VERSION 5.8 ;
BUSBITCHARS "[]" ;
DIVIDERCHAR "/" ;
UNITS
    DATABASE MICRONS 1000 ;
END UNITS

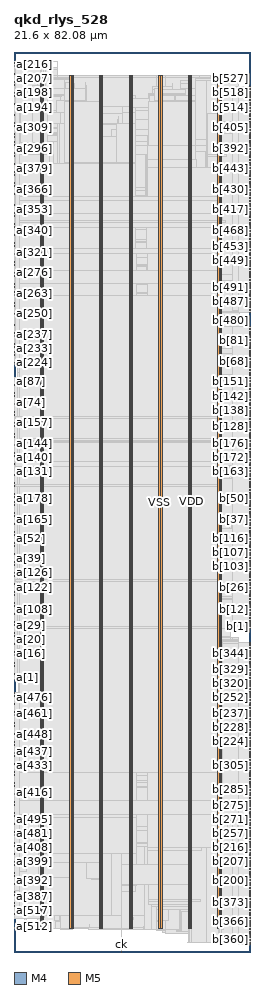
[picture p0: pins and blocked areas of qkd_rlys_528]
MACRO qkd_rlys_528
  FOREIGN qkd_rlys_528 0 0 ;
  CLASS BLOCK ;
  SIZE 21.6 BY 82.08 ;
  PIN a[0]
    DIRECTION INPUT ;
    USE SIGNAL ;
    PORT
      LAYER M4 ;
        RECT  0 24.912 0.084 24.936 ;
    END
  END a[0]
  PIN a[100]
    DIRECTION INPUT ;
    USE SIGNAL ;
    PORT
      LAYER M4 ;
        RECT  0 30.096 0.084 30.12 ;
    END
  END a[100]
  PIN a[101]
    DIRECTION INPUT ;
    USE SIGNAL ;
    PORT
      LAYER M4 ;
        RECT  0 30.24 0.084 30.264 ;
    END
  END a[101]
  PIN a[102]
    DIRECTION INPUT ;
    USE SIGNAL ;
    PORT
      LAYER M4 ;
        RECT  0 30.384 0.084 30.408 ;
    END
  END a[102]
  PIN a[103]
    DIRECTION INPUT ;
    USE SIGNAL ;
    PORT
      LAYER M4 ;
        RECT  0 30.528 0.084 30.552 ;
    END
  END a[103]
  PIN a[104]
    DIRECTION INPUT ;
    USE SIGNAL ;
    PORT
      LAYER M4 ;
        RECT  0 30.672 0.084 30.696 ;
    END
  END a[104]
  PIN a[105]
    DIRECTION INPUT ;
    USE SIGNAL ;
    PORT
      LAYER M4 ;
        RECT  0 30.816 0.084 30.84 ;
    END
  END a[105]
  PIN a[106]
    DIRECTION INPUT ;
    USE SIGNAL ;
    PORT
      LAYER M4 ;
        RECT  0 30.96 0.084 30.984 ;
    END
  END a[106]
  PIN a[107]
    DIRECTION INPUT ;
    USE SIGNAL ;
    PORT
      LAYER M4 ;
        RECT  0 31.104 0.084 31.128 ;
    END
  END a[107]
  PIN a[108]
    DIRECTION INPUT ;
    USE SIGNAL ;
    PORT
      LAYER M4 ;
        RECT  0 31.248 0.084 31.272 ;
    END
  END a[108]
  PIN a[109]
    DIRECTION INPUT ;
    USE SIGNAL ;
    PORT
      LAYER M4 ;
        RECT  0 31.392 0.084 31.416 ;
    END
  END a[109]
  PIN a[10]
    DIRECTION INPUT ;
    USE SIGNAL ;
    PORT
      LAYER M4 ;
        RECT  0 26.352 0.084 26.376 ;
    END
  END a[10]
  PIN a[110]
    DIRECTION INPUT ;
    USE SIGNAL ;
    PORT
      LAYER M4 ;
        RECT  0 31.536 0.084 31.56 ;
    END
  END a[110]
  PIN a[111]
    DIRECTION INPUT ;
    USE SIGNAL ;
    PORT
      LAYER M4 ;
        RECT  0 31.68 0.084 31.704 ;
    END
  END a[111]
  PIN a[112]
    DIRECTION INPUT ;
    USE SIGNAL ;
    PORT
      LAYER M4 ;
        RECT  0 31.824 0.084 31.848 ;
    END
  END a[112]
  PIN a[113]
    DIRECTION INPUT ;
    USE SIGNAL ;
    PORT
      LAYER M4 ;
        RECT  0 31.968 0.084 31.992 ;
    END
  END a[113]
  PIN a[114]
    DIRECTION INPUT ;
    USE SIGNAL ;
    PORT
      LAYER M4 ;
        RECT  0 32.112 0.084 32.136 ;
    END
  END a[114]
  PIN a[115]
    DIRECTION INPUT ;
    USE SIGNAL ;
    PORT
      LAYER M4 ;
        RECT  0 32.256 0.084 32.28 ;
    END
  END a[115]
  PIN a[116]
    DIRECTION INPUT ;
    USE SIGNAL ;
    PORT
      LAYER M4 ;
        RECT  0 32.4 0.084 32.424 ;
    END
  END a[116]
  PIN a[117]
    DIRECTION INPUT ;
    USE SIGNAL ;
    PORT
      LAYER M4 ;
        RECT  0 32.544 0.084 32.568 ;
    END
  END a[117]
  PIN a[118]
    DIRECTION INPUT ;
    USE SIGNAL ;
    PORT
      LAYER M4 ;
        RECT  0 32.688 0.084 32.712 ;
    END
  END a[118]
  PIN a[119]
    DIRECTION INPUT ;
    USE SIGNAL ;
    PORT
      LAYER M4 ;
        RECT  0 32.832 0.084 32.856 ;
    END
  END a[119]
  PIN a[11]
    DIRECTION INPUT ;
    USE SIGNAL ;
    PORT
      LAYER M4 ;
        RECT  0 26.496 0.084 26.52 ;
    END
  END a[11]
  PIN a[120]
    DIRECTION INPUT ;
    USE SIGNAL ;
    PORT
      LAYER M4 ;
        RECT  0 32.976 0.084 33 ;
    END
  END a[120]
  PIN a[121]
    DIRECTION INPUT ;
    USE SIGNAL ;
    PORT
      LAYER M4 ;
        RECT  0 33.12 0.084 33.144 ;
    END
  END a[121]
  PIN a[122]
    DIRECTION INPUT ;
    USE SIGNAL ;
    PORT
      LAYER M4 ;
        RECT  0 33.264 0.084 33.288 ;
    END
  END a[122]
  PIN a[123]
    DIRECTION INPUT ;
    USE SIGNAL ;
    PORT
      LAYER M4 ;
        RECT  0 33.408 0.084 33.432 ;
    END
  END a[123]
  PIN a[124]
    DIRECTION INPUT ;
    USE SIGNAL ;
    PORT
      LAYER M4 ;
        RECT  0 33.552 0.084 33.576 ;
    END
  END a[124]
  PIN a[125]
    DIRECTION INPUT ;
    USE SIGNAL ;
    PORT
      LAYER M4 ;
        RECT  0 33.696 0.084 33.72 ;
    END
  END a[125]
  PIN a[126]
    DIRECTION INPUT ;
    USE SIGNAL ;
    PORT
      LAYER M4 ;
        RECT  0 33.84 0.084 33.864 ;
    END
  END a[126]
  PIN a[127]
    DIRECTION INPUT ;
    USE SIGNAL ;
    PORT
      LAYER M4 ;
        RECT  0 33.984 0.084 34.008 ;
    END
  END a[127]
  PIN a[128]
    DIRECTION INPUT ;
    USE SIGNAL ;
    PORT
      LAYER M4 ;
        RECT  0 43.344 0.084 43.368 ;
    END
  END a[128]
  PIN a[129]
    DIRECTION INPUT ;
    USE SIGNAL ;
    PORT
      LAYER M4 ;
        RECT  0 43.488 0.084 43.512 ;
    END
  END a[129]
  PIN a[12]
    DIRECTION INPUT ;
    USE SIGNAL ;
    PORT
      LAYER M4 ;
        RECT  0 26.64 0.084 26.664 ;
    END
  END a[12]
  PIN a[130]
    DIRECTION INPUT ;
    USE SIGNAL ;
    PORT
      LAYER M4 ;
        RECT  0 43.632 0.084 43.656 ;
    END
  END a[130]
  PIN a[131]
    DIRECTION INPUT ;
    USE SIGNAL ;
    PORT
      LAYER M4 ;
        RECT  0 43.776 0.084 43.8 ;
    END
  END a[131]
  PIN a[132]
    DIRECTION INPUT ;
    USE SIGNAL ;
    PORT
      LAYER M4 ;
        RECT  0 43.92 0.084 43.944 ;
    END
  END a[132]
  PIN a[133]
    DIRECTION INPUT ;
    USE SIGNAL ;
    PORT
      LAYER M4 ;
        RECT  0 44.064 0.084 44.088 ;
    END
  END a[133]
  PIN a[134]
    DIRECTION INPUT ;
    USE SIGNAL ;
    PORT
      LAYER M4 ;
        RECT  0 44.208 0.084 44.232 ;
    END
  END a[134]
  PIN a[135]
    DIRECTION INPUT ;
    USE SIGNAL ;
    PORT
      LAYER M4 ;
        RECT  0 44.352 0.084 44.376 ;
    END
  END a[135]
  PIN a[136]
    DIRECTION INPUT ;
    USE SIGNAL ;
    PORT
      LAYER M4 ;
        RECT  0 44.496 0.084 44.52 ;
    END
  END a[136]
  PIN a[137]
    DIRECTION INPUT ;
    USE SIGNAL ;
    PORT
      LAYER M4 ;
        RECT  0 44.64 0.084 44.664 ;
    END
  END a[137]
  PIN a[138]
    DIRECTION INPUT ;
    USE SIGNAL ;
    PORT
      LAYER M4 ;
        RECT  0 44.784 0.084 44.808 ;
    END
  END a[138]
  PIN a[139]
    DIRECTION INPUT ;
    USE SIGNAL ;
    PORT
      LAYER M4 ;
        RECT  0 44.928 0.084 44.952 ;
    END
  END a[139]
  PIN a[13]
    DIRECTION INPUT ;
    USE SIGNAL ;
    PORT
      LAYER M4 ;
        RECT  0 26.784 0.084 26.808 ;
    END
  END a[13]
  PIN a[140]
    DIRECTION INPUT ;
    USE SIGNAL ;
    PORT
      LAYER M4 ;
        RECT  0 45.072 0.084 45.096 ;
    END
  END a[140]
  PIN a[141]
    DIRECTION INPUT ;
    USE SIGNAL ;
    PORT
      LAYER M4 ;
        RECT  0 45.216 0.084 45.24 ;
    END
  END a[141]
  PIN a[142]
    DIRECTION INPUT ;
    USE SIGNAL ;
    PORT
      LAYER M4 ;
        RECT  0 45.36 0.084 45.384 ;
    END
  END a[142]
  PIN a[143]
    DIRECTION INPUT ;
    USE SIGNAL ;
    PORT
      LAYER M4 ;
        RECT  0 45.504 0.084 45.528 ;
    END
  END a[143]
  PIN a[144]
    DIRECTION INPUT ;
    USE SIGNAL ;
    PORT
      LAYER M4 ;
        RECT  0 45.648 0.084 45.672 ;
    END
  END a[144]
  PIN a[145]
    DIRECTION INPUT ;
    USE SIGNAL ;
    PORT
      LAYER M4 ;
        RECT  0 45.792 0.084 45.816 ;
    END
  END a[145]
  PIN a[146]
    DIRECTION INPUT ;
    USE SIGNAL ;
    PORT
      LAYER M4 ;
        RECT  0 45.936 0.084 45.96 ;
    END
  END a[146]
  PIN a[147]
    DIRECTION INPUT ;
    USE SIGNAL ;
    PORT
      LAYER M4 ;
        RECT  0 46.08 0.084 46.104 ;
    END
  END a[147]
  PIN a[148]
    DIRECTION INPUT ;
    USE SIGNAL ;
    PORT
      LAYER M4 ;
        RECT  0 46.224 0.084 46.248 ;
    END
  END a[148]
  PIN a[149]
    DIRECTION INPUT ;
    USE SIGNAL ;
    PORT
      LAYER M4 ;
        RECT  0 46.368 0.084 46.392 ;
    END
  END a[149]
  PIN a[14]
    DIRECTION INPUT ;
    USE SIGNAL ;
    PORT
      LAYER M4 ;
        RECT  0 26.928 0.084 26.952 ;
    END
  END a[14]
  PIN a[150]
    DIRECTION INPUT ;
    USE SIGNAL ;
    PORT
      LAYER M4 ;
        RECT  0 46.512 0.084 46.536 ;
    END
  END a[150]
  PIN a[151]
    DIRECTION INPUT ;
    USE SIGNAL ;
    PORT
      LAYER M4 ;
        RECT  0 46.656 0.084 46.68 ;
    END
  END a[151]
  PIN a[152]
    DIRECTION INPUT ;
    USE SIGNAL ;
    PORT
      LAYER M4 ;
        RECT  0 46.8 0.084 46.824 ;
    END
  END a[152]
  PIN a[153]
    DIRECTION INPUT ;
    USE SIGNAL ;
    PORT
      LAYER M4 ;
        RECT  0 46.944 0.084 46.968 ;
    END
  END a[153]
  PIN a[154]
    DIRECTION INPUT ;
    USE SIGNAL ;
    PORT
      LAYER M4 ;
        RECT  0 47.088 0.084 47.112 ;
    END
  END a[154]
  PIN a[155]
    DIRECTION INPUT ;
    USE SIGNAL ;
    PORT
      LAYER M4 ;
        RECT  0 47.232 0.084 47.256 ;
    END
  END a[155]
  PIN a[156]
    DIRECTION INPUT ;
    USE SIGNAL ;
    PORT
      LAYER M4 ;
        RECT  0 47.376 0.084 47.4 ;
    END
  END a[156]
  PIN a[157]
    DIRECTION INPUT ;
    USE SIGNAL ;
    PORT
      LAYER M4 ;
        RECT  0 47.52 0.084 47.544 ;
    END
  END a[157]
  PIN a[158]
    DIRECTION INPUT ;
    USE SIGNAL ;
    PORT
      LAYER M4 ;
        RECT  0 47.664 0.084 47.688 ;
    END
  END a[158]
  PIN a[159]
    DIRECTION INPUT ;
    USE SIGNAL ;
    PORT
      LAYER M4 ;
        RECT  0 47.808 0.084 47.832 ;
    END
  END a[159]
  PIN a[15]
    DIRECTION INPUT ;
    USE SIGNAL ;
    PORT
      LAYER M4 ;
        RECT  0 27.072 0.084 27.096 ;
    END
  END a[15]
  PIN a[160]
    DIRECTION INPUT ;
    USE SIGNAL ;
    PORT
      LAYER M4 ;
        RECT  0 38.736 0.084 38.76 ;
    END
  END a[160]
  PIN a[161]
    DIRECTION INPUT ;
    USE SIGNAL ;
    PORT
      LAYER M4 ;
        RECT  0 38.88 0.084 38.904 ;
    END
  END a[161]
  PIN a[162]
    DIRECTION INPUT ;
    USE SIGNAL ;
    PORT
      LAYER M4 ;
        RECT  0 39.024 0.084 39.048 ;
    END
  END a[162]
  PIN a[163]
    DIRECTION INPUT ;
    USE SIGNAL ;
    PORT
      LAYER M4 ;
        RECT  0 39.168 0.084 39.192 ;
    END
  END a[163]
  PIN a[164]
    DIRECTION INPUT ;
    USE SIGNAL ;
    PORT
      LAYER M4 ;
        RECT  0 39.312 0.084 39.336 ;
    END
  END a[164]
  PIN a[165]
    DIRECTION INPUT ;
    USE SIGNAL ;
    PORT
      LAYER M4 ;
        RECT  0 39.456 0.084 39.48 ;
    END
  END a[165]
  PIN a[166]
    DIRECTION INPUT ;
    USE SIGNAL ;
    PORT
      LAYER M4 ;
        RECT  0 39.6 0.084 39.624 ;
    END
  END a[166]
  PIN a[167]
    DIRECTION INPUT ;
    USE SIGNAL ;
    PORT
      LAYER M4 ;
        RECT  0 39.744 0.084 39.768 ;
    END
  END a[167]
  PIN a[168]
    DIRECTION INPUT ;
    USE SIGNAL ;
    PORT
      LAYER M4 ;
        RECT  0 39.888 0.084 39.912 ;
    END
  END a[168]
  PIN a[169]
    DIRECTION INPUT ;
    USE SIGNAL ;
    PORT
      LAYER M4 ;
        RECT  0 40.032 0.084 40.056 ;
    END
  END a[169]
  PIN a[16]
    DIRECTION INPUT ;
    USE SIGNAL ;
    PORT
      LAYER M4 ;
        RECT  0 27.216 0.084 27.24 ;
    END
  END a[16]
  PIN a[170]
    DIRECTION INPUT ;
    USE SIGNAL ;
    PORT
      LAYER M4 ;
        RECT  0 40.176 0.084 40.2 ;
    END
  END a[170]
  PIN a[171]
    DIRECTION INPUT ;
    USE SIGNAL ;
    PORT
      LAYER M4 ;
        RECT  0 40.32 0.084 40.344 ;
    END
  END a[171]
  PIN a[172]
    DIRECTION INPUT ;
    USE SIGNAL ;
    PORT
      LAYER M4 ;
        RECT  0 40.464 0.084 40.488 ;
    END
  END a[172]
  PIN a[173]
    DIRECTION INPUT ;
    USE SIGNAL ;
    PORT
      LAYER M4 ;
        RECT  0 40.608 0.084 40.632 ;
    END
  END a[173]
  PIN a[174]
    DIRECTION INPUT ;
    USE SIGNAL ;
    PORT
      LAYER M4 ;
        RECT  0 40.752 0.084 40.776 ;
    END
  END a[174]
  PIN a[175]
    DIRECTION INPUT ;
    USE SIGNAL ;
    PORT
      LAYER M4 ;
        RECT  0 40.896 0.084 40.92 ;
    END
  END a[175]
  PIN a[176]
    DIRECTION INPUT ;
    USE SIGNAL ;
    PORT
      LAYER M4 ;
        RECT  0 41.04 0.084 41.064 ;
    END
  END a[176]
  PIN a[177]
    DIRECTION INPUT ;
    USE SIGNAL ;
    PORT
      LAYER M4 ;
        RECT  0 41.184 0.084 41.208 ;
    END
  END a[177]
  PIN a[178]
    DIRECTION INPUT ;
    USE SIGNAL ;
    PORT
      LAYER M4 ;
        RECT  0 41.328 0.084 41.352 ;
    END
  END a[178]
  PIN a[179]
    DIRECTION INPUT ;
    USE SIGNAL ;
    PORT
      LAYER M4 ;
        RECT  0 41.472 0.084 41.496 ;
    END
  END a[179]
  PIN a[17]
    DIRECTION INPUT ;
    USE SIGNAL ;
    PORT
      LAYER M4 ;
        RECT  0 27.36 0.084 27.384 ;
    END
  END a[17]
  PIN a[180]
    DIRECTION INPUT ;
    USE SIGNAL ;
    PORT
      LAYER M4 ;
        RECT  0 41.616 0.084 41.64 ;
    END
  END a[180]
  PIN a[181]
    DIRECTION INPUT ;
    USE SIGNAL ;
    PORT
      LAYER M4 ;
        RECT  0 41.76 0.084 41.784 ;
    END
  END a[181]
  PIN a[182]
    DIRECTION INPUT ;
    USE SIGNAL ;
    PORT
      LAYER M4 ;
        RECT  0 41.904 0.084 41.928 ;
    END
  END a[182]
  PIN a[183]
    DIRECTION INPUT ;
    USE SIGNAL ;
    PORT
      LAYER M4 ;
        RECT  0 42.048 0.084 42.072 ;
    END
  END a[183]
  PIN a[184]
    DIRECTION INPUT ;
    USE SIGNAL ;
    PORT
      LAYER M4 ;
        RECT  0 42.192 0.084 42.216 ;
    END
  END a[184]
  PIN a[185]
    DIRECTION INPUT ;
    USE SIGNAL ;
    PORT
      LAYER M4 ;
        RECT  0 42.336 0.084 42.36 ;
    END
  END a[185]
  PIN a[186]
    DIRECTION INPUT ;
    USE SIGNAL ;
    PORT
      LAYER M4 ;
        RECT  0 42.48 0.084 42.504 ;
    END
  END a[186]
  PIN a[187]
    DIRECTION INPUT ;
    USE SIGNAL ;
    PORT
      LAYER M4 ;
        RECT  0 42.624 0.084 42.648 ;
    END
  END a[187]
  PIN a[188]
    DIRECTION INPUT ;
    USE SIGNAL ;
    PORT
      LAYER M4 ;
        RECT  0 42.768 0.084 42.792 ;
    END
  END a[188]
  PIN a[189]
    DIRECTION INPUT ;
    USE SIGNAL ;
    PORT
      LAYER M4 ;
        RECT  0 42.912 0.084 42.936 ;
    END
  END a[189]
  PIN a[18]
    DIRECTION INPUT ;
    USE SIGNAL ;
    PORT
      LAYER M4 ;
        RECT  0 27.504 0.084 27.528 ;
    END
  END a[18]
  PIN a[190]
    DIRECTION INPUT ;
    USE SIGNAL ;
    PORT
      LAYER M4 ;
        RECT  0 43.056 0.084 43.08 ;
    END
  END a[190]
  PIN a[191]
    DIRECTION INPUT ;
    USE SIGNAL ;
    PORT
      LAYER M4 ;
        RECT  0 43.2 0.084 43.224 ;
    END
  END a[191]
  PIN a[192]
    DIRECTION INPUT ;
    USE SIGNAL ;
    PORT
      LAYER M4 ;
        RECT  0 76.752 0.084 76.776 ;
    END
  END a[192]
  PIN a[193]
    DIRECTION INPUT ;
    USE SIGNAL ;
    PORT
      LAYER M4 ;
        RECT  0 76.896 0.084 76.92 ;
    END
  END a[193]
  PIN a[194]
    DIRECTION INPUT ;
    USE SIGNAL ;
    PORT
      LAYER M4 ;
        RECT  0 77.04 0.084 77.064 ;
    END
  END a[194]
  PIN a[195]
    DIRECTION INPUT ;
    USE SIGNAL ;
    PORT
      LAYER M4 ;
        RECT  0 77.184 0.084 77.208 ;
    END
  END a[195]
  PIN a[196]
    DIRECTION INPUT ;
    USE SIGNAL ;
    PORT
      LAYER M4 ;
        RECT  0 77.328 0.084 77.352 ;
    END
  END a[196]
  PIN a[197]
    DIRECTION INPUT ;
    USE SIGNAL ;
    PORT
      LAYER M4 ;
        RECT  0 77.472 0.084 77.496 ;
    END
  END a[197]
  PIN a[198]
    DIRECTION INPUT ;
    USE SIGNAL ;
    PORT
      LAYER M4 ;
        RECT  0 77.616 0.084 77.64 ;
    END
  END a[198]
  PIN a[199]
    DIRECTION INPUT ;
    USE SIGNAL ;
    PORT
      LAYER M4 ;
        RECT  0 77.76 0.084 77.784 ;
    END
  END a[199]
  PIN a[19]
    DIRECTION INPUT ;
    USE SIGNAL ;
    PORT
      LAYER M4 ;
        RECT  0 27.648 0.084 27.672 ;
    END
  END a[19]
  PIN a[1]
    DIRECTION INPUT ;
    USE SIGNAL ;
    PORT
      LAYER M4 ;
        RECT  0 25.056 0.084 25.08 ;
    END
  END a[1]
  PIN a[200]
    DIRECTION INPUT ;
    USE SIGNAL ;
    PORT
      LAYER M4 ;
        RECT  0 77.904 0.084 77.928 ;
    END
  END a[200]
  PIN a[201]
    DIRECTION INPUT ;
    USE SIGNAL ;
    PORT
      LAYER M4 ;
        RECT  0 78.048 0.084 78.072 ;
    END
  END a[201]
  PIN a[202]
    DIRECTION INPUT ;
    USE SIGNAL ;
    PORT
      LAYER M4 ;
        RECT  0 78.192 0.084 78.216 ;
    END
  END a[202]
  PIN a[203]
    DIRECTION INPUT ;
    USE SIGNAL ;
    PORT
      LAYER M4 ;
        RECT  0 78.336 0.084 78.36 ;
    END
  END a[203]
  PIN a[204]
    DIRECTION INPUT ;
    USE SIGNAL ;
    PORT
      LAYER M4 ;
        RECT  0 78.48 0.084 78.504 ;
    END
  END a[204]
  PIN a[205]
    DIRECTION INPUT ;
    USE SIGNAL ;
    PORT
      LAYER M4 ;
        RECT  0 78.624 0.084 78.648 ;
    END
  END a[205]
  PIN a[206]
    DIRECTION INPUT ;
    USE SIGNAL ;
    PORT
      LAYER M4 ;
        RECT  0 78.768 0.084 78.792 ;
    END
  END a[206]
  PIN a[207]
    DIRECTION INPUT ;
    USE SIGNAL ;
    PORT
      LAYER M4 ;
        RECT  0 78.912 0.084 78.936 ;
    END
  END a[207]
  PIN a[208]
    DIRECTION INPUT ;
    USE SIGNAL ;
    PORT
      LAYER M4 ;
        RECT  0 79.056 0.084 79.08 ;
    END
  END a[208]
  PIN a[209]
    DIRECTION INPUT ;
    USE SIGNAL ;
    PORT
      LAYER M4 ;
        RECT  0 79.2 0.084 79.224 ;
    END
  END a[209]
  PIN a[20]
    DIRECTION INPUT ;
    USE SIGNAL ;
    PORT
      LAYER M4 ;
        RECT  0 27.792 0.084 27.816 ;
    END
  END a[20]
  PIN a[210]
    DIRECTION INPUT ;
    USE SIGNAL ;
    PORT
      LAYER M4 ;
        RECT  0 79.344 0.084 79.368 ;
    END
  END a[210]
  PIN a[211]
    DIRECTION INPUT ;
    USE SIGNAL ;
    PORT
      LAYER M4 ;
        RECT  0 79.488 0.084 79.512 ;
    END
  END a[211]
  PIN a[212]
    DIRECTION INPUT ;
    USE SIGNAL ;
    PORT
      LAYER M4 ;
        RECT  0 79.632 0.084 79.656 ;
    END
  END a[212]
  PIN a[213]
    DIRECTION INPUT ;
    USE SIGNAL ;
    PORT
      LAYER M4 ;
        RECT  0 79.776 0.084 79.8 ;
    END
  END a[213]
  PIN a[214]
    DIRECTION INPUT ;
    USE SIGNAL ;
    PORT
      LAYER M4 ;
        RECT  0 79.92 0.084 79.944 ;
    END
  END a[214]
  PIN a[215]
    DIRECTION INPUT ;
    USE SIGNAL ;
    PORT
      LAYER M4 ;
        RECT  0 80.064 0.084 80.088 ;
    END
  END a[215]
  PIN a[216]
    DIRECTION INPUT ;
    USE SIGNAL ;
    PORT
      LAYER M4 ;
        RECT  0 80.208 0.084 80.232 ;
    END
  END a[216]
  PIN a[217]
    DIRECTION INPUT ;
    USE SIGNAL ;
    PORT
      LAYER M4 ;
        RECT  0 80.352 0.084 80.376 ;
    END
  END a[217]
  PIN a[218]
    DIRECTION INPUT ;
    USE SIGNAL ;
    PORT
      LAYER M4 ;
        RECT  0 80.496 0.084 80.52 ;
    END
  END a[218]
  PIN a[219]
    DIRECTION INPUT ;
    USE SIGNAL ;
    PORT
      LAYER M4 ;
        RECT  0 80.64 0.084 80.664 ;
    END
  END a[219]
  PIN a[21]
    DIRECTION INPUT ;
    USE SIGNAL ;
    PORT
      LAYER M4 ;
        RECT  0 27.936 0.084 27.96 ;
    END
  END a[21]
  PIN a[220]
    DIRECTION INPUT ;
    USE SIGNAL ;
    PORT
      LAYER M4 ;
        RECT  0 80.784 0.084 80.808 ;
    END
  END a[220]
  PIN a[221]
    DIRECTION INPUT ;
    USE SIGNAL ;
    PORT
      LAYER M4 ;
        RECT  0 80.928 0.084 80.952 ;
    END
  END a[221]
  PIN a[222]
    DIRECTION INPUT ;
    USE SIGNAL ;
    PORT
      LAYER M4 ;
        RECT  0 81.072 0.084 81.096 ;
    END
  END a[222]
  PIN a[223]
    DIRECTION INPUT ;
    USE SIGNAL ;
    PORT
      LAYER M4 ;
        RECT  0 81.216 0.084 81.24 ;
    END
  END a[223]
  PIN a[224]
    DIRECTION INPUT ;
    USE SIGNAL ;
    PORT
      LAYER M4 ;
        RECT  0 53.712 0.084 53.736 ;
    END
  END a[224]
  PIN a[225]
    DIRECTION INPUT ;
    USE SIGNAL ;
    PORT
      LAYER M4 ;
        RECT  0 53.856 0.084 53.88 ;
    END
  END a[225]
  PIN a[226]
    DIRECTION INPUT ;
    USE SIGNAL ;
    PORT
      LAYER M4 ;
        RECT  0 54 0.084 54.024 ;
    END
  END a[226]
  PIN a[227]
    DIRECTION INPUT ;
    USE SIGNAL ;
    PORT
      LAYER M4 ;
        RECT  0 54.144 0.084 54.168 ;
    END
  END a[227]
  PIN a[228]
    DIRECTION INPUT ;
    USE SIGNAL ;
    PORT
      LAYER M4 ;
        RECT  0 54.288 0.084 54.312 ;
    END
  END a[228]
  PIN a[229]
    DIRECTION INPUT ;
    USE SIGNAL ;
    PORT
      LAYER M4 ;
        RECT  0 54.432 0.084 54.456 ;
    END
  END a[229]
  PIN a[22]
    DIRECTION INPUT ;
    USE SIGNAL ;
    PORT
      LAYER M4 ;
        RECT  0 28.08 0.084 28.104 ;
    END
  END a[22]
  PIN a[230]
    DIRECTION INPUT ;
    USE SIGNAL ;
    PORT
      LAYER M4 ;
        RECT  0 54.576 0.084 54.6 ;
    END
  END a[230]
  PIN a[231]
    DIRECTION INPUT ;
    USE SIGNAL ;
    PORT
      LAYER M4 ;
        RECT  0 54.72 0.084 54.744 ;
    END
  END a[231]
  PIN a[232]
    DIRECTION INPUT ;
    USE SIGNAL ;
    PORT
      LAYER M4 ;
        RECT  0 54.864 0.084 54.888 ;
    END
  END a[232]
  PIN a[233]
    DIRECTION INPUT ;
    USE SIGNAL ;
    PORT
      LAYER M4 ;
        RECT  0 55.008 0.084 55.032 ;
    END
  END a[233]
  PIN a[234]
    DIRECTION INPUT ;
    USE SIGNAL ;
    PORT
      LAYER M4 ;
        RECT  0 55.152 0.084 55.176 ;
    END
  END a[234]
  PIN a[235]
    DIRECTION INPUT ;
    USE SIGNAL ;
    PORT
      LAYER M4 ;
        RECT  0 55.296 0.084 55.32 ;
    END
  END a[235]
  PIN a[236]
    DIRECTION INPUT ;
    USE SIGNAL ;
    PORT
      LAYER M4 ;
        RECT  0 55.44 0.084 55.464 ;
    END
  END a[236]
  PIN a[237]
    DIRECTION INPUT ;
    USE SIGNAL ;
    PORT
      LAYER M4 ;
        RECT  0 55.584 0.084 55.608 ;
    END
  END a[237]
  PIN a[238]
    DIRECTION INPUT ;
    USE SIGNAL ;
    PORT
      LAYER M4 ;
        RECT  0 55.728 0.084 55.752 ;
    END
  END a[238]
  PIN a[239]
    DIRECTION INPUT ;
    USE SIGNAL ;
    PORT
      LAYER M4 ;
        RECT  0 55.872 0.084 55.896 ;
    END
  END a[239]
  PIN a[23]
    DIRECTION INPUT ;
    USE SIGNAL ;
    PORT
      LAYER M4 ;
        RECT  0 28.224 0.084 28.248 ;
    END
  END a[23]
  PIN a[240]
    DIRECTION INPUT ;
    USE SIGNAL ;
    PORT
      LAYER M4 ;
        RECT  0 56.016 0.084 56.04 ;
    END
  END a[240]
  PIN a[241]
    DIRECTION INPUT ;
    USE SIGNAL ;
    PORT
      LAYER M4 ;
        RECT  0 56.16 0.084 56.184 ;
    END
  END a[241]
  PIN a[242]
    DIRECTION INPUT ;
    USE SIGNAL ;
    PORT
      LAYER M4 ;
        RECT  0 56.304 0.084 56.328 ;
    END
  END a[242]
  PIN a[243]
    DIRECTION INPUT ;
    USE SIGNAL ;
    PORT
      LAYER M4 ;
        RECT  0 56.448 0.084 56.472 ;
    END
  END a[243]
  PIN a[244]
    DIRECTION INPUT ;
    USE SIGNAL ;
    PORT
      LAYER M4 ;
        RECT  0 56.592 0.084 56.616 ;
    END
  END a[244]
  PIN a[245]
    DIRECTION INPUT ;
    USE SIGNAL ;
    PORT
      LAYER M4 ;
        RECT  0 56.736 0.084 56.76 ;
    END
  END a[245]
  PIN a[246]
    DIRECTION INPUT ;
    USE SIGNAL ;
    PORT
      LAYER M4 ;
        RECT  0 56.88 0.084 56.904 ;
    END
  END a[246]
  PIN a[247]
    DIRECTION INPUT ;
    USE SIGNAL ;
    PORT
      LAYER M4 ;
        RECT  0 57.024 0.084 57.048 ;
    END
  END a[247]
  PIN a[248]
    DIRECTION INPUT ;
    USE SIGNAL ;
    PORT
      LAYER M4 ;
        RECT  0 57.168 0.084 57.192 ;
    END
  END a[248]
  PIN a[249]
    DIRECTION INPUT ;
    USE SIGNAL ;
    PORT
      LAYER M4 ;
        RECT  0 57.312 0.084 57.336 ;
    END
  END a[249]
  PIN a[24]
    DIRECTION INPUT ;
    USE SIGNAL ;
    PORT
      LAYER M4 ;
        RECT  0 28.368 0.084 28.392 ;
    END
  END a[24]
  PIN a[250]
    DIRECTION INPUT ;
    USE SIGNAL ;
    PORT
      LAYER M4 ;
        RECT  0 57.456 0.084 57.48 ;
    END
  END a[250]
  PIN a[251]
    DIRECTION INPUT ;
    USE SIGNAL ;
    PORT
      LAYER M4 ;
        RECT  0 57.6 0.084 57.624 ;
    END
  END a[251]
  PIN a[252]
    DIRECTION INPUT ;
    USE SIGNAL ;
    PORT
      LAYER M4 ;
        RECT  0 57.744 0.084 57.768 ;
    END
  END a[252]
  PIN a[253]
    DIRECTION INPUT ;
    USE SIGNAL ;
    PORT
      LAYER M4 ;
        RECT  0 57.888 0.084 57.912 ;
    END
  END a[253]
  PIN a[254]
    DIRECTION INPUT ;
    USE SIGNAL ;
    PORT
      LAYER M4 ;
        RECT  0 58.032 0.084 58.056 ;
    END
  END a[254]
  PIN a[255]
    DIRECTION INPUT ;
    USE SIGNAL ;
    PORT
      LAYER M4 ;
        RECT  0 58.176 0.084 58.2 ;
    END
  END a[255]
  PIN a[256]
    DIRECTION INPUT ;
    USE SIGNAL ;
    PORT
      LAYER M4 ;
        RECT  0 58.32 0.084 58.344 ;
    END
  END a[256]
  PIN a[257]
    DIRECTION INPUT ;
    USE SIGNAL ;
    PORT
      LAYER M4 ;
        RECT  0 58.464 0.084 58.488 ;
    END
  END a[257]
  PIN a[258]
    DIRECTION INPUT ;
    USE SIGNAL ;
    PORT
      LAYER M4 ;
        RECT  0 58.608 0.084 58.632 ;
    END
  END a[258]
  PIN a[259]
    DIRECTION INPUT ;
    USE SIGNAL ;
    PORT
      LAYER M4 ;
        RECT  0 58.752 0.084 58.776 ;
    END
  END a[259]
  PIN a[25]
    DIRECTION INPUT ;
    USE SIGNAL ;
    PORT
      LAYER M4 ;
        RECT  0 28.512 0.084 28.536 ;
    END
  END a[25]
  PIN a[260]
    DIRECTION INPUT ;
    USE SIGNAL ;
    PORT
      LAYER M4 ;
        RECT  0 58.896 0.084 58.92 ;
    END
  END a[260]
  PIN a[261]
    DIRECTION INPUT ;
    USE SIGNAL ;
    PORT
      LAYER M4 ;
        RECT  0 59.04 0.084 59.064 ;
    END
  END a[261]
  PIN a[262]
    DIRECTION INPUT ;
    USE SIGNAL ;
    PORT
      LAYER M4 ;
        RECT  0 59.184 0.084 59.208 ;
    END
  END a[262]
  PIN a[263]
    DIRECTION INPUT ;
    USE SIGNAL ;
    PORT
      LAYER M4 ;
        RECT  0 59.328 0.084 59.352 ;
    END
  END a[263]
  PIN a[264]
    DIRECTION INPUT ;
    USE SIGNAL ;
    PORT
      LAYER M4 ;
        RECT  0 59.472 0.084 59.496 ;
    END
  END a[264]
  PIN a[265]
    DIRECTION INPUT ;
    USE SIGNAL ;
    PORT
      LAYER M4 ;
        RECT  0 59.616 0.084 59.64 ;
    END
  END a[265]
  PIN a[266]
    DIRECTION INPUT ;
    USE SIGNAL ;
    PORT
      LAYER M4 ;
        RECT  0 59.76 0.084 59.784 ;
    END
  END a[266]
  PIN a[267]
    DIRECTION INPUT ;
    USE SIGNAL ;
    PORT
      LAYER M4 ;
        RECT  0 59.904 0.084 59.928 ;
    END
  END a[267]
  PIN a[268]
    DIRECTION INPUT ;
    USE SIGNAL ;
    PORT
      LAYER M4 ;
        RECT  0 60.048 0.084 60.072 ;
    END
  END a[268]
  PIN a[269]
    DIRECTION INPUT ;
    USE SIGNAL ;
    PORT
      LAYER M4 ;
        RECT  0 60.192 0.084 60.216 ;
    END
  END a[269]
  PIN a[26]
    DIRECTION INPUT ;
    USE SIGNAL ;
    PORT
      LAYER M4 ;
        RECT  0 28.656 0.084 28.68 ;
    END
  END a[26]
  PIN a[270]
    DIRECTION INPUT ;
    USE SIGNAL ;
    PORT
      LAYER M4 ;
        RECT  0 60.336 0.084 60.36 ;
    END
  END a[270]
  PIN a[271]
    DIRECTION INPUT ;
    USE SIGNAL ;
    PORT
      LAYER M4 ;
        RECT  0 60.48 0.084 60.504 ;
    END
  END a[271]
  PIN a[272]
    DIRECTION INPUT ;
    USE SIGNAL ;
    PORT
      LAYER M4 ;
        RECT  0 60.624 0.084 60.648 ;
    END
  END a[272]
  PIN a[273]
    DIRECTION INPUT ;
    USE SIGNAL ;
    PORT
      LAYER M4 ;
        RECT  0 60.768 0.084 60.792 ;
    END
  END a[273]
  PIN a[274]
    DIRECTION INPUT ;
    USE SIGNAL ;
    PORT
      LAYER M4 ;
        RECT  0 60.912 0.084 60.936 ;
    END
  END a[274]
  PIN a[275]
    DIRECTION INPUT ;
    USE SIGNAL ;
    PORT
      LAYER M4 ;
        RECT  0 61.056 0.084 61.08 ;
    END
  END a[275]
  PIN a[276]
    DIRECTION INPUT ;
    USE SIGNAL ;
    PORT
      LAYER M4 ;
        RECT  0 61.2 0.084 61.224 ;
    END
  END a[276]
  PIN a[277]
    DIRECTION INPUT ;
    USE SIGNAL ;
    PORT
      LAYER M4 ;
        RECT  0 61.344 0.084 61.368 ;
    END
  END a[277]
  PIN a[278]
    DIRECTION INPUT ;
    USE SIGNAL ;
    PORT
      LAYER M4 ;
        RECT  0 61.488 0.084 61.512 ;
    END
  END a[278]
  PIN a[279]
    DIRECTION INPUT ;
    USE SIGNAL ;
    PORT
      LAYER M4 ;
        RECT  0 61.632 0.084 61.656 ;
    END
  END a[279]
  PIN a[27]
    DIRECTION INPUT ;
    USE SIGNAL ;
    PORT
      LAYER M4 ;
        RECT  0 28.8 0.084 28.824 ;
    END
  END a[27]
  PIN a[280]
    DIRECTION INPUT ;
    USE SIGNAL ;
    PORT
      LAYER M4 ;
        RECT  0 61.776 0.084 61.8 ;
    END
  END a[280]
  PIN a[281]
    DIRECTION INPUT ;
    USE SIGNAL ;
    PORT
      LAYER M4 ;
        RECT  0 61.92 0.084 61.944 ;
    END
  END a[281]
  PIN a[282]
    DIRECTION INPUT ;
    USE SIGNAL ;
    PORT
      LAYER M4 ;
        RECT  0 62.064 0.084 62.088 ;
    END
  END a[282]
  PIN a[283]
    DIRECTION INPUT ;
    USE SIGNAL ;
    PORT
      LAYER M4 ;
        RECT  0 62.208 0.084 62.232 ;
    END
  END a[283]
  PIN a[284]
    DIRECTION INPUT ;
    USE SIGNAL ;
    PORT
      LAYER M4 ;
        RECT  0 62.352 0.084 62.376 ;
    END
  END a[284]
  PIN a[285]
    DIRECTION INPUT ;
    USE SIGNAL ;
    PORT
      LAYER M4 ;
        RECT  0 62.496 0.084 62.52 ;
    END
  END a[285]
  PIN a[286]
    DIRECTION INPUT ;
    USE SIGNAL ;
    PORT
      LAYER M4 ;
        RECT  0 62.64 0.084 62.664 ;
    END
  END a[286]
  PIN a[287]
    DIRECTION INPUT ;
    USE SIGNAL ;
    PORT
      LAYER M4 ;
        RECT  0 62.784 0.084 62.808 ;
    END
  END a[287]
  PIN a[288]
    DIRECTION INPUT ;
    USE SIGNAL ;
    PORT
      LAYER M4 ;
        RECT  0 72.144 0.084 72.168 ;
    END
  END a[288]
  PIN a[289]
    DIRECTION INPUT ;
    USE SIGNAL ;
    PORT
      LAYER M4 ;
        RECT  0 72.288 0.084 72.312 ;
    END
  END a[289]
  PIN a[28]
    DIRECTION INPUT ;
    USE SIGNAL ;
    PORT
      LAYER M4 ;
        RECT  0 28.944 0.084 28.968 ;
    END
  END a[28]
  PIN a[290]
    DIRECTION INPUT ;
    USE SIGNAL ;
    PORT
      LAYER M4 ;
        RECT  0 72.432 0.084 72.456 ;
    END
  END a[290]
  PIN a[291]
    DIRECTION INPUT ;
    USE SIGNAL ;
    PORT
      LAYER M4 ;
        RECT  0 72.576 0.084 72.6 ;
    END
  END a[291]
  PIN a[292]
    DIRECTION INPUT ;
    USE SIGNAL ;
    PORT
      LAYER M4 ;
        RECT  0 72.72 0.084 72.744 ;
    END
  END a[292]
  PIN a[293]
    DIRECTION INPUT ;
    USE SIGNAL ;
    PORT
      LAYER M4 ;
        RECT  0 72.864 0.084 72.888 ;
    END
  END a[293]
  PIN a[294]
    DIRECTION INPUT ;
    USE SIGNAL ;
    PORT
      LAYER M4 ;
        RECT  0 73.008 0.084 73.032 ;
    END
  END a[294]
  PIN a[295]
    DIRECTION INPUT ;
    USE SIGNAL ;
    PORT
      LAYER M4 ;
        RECT  0 73.152 0.084 73.176 ;
    END
  END a[295]
  PIN a[296]
    DIRECTION INPUT ;
    USE SIGNAL ;
    PORT
      LAYER M4 ;
        RECT  0 73.296 0.084 73.32 ;
    END
  END a[296]
  PIN a[297]
    DIRECTION INPUT ;
    USE SIGNAL ;
    PORT
      LAYER M4 ;
        RECT  0 73.44 0.084 73.464 ;
    END
  END a[297]
  PIN a[298]
    DIRECTION INPUT ;
    USE SIGNAL ;
    PORT
      LAYER M4 ;
        RECT  0 73.584 0.084 73.608 ;
    END
  END a[298]
  PIN a[299]
    DIRECTION INPUT ;
    USE SIGNAL ;
    PORT
      LAYER M4 ;
        RECT  0 73.728 0.084 73.752 ;
    END
  END a[299]
  PIN a[29]
    DIRECTION INPUT ;
    USE SIGNAL ;
    PORT
      LAYER M4 ;
        RECT  0 29.088 0.084 29.112 ;
    END
  END a[29]
  PIN a[2]
    DIRECTION INPUT ;
    USE SIGNAL ;
    PORT
      LAYER M4 ;
        RECT  0 25.2 0.084 25.224 ;
    END
  END a[2]
  PIN a[300]
    DIRECTION INPUT ;
    USE SIGNAL ;
    PORT
      LAYER M4 ;
        RECT  0 73.872 0.084 73.896 ;
    END
  END a[300]
  PIN a[301]
    DIRECTION INPUT ;
    USE SIGNAL ;
    PORT
      LAYER M4 ;
        RECT  0 74.016 0.084 74.04 ;
    END
  END a[301]
  PIN a[302]
    DIRECTION INPUT ;
    USE SIGNAL ;
    PORT
      LAYER M4 ;
        RECT  0 74.16 0.084 74.184 ;
    END
  END a[302]
  PIN a[303]
    DIRECTION INPUT ;
    USE SIGNAL ;
    PORT
      LAYER M4 ;
        RECT  0 74.304 0.084 74.328 ;
    END
  END a[303]
  PIN a[304]
    DIRECTION INPUT ;
    USE SIGNAL ;
    PORT
      LAYER M4 ;
        RECT  0 74.448 0.084 74.472 ;
    END
  END a[304]
  PIN a[305]
    DIRECTION INPUT ;
    USE SIGNAL ;
    PORT
      LAYER M4 ;
        RECT  0 74.592 0.084 74.616 ;
    END
  END a[305]
  PIN a[306]
    DIRECTION INPUT ;
    USE SIGNAL ;
    PORT
      LAYER M4 ;
        RECT  0 74.736 0.084 74.76 ;
    END
  END a[306]
  PIN a[307]
    DIRECTION INPUT ;
    USE SIGNAL ;
    PORT
      LAYER M4 ;
        RECT  0 74.88 0.084 74.904 ;
    END
  END a[307]
  PIN a[308]
    DIRECTION INPUT ;
    USE SIGNAL ;
    PORT
      LAYER M4 ;
        RECT  0 75.024 0.084 75.048 ;
    END
  END a[308]
  PIN a[309]
    DIRECTION INPUT ;
    USE SIGNAL ;
    PORT
      LAYER M4 ;
        RECT  0 75.168 0.084 75.192 ;
    END
  END a[309]
  PIN a[30]
    DIRECTION INPUT ;
    USE SIGNAL ;
    PORT
      LAYER M4 ;
        RECT  0 29.232 0.084 29.256 ;
    END
  END a[30]
  PIN a[310]
    DIRECTION INPUT ;
    USE SIGNAL ;
    PORT
      LAYER M4 ;
        RECT  0 75.312 0.084 75.336 ;
    END
  END a[310]
  PIN a[311]
    DIRECTION INPUT ;
    USE SIGNAL ;
    PORT
      LAYER M4 ;
        RECT  0 75.456 0.084 75.48 ;
    END
  END a[311]
  PIN a[312]
    DIRECTION INPUT ;
    USE SIGNAL ;
    PORT
      LAYER M4 ;
        RECT  0 75.6 0.084 75.624 ;
    END
  END a[312]
  PIN a[313]
    DIRECTION INPUT ;
    USE SIGNAL ;
    PORT
      LAYER M4 ;
        RECT  0 75.744 0.084 75.768 ;
    END
  END a[313]
  PIN a[314]
    DIRECTION INPUT ;
    USE SIGNAL ;
    PORT
      LAYER M4 ;
        RECT  0 75.888 0.084 75.912 ;
    END
  END a[314]
  PIN a[315]
    DIRECTION INPUT ;
    USE SIGNAL ;
    PORT
      LAYER M4 ;
        RECT  0 76.032 0.084 76.056 ;
    END
  END a[315]
  PIN a[316]
    DIRECTION INPUT ;
    USE SIGNAL ;
    PORT
      LAYER M4 ;
        RECT  0 76.176 0.084 76.2 ;
    END
  END a[316]
  PIN a[317]
    DIRECTION INPUT ;
    USE SIGNAL ;
    PORT
      LAYER M4 ;
        RECT  0 76.32 0.084 76.344 ;
    END
  END a[317]
  PIN a[318]
    DIRECTION INPUT ;
    USE SIGNAL ;
    PORT
      LAYER M4 ;
        RECT  0 76.464 0.084 76.488 ;
    END
  END a[318]
  PIN a[319]
    DIRECTION INPUT ;
    USE SIGNAL ;
    PORT
      LAYER M4 ;
        RECT  0 76.608 0.084 76.632 ;
    END
  END a[319]
  PIN a[31]
    DIRECTION INPUT ;
    USE SIGNAL ;
    PORT
      LAYER M4 ;
        RECT  0 29.376 0.084 29.4 ;
    END
  END a[31]
  PIN a[320]
    DIRECTION INPUT ;
    USE SIGNAL ;
    PORT
      LAYER M4 ;
        RECT  0 62.928 0.084 62.952 ;
    END
  END a[320]
  PIN a[321]
    DIRECTION INPUT ;
    USE SIGNAL ;
    PORT
      LAYER M4 ;
        RECT  0 63.072 0.084 63.096 ;
    END
  END a[321]
  PIN a[322]
    DIRECTION INPUT ;
    USE SIGNAL ;
    PORT
      LAYER M4 ;
        RECT  0 63.216 0.084 63.24 ;
    END
  END a[322]
  PIN a[323]
    DIRECTION INPUT ;
    USE SIGNAL ;
    PORT
      LAYER M4 ;
        RECT  0 63.36 0.084 63.384 ;
    END
  END a[323]
  PIN a[324]
    DIRECTION INPUT ;
    USE SIGNAL ;
    PORT
      LAYER M4 ;
        RECT  0 63.504 0.084 63.528 ;
    END
  END a[324]
  PIN a[325]
    DIRECTION INPUT ;
    USE SIGNAL ;
    PORT
      LAYER M4 ;
        RECT  0 63.648 0.084 63.672 ;
    END
  END a[325]
  PIN a[326]
    DIRECTION INPUT ;
    USE SIGNAL ;
    PORT
      LAYER M4 ;
        RECT  0 63.792 0.084 63.816 ;
    END
  END a[326]
  PIN a[327]
    DIRECTION INPUT ;
    USE SIGNAL ;
    PORT
      LAYER M4 ;
        RECT  0 63.936 0.084 63.96 ;
    END
  END a[327]
  PIN a[328]
    DIRECTION INPUT ;
    USE SIGNAL ;
    PORT
      LAYER M4 ;
        RECT  0 64.08 0.084 64.104 ;
    END
  END a[328]
  PIN a[329]
    DIRECTION INPUT ;
    USE SIGNAL ;
    PORT
      LAYER M4 ;
        RECT  0 64.224 0.084 64.248 ;
    END
  END a[329]
  PIN a[32]
    DIRECTION INPUT ;
    USE SIGNAL ;
    PORT
      LAYER M4 ;
        RECT  0 34.128 0.084 34.152 ;
    END
  END a[32]
  PIN a[330]
    DIRECTION INPUT ;
    USE SIGNAL ;
    PORT
      LAYER M4 ;
        RECT  0 64.368 0.084 64.392 ;
    END
  END a[330]
  PIN a[331]
    DIRECTION INPUT ;
    USE SIGNAL ;
    PORT
      LAYER M4 ;
        RECT  0 64.512 0.084 64.536 ;
    END
  END a[331]
  PIN a[332]
    DIRECTION INPUT ;
    USE SIGNAL ;
    PORT
      LAYER M4 ;
        RECT  0 64.656 0.084 64.68 ;
    END
  END a[332]
  PIN a[333]
    DIRECTION INPUT ;
    USE SIGNAL ;
    PORT
      LAYER M4 ;
        RECT  0 64.8 0.084 64.824 ;
    END
  END a[333]
  PIN a[334]
    DIRECTION INPUT ;
    USE SIGNAL ;
    PORT
      LAYER M4 ;
        RECT  0 64.944 0.084 64.968 ;
    END
  END a[334]
  PIN a[335]
    DIRECTION INPUT ;
    USE SIGNAL ;
    PORT
      LAYER M4 ;
        RECT  0 65.088 0.084 65.112 ;
    END
  END a[335]
  PIN a[336]
    DIRECTION INPUT ;
    USE SIGNAL ;
    PORT
      LAYER M4 ;
        RECT  0 65.232 0.084 65.256 ;
    END
  END a[336]
  PIN a[337]
    DIRECTION INPUT ;
    USE SIGNAL ;
    PORT
      LAYER M4 ;
        RECT  0 65.376 0.084 65.4 ;
    END
  END a[337]
  PIN a[338]
    DIRECTION INPUT ;
    USE SIGNAL ;
    PORT
      LAYER M4 ;
        RECT  0 65.52 0.084 65.544 ;
    END
  END a[338]
  PIN a[339]
    DIRECTION INPUT ;
    USE SIGNAL ;
    PORT
      LAYER M4 ;
        RECT  0 65.664 0.084 65.688 ;
    END
  END a[339]
  PIN a[33]
    DIRECTION INPUT ;
    USE SIGNAL ;
    PORT
      LAYER M4 ;
        RECT  0 34.272 0.084 34.296 ;
    END
  END a[33]
  PIN a[340]
    DIRECTION INPUT ;
    USE SIGNAL ;
    PORT
      LAYER M4 ;
        RECT  0 65.808 0.084 65.832 ;
    END
  END a[340]
  PIN a[341]
    DIRECTION INPUT ;
    USE SIGNAL ;
    PORT
      LAYER M4 ;
        RECT  0 65.952 0.084 65.976 ;
    END
  END a[341]
  PIN a[342]
    DIRECTION INPUT ;
    USE SIGNAL ;
    PORT
      LAYER M4 ;
        RECT  0 66.096 0.084 66.12 ;
    END
  END a[342]
  PIN a[343]
    DIRECTION INPUT ;
    USE SIGNAL ;
    PORT
      LAYER M4 ;
        RECT  0 66.24 0.084 66.264 ;
    END
  END a[343]
  PIN a[344]
    DIRECTION INPUT ;
    USE SIGNAL ;
    PORT
      LAYER M4 ;
        RECT  0 66.384 0.084 66.408 ;
    END
  END a[344]
  PIN a[345]
    DIRECTION INPUT ;
    USE SIGNAL ;
    PORT
      LAYER M4 ;
        RECT  0 66.528 0.084 66.552 ;
    END
  END a[345]
  PIN a[346]
    DIRECTION INPUT ;
    USE SIGNAL ;
    PORT
      LAYER M4 ;
        RECT  0 66.672 0.084 66.696 ;
    END
  END a[346]
  PIN a[347]
    DIRECTION INPUT ;
    USE SIGNAL ;
    PORT
      LAYER M4 ;
        RECT  0 66.816 0.084 66.84 ;
    END
  END a[347]
  PIN a[348]
    DIRECTION INPUT ;
    USE SIGNAL ;
    PORT
      LAYER M4 ;
        RECT  0 66.96 0.084 66.984 ;
    END
  END a[348]
  PIN a[349]
    DIRECTION INPUT ;
    USE SIGNAL ;
    PORT
      LAYER M4 ;
        RECT  0 67.104 0.084 67.128 ;
    END
  END a[349]
  PIN a[34]
    DIRECTION INPUT ;
    USE SIGNAL ;
    PORT
      LAYER M4 ;
        RECT  0 34.416 0.084 34.44 ;
    END
  END a[34]
  PIN a[350]
    DIRECTION INPUT ;
    USE SIGNAL ;
    PORT
      LAYER M4 ;
        RECT  0 67.248 0.084 67.272 ;
    END
  END a[350]
  PIN a[351]
    DIRECTION INPUT ;
    USE SIGNAL ;
    PORT
      LAYER M4 ;
        RECT  0 67.392 0.084 67.416 ;
    END
  END a[351]
  PIN a[352]
    DIRECTION INPUT ;
    USE SIGNAL ;
    PORT
      LAYER M4 ;
        RECT  0 67.536 0.084 67.56 ;
    END
  END a[352]
  PIN a[353]
    DIRECTION INPUT ;
    USE SIGNAL ;
    PORT
      LAYER M4 ;
        RECT  0 67.68 0.084 67.704 ;
    END
  END a[353]
  PIN a[354]
    DIRECTION INPUT ;
    USE SIGNAL ;
    PORT
      LAYER M4 ;
        RECT  0 67.824 0.084 67.848 ;
    END
  END a[354]
  PIN a[355]
    DIRECTION INPUT ;
    USE SIGNAL ;
    PORT
      LAYER M4 ;
        RECT  0 67.968 0.084 67.992 ;
    END
  END a[355]
  PIN a[356]
    DIRECTION INPUT ;
    USE SIGNAL ;
    PORT
      LAYER M4 ;
        RECT  0 68.112 0.084 68.136 ;
    END
  END a[356]
  PIN a[357]
    DIRECTION INPUT ;
    USE SIGNAL ;
    PORT
      LAYER M4 ;
        RECT  0 68.256 0.084 68.28 ;
    END
  END a[357]
  PIN a[358]
    DIRECTION INPUT ;
    USE SIGNAL ;
    PORT
      LAYER M4 ;
        RECT  0 68.4 0.084 68.424 ;
    END
  END a[358]
  PIN a[359]
    DIRECTION INPUT ;
    USE SIGNAL ;
    PORT
      LAYER M4 ;
        RECT  0 68.544 0.084 68.568 ;
    END
  END a[359]
  PIN a[35]
    DIRECTION INPUT ;
    USE SIGNAL ;
    PORT
      LAYER M4 ;
        RECT  0 34.56 0.084 34.584 ;
    END
  END a[35]
  PIN a[360]
    DIRECTION INPUT ;
    USE SIGNAL ;
    PORT
      LAYER M4 ;
        RECT  0 68.688 0.084 68.712 ;
    END
  END a[360]
  PIN a[361]
    DIRECTION INPUT ;
    USE SIGNAL ;
    PORT
      LAYER M4 ;
        RECT  0 68.832 0.084 68.856 ;
    END
  END a[361]
  PIN a[362]
    DIRECTION INPUT ;
    USE SIGNAL ;
    PORT
      LAYER M4 ;
        RECT  0 68.976 0.084 69 ;
    END
  END a[362]
  PIN a[363]
    DIRECTION INPUT ;
    USE SIGNAL ;
    PORT
      LAYER M4 ;
        RECT  0 69.12 0.084 69.144 ;
    END
  END a[363]
  PIN a[364]
    DIRECTION INPUT ;
    USE SIGNAL ;
    PORT
      LAYER M4 ;
        RECT  0 69.264 0.084 69.288 ;
    END
  END a[364]
  PIN a[365]
    DIRECTION INPUT ;
    USE SIGNAL ;
    PORT
      LAYER M4 ;
        RECT  0 69.408 0.084 69.432 ;
    END
  END a[365]
  PIN a[366]
    DIRECTION INPUT ;
    USE SIGNAL ;
    PORT
      LAYER M4 ;
        RECT  0 69.552 0.084 69.576 ;
    END
  END a[366]
  PIN a[367]
    DIRECTION INPUT ;
    USE SIGNAL ;
    PORT
      LAYER M4 ;
        RECT  0 69.696 0.084 69.72 ;
    END
  END a[367]
  PIN a[368]
    DIRECTION INPUT ;
    USE SIGNAL ;
    PORT
      LAYER M4 ;
        RECT  0 69.84 0.084 69.864 ;
    END
  END a[368]
  PIN a[369]
    DIRECTION INPUT ;
    USE SIGNAL ;
    PORT
      LAYER M4 ;
        RECT  0 69.984 0.084 70.008 ;
    END
  END a[369]
  PIN a[36]
    DIRECTION INPUT ;
    USE SIGNAL ;
    PORT
      LAYER M4 ;
        RECT  0 34.704 0.084 34.728 ;
    END
  END a[36]
  PIN a[370]
    DIRECTION INPUT ;
    USE SIGNAL ;
    PORT
      LAYER M4 ;
        RECT  0 70.128 0.084 70.152 ;
    END
  END a[370]
  PIN a[371]
    DIRECTION INPUT ;
    USE SIGNAL ;
    PORT
      LAYER M4 ;
        RECT  0 70.272 0.084 70.296 ;
    END
  END a[371]
  PIN a[372]
    DIRECTION INPUT ;
    USE SIGNAL ;
    PORT
      LAYER M4 ;
        RECT  0 70.416 0.084 70.44 ;
    END
  END a[372]
  PIN a[373]
    DIRECTION INPUT ;
    USE SIGNAL ;
    PORT
      LAYER M4 ;
        RECT  0 70.56 0.084 70.584 ;
    END
  END a[373]
  PIN a[374]
    DIRECTION INPUT ;
    USE SIGNAL ;
    PORT
      LAYER M4 ;
        RECT  0 70.704 0.084 70.728 ;
    END
  END a[374]
  PIN a[375]
    DIRECTION INPUT ;
    USE SIGNAL ;
    PORT
      LAYER M4 ;
        RECT  0 70.848 0.084 70.872 ;
    END
  END a[375]
  PIN a[376]
    DIRECTION INPUT ;
    USE SIGNAL ;
    PORT
      LAYER M4 ;
        RECT  0 70.992 0.084 71.016 ;
    END
  END a[376]
  PIN a[377]
    DIRECTION INPUT ;
    USE SIGNAL ;
    PORT
      LAYER M4 ;
        RECT  0 71.136 0.084 71.16 ;
    END
  END a[377]
  PIN a[378]
    DIRECTION INPUT ;
    USE SIGNAL ;
    PORT
      LAYER M4 ;
        RECT  0 71.28 0.084 71.304 ;
    END
  END a[378]
  PIN a[379]
    DIRECTION INPUT ;
    USE SIGNAL ;
    PORT
      LAYER M4 ;
        RECT  0 71.424 0.084 71.448 ;
    END
  END a[379]
  PIN a[37]
    DIRECTION INPUT ;
    USE SIGNAL ;
    PORT
      LAYER M4 ;
        RECT  0 34.848 0.084 34.872 ;
    END
  END a[37]
  PIN a[380]
    DIRECTION INPUT ;
    USE SIGNAL ;
    PORT
      LAYER M4 ;
        RECT  0 71.568 0.084 71.592 ;
    END
  END a[380]
  PIN a[381]
    DIRECTION INPUT ;
    USE SIGNAL ;
    PORT
      LAYER M4 ;
        RECT  0 71.712 0.084 71.736 ;
    END
  END a[381]
  PIN a[382]
    DIRECTION INPUT ;
    USE SIGNAL ;
    PORT
      LAYER M4 ;
        RECT  0 71.856 0.084 71.88 ;
    END
  END a[382]
  PIN a[383]
    DIRECTION INPUT ;
    USE SIGNAL ;
    PORT
      LAYER M4 ;
        RECT  0 72 0.084 72.024 ;
    END
  END a[383]
  PIN a[384]
    DIRECTION INPUT ;
    USE SIGNAL ;
    PORT
      LAYER M4 ;
        RECT  0 5.328 0.084 5.352 ;
    END
  END a[384]
  PIN a[385]
    DIRECTION INPUT ;
    USE SIGNAL ;
    PORT
      LAYER M4 ;
        RECT  0 5.472 0.084 5.496 ;
    END
  END a[385]
  PIN a[386]
    DIRECTION INPUT ;
    USE SIGNAL ;
    PORT
      LAYER M4 ;
        RECT  0 5.616 0.084 5.64 ;
    END
  END a[386]
  PIN a[387]
    DIRECTION INPUT ;
    USE SIGNAL ;
    PORT
      LAYER M4 ;
        RECT  0 5.76 0.084 5.784 ;
    END
  END a[387]
  PIN a[388]
    DIRECTION INPUT ;
    USE SIGNAL ;
    PORT
      LAYER M4 ;
        RECT  0 5.904 0.084 5.928 ;
    END
  END a[388]
  PIN a[389]
    DIRECTION INPUT ;
    USE SIGNAL ;
    PORT
      LAYER M4 ;
        RECT  0 6.048 0.084 6.072 ;
    END
  END a[389]
  PIN a[38]
    DIRECTION INPUT ;
    USE SIGNAL ;
    PORT
      LAYER M4 ;
        RECT  0 34.992 0.084 35.016 ;
    END
  END a[38]
  PIN a[390]
    DIRECTION INPUT ;
    USE SIGNAL ;
    PORT
      LAYER M4 ;
        RECT  0 6.192 0.084 6.216 ;
    END
  END a[390]
  PIN a[391]
    DIRECTION INPUT ;
    USE SIGNAL ;
    PORT
      LAYER M4 ;
        RECT  0 6.336 0.084 6.36 ;
    END
  END a[391]
  PIN a[392]
    DIRECTION INPUT ;
    USE SIGNAL ;
    PORT
      LAYER M4 ;
        RECT  0 6.48 0.084 6.504 ;
    END
  END a[392]
  PIN a[393]
    DIRECTION INPUT ;
    USE SIGNAL ;
    PORT
      LAYER M4 ;
        RECT  0 6.624 0.084 6.648 ;
    END
  END a[393]
  PIN a[394]
    DIRECTION INPUT ;
    USE SIGNAL ;
    PORT
      LAYER M4 ;
        RECT  0 6.768 0.084 6.792 ;
    END
  END a[394]
  PIN a[395]
    DIRECTION INPUT ;
    USE SIGNAL ;
    PORT
      LAYER M4 ;
        RECT  0 6.912 0.084 6.936 ;
    END
  END a[395]
  PIN a[396]
    DIRECTION INPUT ;
    USE SIGNAL ;
    PORT
      LAYER M4 ;
        RECT  0 7.056 0.084 7.08 ;
    END
  END a[396]
  PIN a[397]
    DIRECTION INPUT ;
    USE SIGNAL ;
    PORT
      LAYER M4 ;
        RECT  0 7.2 0.084 7.224 ;
    END
  END a[397]
  PIN a[398]
    DIRECTION INPUT ;
    USE SIGNAL ;
    PORT
      LAYER M4 ;
        RECT  0 7.344 0.084 7.368 ;
    END
  END a[398]
  PIN a[399]
    DIRECTION INPUT ;
    USE SIGNAL ;
    PORT
      LAYER M4 ;
        RECT  0 7.488 0.084 7.512 ;
    END
  END a[399]
  PIN a[39]
    DIRECTION INPUT ;
    USE SIGNAL ;
    PORT
      LAYER M4 ;
        RECT  0 35.136 0.084 35.16 ;
    END
  END a[39]
  PIN a[3]
    DIRECTION INPUT ;
    USE SIGNAL ;
    PORT
      LAYER M4 ;
        RECT  0 25.344 0.084 25.368 ;
    END
  END a[3]
  PIN a[400]
    DIRECTION INPUT ;
    USE SIGNAL ;
    PORT
      LAYER M4 ;
        RECT  0 7.632 0.084 7.656 ;
    END
  END a[400]
  PIN a[401]
    DIRECTION INPUT ;
    USE SIGNAL ;
    PORT
      LAYER M4 ;
        RECT  0 7.776 0.084 7.8 ;
    END
  END a[401]
  PIN a[402]
    DIRECTION INPUT ;
    USE SIGNAL ;
    PORT
      LAYER M4 ;
        RECT  0 7.92 0.084 7.944 ;
    END
  END a[402]
  PIN a[403]
    DIRECTION INPUT ;
    USE SIGNAL ;
    PORT
      LAYER M4 ;
        RECT  0 8.064 0.084 8.088 ;
    END
  END a[403]
  PIN a[404]
    DIRECTION INPUT ;
    USE SIGNAL ;
    PORT
      LAYER M4 ;
        RECT  0 8.208 0.084 8.232 ;
    END
  END a[404]
  PIN a[405]
    DIRECTION INPUT ;
    USE SIGNAL ;
    PORT
      LAYER M4 ;
        RECT  0 8.352 0.084 8.376 ;
    END
  END a[405]
  PIN a[406]
    DIRECTION INPUT ;
    USE SIGNAL ;
    PORT
      LAYER M4 ;
        RECT  0 8.496 0.084 8.52 ;
    END
  END a[406]
  PIN a[407]
    DIRECTION INPUT ;
    USE SIGNAL ;
    PORT
      LAYER M4 ;
        RECT  0 8.64 0.084 8.664 ;
    END
  END a[407]
  PIN a[408]
    DIRECTION INPUT ;
    USE SIGNAL ;
    PORT
      LAYER M4 ;
        RECT  0 8.784 0.084 8.808 ;
    END
  END a[408]
  PIN a[409]
    DIRECTION INPUT ;
    USE SIGNAL ;
    PORT
      LAYER M4 ;
        RECT  0 8.928 0.084 8.952 ;
    END
  END a[409]
  PIN a[40]
    DIRECTION INPUT ;
    USE SIGNAL ;
    PORT
      LAYER M4 ;
        RECT  0 35.28 0.084 35.304 ;
    END
  END a[40]
  PIN a[410]
    DIRECTION INPUT ;
    USE SIGNAL ;
    PORT
      LAYER M4 ;
        RECT  0 9.072 0.084 9.096 ;
    END
  END a[410]
  PIN a[411]
    DIRECTION INPUT ;
    USE SIGNAL ;
    PORT
      LAYER M4 ;
        RECT  0 9.216 0.084 9.24 ;
    END
  END a[411]
  PIN a[412]
    DIRECTION INPUT ;
    USE SIGNAL ;
    PORT
      LAYER M4 ;
        RECT  0 9.36 0.084 9.384 ;
    END
  END a[412]
  PIN a[413]
    DIRECTION INPUT ;
    USE SIGNAL ;
    PORT
      LAYER M4 ;
        RECT  0 9.504 0.084 9.528 ;
    END
  END a[413]
  PIN a[414]
    DIRECTION INPUT ;
    USE SIGNAL ;
    PORT
      LAYER M4 ;
        RECT  0 9.648 0.084 9.672 ;
    END
  END a[414]
  PIN a[415]
    DIRECTION INPUT ;
    USE SIGNAL ;
    PORT
      LAYER M4 ;
        RECT  0 9.792 0.084 9.816 ;
    END
  END a[415]
  PIN a[416]
    DIRECTION INPUT ;
    USE SIGNAL ;
    PORT
      LAYER M4 ;
        RECT  0 14.544 0.084 14.568 ;
    END
  END a[416]
  PIN a[417]
    DIRECTION INPUT ;
    USE SIGNAL ;
    PORT
      LAYER M4 ;
        RECT  0 14.688 0.084 14.712 ;
    END
  END a[417]
  PIN a[418]
    DIRECTION INPUT ;
    USE SIGNAL ;
    PORT
      LAYER M4 ;
        RECT  0 14.832 0.084 14.856 ;
    END
  END a[418]
  PIN a[419]
    DIRECTION INPUT ;
    USE SIGNAL ;
    PORT
      LAYER M4 ;
        RECT  0 14.976 0.084 15 ;
    END
  END a[419]
  PIN a[41]
    DIRECTION INPUT ;
    USE SIGNAL ;
    PORT
      LAYER M4 ;
        RECT  0 35.424 0.084 35.448 ;
    END
  END a[41]
  PIN a[420]
    DIRECTION INPUT ;
    USE SIGNAL ;
    PORT
      LAYER M4 ;
        RECT  0 15.12 0.084 15.144 ;
    END
  END a[420]
  PIN a[421]
    DIRECTION INPUT ;
    USE SIGNAL ;
    PORT
      LAYER M4 ;
        RECT  0 15.264 0.084 15.288 ;
    END
  END a[421]
  PIN a[422]
    DIRECTION INPUT ;
    USE SIGNAL ;
    PORT
      LAYER M4 ;
        RECT  0 15.408 0.084 15.432 ;
    END
  END a[422]
  PIN a[423]
    DIRECTION INPUT ;
    USE SIGNAL ;
    PORT
      LAYER M4 ;
        RECT  0 15.552 0.084 15.576 ;
    END
  END a[423]
  PIN a[424]
    DIRECTION INPUT ;
    USE SIGNAL ;
    PORT
      LAYER M4 ;
        RECT  0 15.696 0.084 15.72 ;
    END
  END a[424]
  PIN a[425]
    DIRECTION INPUT ;
    USE SIGNAL ;
    PORT
      LAYER M4 ;
        RECT  0 15.84 0.084 15.864 ;
    END
  END a[425]
  PIN a[426]
    DIRECTION INPUT ;
    USE SIGNAL ;
    PORT
      LAYER M4 ;
        RECT  0 15.984 0.084 16.008 ;
    END
  END a[426]
  PIN a[427]
    DIRECTION INPUT ;
    USE SIGNAL ;
    PORT
      LAYER M4 ;
        RECT  0 16.128 0.084 16.152 ;
    END
  END a[427]
  PIN a[428]
    DIRECTION INPUT ;
    USE SIGNAL ;
    PORT
      LAYER M4 ;
        RECT  0 16.272 0.084 16.296 ;
    END
  END a[428]
  PIN a[429]
    DIRECTION INPUT ;
    USE SIGNAL ;
    PORT
      LAYER M4 ;
        RECT  0 16.416 0.084 16.44 ;
    END
  END a[429]
  PIN a[42]
    DIRECTION INPUT ;
    USE SIGNAL ;
    PORT
      LAYER M4 ;
        RECT  0 35.568 0.084 35.592 ;
    END
  END a[42]
  PIN a[430]
    DIRECTION INPUT ;
    USE SIGNAL ;
    PORT
      LAYER M4 ;
        RECT  0 16.56 0.084 16.584 ;
    END
  END a[430]
  PIN a[431]
    DIRECTION INPUT ;
    USE SIGNAL ;
    PORT
      LAYER M4 ;
        RECT  0 16.704 0.084 16.728 ;
    END
  END a[431]
  PIN a[432]
    DIRECTION INPUT ;
    USE SIGNAL ;
    PORT
      LAYER M4 ;
        RECT  0 16.848 0.084 16.872 ;
    END
  END a[432]
  PIN a[433]
    DIRECTION INPUT ;
    USE SIGNAL ;
    PORT
      LAYER M4 ;
        RECT  0 16.992 0.084 17.016 ;
    END
  END a[433]
  PIN a[434]
    DIRECTION INPUT ;
    USE SIGNAL ;
    PORT
      LAYER M4 ;
        RECT  0 17.136 0.084 17.16 ;
    END
  END a[434]
  PIN a[435]
    DIRECTION INPUT ;
    USE SIGNAL ;
    PORT
      LAYER M4 ;
        RECT  0 17.28 0.084 17.304 ;
    END
  END a[435]
  PIN a[436]
    DIRECTION INPUT ;
    USE SIGNAL ;
    PORT
      LAYER M4 ;
        RECT  0 17.424 0.084 17.448 ;
    END
  END a[436]
  PIN a[437]
    DIRECTION INPUT ;
    USE SIGNAL ;
    PORT
      LAYER M4 ;
        RECT  0 17.568 0.084 17.592 ;
    END
  END a[437]
  PIN a[438]
    DIRECTION INPUT ;
    USE SIGNAL ;
    PORT
      LAYER M4 ;
        RECT  0 17.712 0.084 17.736 ;
    END
  END a[438]
  PIN a[439]
    DIRECTION INPUT ;
    USE SIGNAL ;
    PORT
      LAYER M4 ;
        RECT  0 17.856 0.084 17.88 ;
    END
  END a[439]
  PIN a[43]
    DIRECTION INPUT ;
    USE SIGNAL ;
    PORT
      LAYER M4 ;
        RECT  0 35.712 0.084 35.736 ;
    END
  END a[43]
  PIN a[440]
    DIRECTION INPUT ;
    USE SIGNAL ;
    PORT
      LAYER M4 ;
        RECT  0 18 0.084 18.024 ;
    END
  END a[440]
  PIN a[441]
    DIRECTION INPUT ;
    USE SIGNAL ;
    PORT
      LAYER M4 ;
        RECT  0 18.144 0.084 18.168 ;
    END
  END a[441]
  PIN a[442]
    DIRECTION INPUT ;
    USE SIGNAL ;
    PORT
      LAYER M4 ;
        RECT  0 18.288 0.084 18.312 ;
    END
  END a[442]
  PIN a[443]
    DIRECTION INPUT ;
    USE SIGNAL ;
    PORT
      LAYER M4 ;
        RECT  0 18.432 0.084 18.456 ;
    END
  END a[443]
  PIN a[444]
    DIRECTION INPUT ;
    USE SIGNAL ;
    PORT
      LAYER M4 ;
        RECT  0 18.576 0.084 18.6 ;
    END
  END a[444]
  PIN a[445]
    DIRECTION INPUT ;
    USE SIGNAL ;
    PORT
      LAYER M4 ;
        RECT  0 18.72 0.084 18.744 ;
    END
  END a[445]
  PIN a[446]
    DIRECTION INPUT ;
    USE SIGNAL ;
    PORT
      LAYER M4 ;
        RECT  0 18.864 0.084 18.888 ;
    END
  END a[446]
  PIN a[447]
    DIRECTION INPUT ;
    USE SIGNAL ;
    PORT
      LAYER M4 ;
        RECT  0 19.008 0.084 19.032 ;
    END
  END a[447]
  PIN a[448]
    DIRECTION INPUT ;
    USE SIGNAL ;
    PORT
      LAYER M4 ;
        RECT  0 19.152 0.084 19.176 ;
    END
  END a[448]
  PIN a[449]
    DIRECTION INPUT ;
    USE SIGNAL ;
    PORT
      LAYER M4 ;
        RECT  0 19.296 0.084 19.32 ;
    END
  END a[449]
  PIN a[44]
    DIRECTION INPUT ;
    USE SIGNAL ;
    PORT
      LAYER M4 ;
        RECT  0 35.856 0.084 35.88 ;
    END
  END a[44]
  PIN a[450]
    DIRECTION INPUT ;
    USE SIGNAL ;
    PORT
      LAYER M4 ;
        RECT  0 19.44 0.084 19.464 ;
    END
  END a[450]
  PIN a[451]
    DIRECTION INPUT ;
    USE SIGNAL ;
    PORT
      LAYER M4 ;
        RECT  0 19.584 0.084 19.608 ;
    END
  END a[451]
  PIN a[452]
    DIRECTION INPUT ;
    USE SIGNAL ;
    PORT
      LAYER M4 ;
        RECT  0 19.728 0.084 19.752 ;
    END
  END a[452]
  PIN a[453]
    DIRECTION INPUT ;
    USE SIGNAL ;
    PORT
      LAYER M4 ;
        RECT  0 19.872 0.084 19.896 ;
    END
  END a[453]
  PIN a[454]
    DIRECTION INPUT ;
    USE SIGNAL ;
    PORT
      LAYER M4 ;
        RECT  0 20.016 0.084 20.04 ;
    END
  END a[454]
  PIN a[455]
    DIRECTION INPUT ;
    USE SIGNAL ;
    PORT
      LAYER M4 ;
        RECT  0 20.16 0.084 20.184 ;
    END
  END a[455]
  PIN a[456]
    DIRECTION INPUT ;
    USE SIGNAL ;
    PORT
      LAYER M4 ;
        RECT  0 20.304 0.084 20.328 ;
    END
  END a[456]
  PIN a[457]
    DIRECTION INPUT ;
    USE SIGNAL ;
    PORT
      LAYER M4 ;
        RECT  0 20.448 0.084 20.472 ;
    END
  END a[457]
  PIN a[458]
    DIRECTION INPUT ;
    USE SIGNAL ;
    PORT
      LAYER M4 ;
        RECT  0 20.592 0.084 20.616 ;
    END
  END a[458]
  PIN a[459]
    DIRECTION INPUT ;
    USE SIGNAL ;
    PORT
      LAYER M4 ;
        RECT  0 20.736 0.084 20.76 ;
    END
  END a[459]
  PIN a[45]
    DIRECTION INPUT ;
    USE SIGNAL ;
    PORT
      LAYER M4 ;
        RECT  0 36 0.084 36.024 ;
    END
  END a[45]
  PIN a[460]
    DIRECTION INPUT ;
    USE SIGNAL ;
    PORT
      LAYER M4 ;
        RECT  0 20.88 0.084 20.904 ;
    END
  END a[460]
  PIN a[461]
    DIRECTION INPUT ;
    USE SIGNAL ;
    PORT
      LAYER M4 ;
        RECT  0 21.024 0.084 21.048 ;
    END
  END a[461]
  PIN a[462]
    DIRECTION INPUT ;
    USE SIGNAL ;
    PORT
      LAYER M4 ;
        RECT  0 21.168 0.084 21.192 ;
    END
  END a[462]
  PIN a[463]
    DIRECTION INPUT ;
    USE SIGNAL ;
    PORT
      LAYER M4 ;
        RECT  0 21.312 0.084 21.336 ;
    END
  END a[463]
  PIN a[464]
    DIRECTION INPUT ;
    USE SIGNAL ;
    PORT
      LAYER M4 ;
        RECT  0 21.456 0.084 21.48 ;
    END
  END a[464]
  PIN a[465]
    DIRECTION INPUT ;
    USE SIGNAL ;
    PORT
      LAYER M4 ;
        RECT  0 21.6 0.084 21.624 ;
    END
  END a[465]
  PIN a[466]
    DIRECTION INPUT ;
    USE SIGNAL ;
    PORT
      LAYER M4 ;
        RECT  0 21.744 0.084 21.768 ;
    END
  END a[466]
  PIN a[467]
    DIRECTION INPUT ;
    USE SIGNAL ;
    PORT
      LAYER M4 ;
        RECT  0 21.888 0.084 21.912 ;
    END
  END a[467]
  PIN a[468]
    DIRECTION INPUT ;
    USE SIGNAL ;
    PORT
      LAYER M4 ;
        RECT  0 22.032 0.084 22.056 ;
    END
  END a[468]
  PIN a[469]
    DIRECTION INPUT ;
    USE SIGNAL ;
    PORT
      LAYER M4 ;
        RECT  0 22.176 0.084 22.2 ;
    END
  END a[469]
  PIN a[46]
    DIRECTION INPUT ;
    USE SIGNAL ;
    PORT
      LAYER M4 ;
        RECT  0 36.144 0.084 36.168 ;
    END
  END a[46]
  PIN a[470]
    DIRECTION INPUT ;
    USE SIGNAL ;
    PORT
      LAYER M4 ;
        RECT  0 22.32 0.084 22.344 ;
    END
  END a[470]
  PIN a[471]
    DIRECTION INPUT ;
    USE SIGNAL ;
    PORT
      LAYER M4 ;
        RECT  0 22.464 0.084 22.488 ;
    END
  END a[471]
  PIN a[472]
    DIRECTION INPUT ;
    USE SIGNAL ;
    PORT
      LAYER M4 ;
        RECT  0 22.608 0.084 22.632 ;
    END
  END a[472]
  PIN a[473]
    DIRECTION INPUT ;
    USE SIGNAL ;
    PORT
      LAYER M4 ;
        RECT  0 22.752 0.084 22.776 ;
    END
  END a[473]
  PIN a[474]
    DIRECTION INPUT ;
    USE SIGNAL ;
    PORT
      LAYER M4 ;
        RECT  0 22.896 0.084 22.92 ;
    END
  END a[474]
  PIN a[475]
    DIRECTION INPUT ;
    USE SIGNAL ;
    PORT
      LAYER M4 ;
        RECT  0 23.04 0.084 23.064 ;
    END
  END a[475]
  PIN a[476]
    DIRECTION INPUT ;
    USE SIGNAL ;
    PORT
      LAYER M4 ;
        RECT  0 23.184 0.084 23.208 ;
    END
  END a[476]
  PIN a[477]
    DIRECTION INPUT ;
    USE SIGNAL ;
    PORT
      LAYER M4 ;
        RECT  0 23.328 0.084 23.352 ;
    END
  END a[477]
  PIN a[478]
    DIRECTION INPUT ;
    USE SIGNAL ;
    PORT
      LAYER M4 ;
        RECT  0 23.472 0.084 23.496 ;
    END
  END a[478]
  PIN a[479]
    DIRECTION INPUT ;
    USE SIGNAL ;
    PORT
      LAYER M4 ;
        RECT  0 23.616 0.084 23.64 ;
    END
  END a[479]
  PIN a[47]
    DIRECTION INPUT ;
    USE SIGNAL ;
    PORT
      LAYER M4 ;
        RECT  0 36.288 0.084 36.312 ;
    END
  END a[47]
  PIN a[480]
    DIRECTION INPUT ;
    USE SIGNAL ;
    PORT
      LAYER M4 ;
        RECT  0 9.936 0.084 9.96 ;
    END
  END a[480]
  PIN a[481]
    DIRECTION INPUT ;
    USE SIGNAL ;
    PORT
      LAYER M4 ;
        RECT  0 10.08 0.084 10.104 ;
    END
  END a[481]
  PIN a[482]
    DIRECTION INPUT ;
    USE SIGNAL ;
    PORT
      LAYER M4 ;
        RECT  0 10.224 0.084 10.248 ;
    END
  END a[482]
  PIN a[483]
    DIRECTION INPUT ;
    USE SIGNAL ;
    PORT
      LAYER M4 ;
        RECT  0 10.368 0.084 10.392 ;
    END
  END a[483]
  PIN a[484]
    DIRECTION INPUT ;
    USE SIGNAL ;
    PORT
      LAYER M4 ;
        RECT  0 10.512 0.084 10.536 ;
    END
  END a[484]
  PIN a[485]
    DIRECTION INPUT ;
    USE SIGNAL ;
    PORT
      LAYER M4 ;
        RECT  0 10.656 0.084 10.68 ;
    END
  END a[485]
  PIN a[486]
    DIRECTION INPUT ;
    USE SIGNAL ;
    PORT
      LAYER M4 ;
        RECT  0 10.8 0.084 10.824 ;
    END
  END a[486]
  PIN a[487]
    DIRECTION INPUT ;
    USE SIGNAL ;
    PORT
      LAYER M4 ;
        RECT  0 10.944 0.084 10.968 ;
    END
  END a[487]
  PIN a[488]
    DIRECTION INPUT ;
    USE SIGNAL ;
    PORT
      LAYER M4 ;
        RECT  0 11.088 0.084 11.112 ;
    END
  END a[488]
  PIN a[489]
    DIRECTION INPUT ;
    USE SIGNAL ;
    PORT
      LAYER M4 ;
        RECT  0 11.232 0.084 11.256 ;
    END
  END a[489]
  PIN a[48]
    DIRECTION INPUT ;
    USE SIGNAL ;
    PORT
      LAYER M4 ;
        RECT  0 36.432 0.084 36.456 ;
    END
  END a[48]
  PIN a[490]
    DIRECTION INPUT ;
    USE SIGNAL ;
    PORT
      LAYER M4 ;
        RECT  0 11.376 0.084 11.4 ;
    END
  END a[490]
  PIN a[491]
    DIRECTION INPUT ;
    USE SIGNAL ;
    PORT
      LAYER M4 ;
        RECT  0 11.52 0.084 11.544 ;
    END
  END a[491]
  PIN a[492]
    DIRECTION INPUT ;
    USE SIGNAL ;
    PORT
      LAYER M4 ;
        RECT  0 11.664 0.084 11.688 ;
    END
  END a[492]
  PIN a[493]
    DIRECTION INPUT ;
    USE SIGNAL ;
    PORT
      LAYER M4 ;
        RECT  0 11.808 0.084 11.832 ;
    END
  END a[493]
  PIN a[494]
    DIRECTION INPUT ;
    USE SIGNAL ;
    PORT
      LAYER M4 ;
        RECT  0 11.952 0.084 11.976 ;
    END
  END a[494]
  PIN a[495]
    DIRECTION INPUT ;
    USE SIGNAL ;
    PORT
      LAYER M4 ;
        RECT  0 12.096 0.084 12.12 ;
    END
  END a[495]
  PIN a[496]
    DIRECTION INPUT ;
    USE SIGNAL ;
    PORT
      LAYER M4 ;
        RECT  0 12.24 0.084 12.264 ;
    END
  END a[496]
  PIN a[497]
    DIRECTION INPUT ;
    USE SIGNAL ;
    PORT
      LAYER M4 ;
        RECT  0 12.384 0.084 12.408 ;
    END
  END a[497]
  PIN a[498]
    DIRECTION INPUT ;
    USE SIGNAL ;
    PORT
      LAYER M4 ;
        RECT  0 12.528 0.084 12.552 ;
    END
  END a[498]
  PIN a[499]
    DIRECTION INPUT ;
    USE SIGNAL ;
    PORT
      LAYER M4 ;
        RECT  0 12.672 0.084 12.696 ;
    END
  END a[499]
  PIN a[49]
    DIRECTION INPUT ;
    USE SIGNAL ;
    PORT
      LAYER M4 ;
        RECT  0 36.576 0.084 36.6 ;
    END
  END a[49]
  PIN a[4]
    DIRECTION INPUT ;
    USE SIGNAL ;
    PORT
      LAYER M4 ;
        RECT  0 25.488 0.084 25.512 ;
    END
  END a[4]
  PIN a[500]
    DIRECTION INPUT ;
    USE SIGNAL ;
    PORT
      LAYER M4 ;
        RECT  0 12.816 0.084 12.84 ;
    END
  END a[500]
  PIN a[501]
    DIRECTION INPUT ;
    USE SIGNAL ;
    PORT
      LAYER M4 ;
        RECT  0 12.96 0.084 12.984 ;
    END
  END a[501]
  PIN a[502]
    DIRECTION INPUT ;
    USE SIGNAL ;
    PORT
      LAYER M4 ;
        RECT  0 13.104 0.084 13.128 ;
    END
  END a[502]
  PIN a[503]
    DIRECTION INPUT ;
    USE SIGNAL ;
    PORT
      LAYER M4 ;
        RECT  0 13.248 0.084 13.272 ;
    END
  END a[503]
  PIN a[504]
    DIRECTION INPUT ;
    USE SIGNAL ;
    PORT
      LAYER M4 ;
        RECT  0 13.392 0.084 13.416 ;
    END
  END a[504]
  PIN a[505]
    DIRECTION INPUT ;
    USE SIGNAL ;
    PORT
      LAYER M4 ;
        RECT  0 13.536 0.084 13.56 ;
    END
  END a[505]
  PIN a[506]
    DIRECTION INPUT ;
    USE SIGNAL ;
    PORT
      LAYER M4 ;
        RECT  0 13.68 0.084 13.704 ;
    END
  END a[506]
  PIN a[507]
    DIRECTION INPUT ;
    USE SIGNAL ;
    PORT
      LAYER M4 ;
        RECT  0 13.824 0.084 13.848 ;
    END
  END a[507]
  PIN a[508]
    DIRECTION INPUT ;
    USE SIGNAL ;
    PORT
      LAYER M4 ;
        RECT  0 13.968 0.084 13.992 ;
    END
  END a[508]
  PIN a[509]
    DIRECTION INPUT ;
    USE SIGNAL ;
    PORT
      LAYER M4 ;
        RECT  0 14.112 0.084 14.136 ;
    END
  END a[509]
  PIN a[50]
    DIRECTION INPUT ;
    USE SIGNAL ;
    PORT
      LAYER M4 ;
        RECT  0 36.72 0.084 36.744 ;
    END
  END a[50]
  PIN a[510]
    DIRECTION INPUT ;
    USE SIGNAL ;
    PORT
      LAYER M4 ;
        RECT  0 14.256 0.084 14.28 ;
    END
  END a[510]
  PIN a[511]
    DIRECTION INPUT ;
    USE SIGNAL ;
    PORT
      LAYER M4 ;
        RECT  0 14.4 0.084 14.424 ;
    END
  END a[511]
  PIN a[512]
    DIRECTION INPUT ;
    USE SIGNAL ;
    PORT
      LAYER M4 ;
        RECT  0 3.024 0.084 3.048 ;
    END
  END a[512]
  PIN a[513]
    DIRECTION INPUT ;
    USE SIGNAL ;
    PORT
      LAYER M4 ;
        RECT  0 3.168 0.084 3.192 ;
    END
  END a[513]
  PIN a[514]
    DIRECTION INPUT ;
    USE SIGNAL ;
    PORT
      LAYER M4 ;
        RECT  0 3.312 0.084 3.336 ;
    END
  END a[514]
  PIN a[515]
    DIRECTION INPUT ;
    USE SIGNAL ;
    PORT
      LAYER M4 ;
        RECT  0 3.456 0.084 3.48 ;
    END
  END a[515]
  PIN a[516]
    DIRECTION INPUT ;
    USE SIGNAL ;
    PORT
      LAYER M4 ;
        RECT  0 3.6 0.084 3.624 ;
    END
  END a[516]
  PIN a[517]
    DIRECTION INPUT ;
    USE SIGNAL ;
    PORT
      LAYER M4 ;
        RECT  0 3.744 0.084 3.768 ;
    END
  END a[517]
  PIN a[518]
    DIRECTION INPUT ;
    USE SIGNAL ;
    PORT
      LAYER M4 ;
        RECT  0 3.888 0.084 3.912 ;
    END
  END a[518]
  PIN a[519]
    DIRECTION INPUT ;
    USE SIGNAL ;
    PORT
      LAYER M4 ;
        RECT  0 4.032 0.084 4.056 ;
    END
  END a[519]
  PIN a[51]
    DIRECTION INPUT ;
    USE SIGNAL ;
    PORT
      LAYER M4 ;
        RECT  0 36.864 0.084 36.888 ;
    END
  END a[51]
  PIN a[520]
    DIRECTION INPUT ;
    USE SIGNAL ;
    PORT
      LAYER M4 ;
        RECT  0 4.176 0.084 4.2 ;
    END
  END a[520]
  PIN a[521]
    DIRECTION INPUT ;
    USE SIGNAL ;
    PORT
      LAYER M4 ;
        RECT  0 4.32 0.084 4.344 ;
    END
  END a[521]
  PIN a[522]
    DIRECTION INPUT ;
    USE SIGNAL ;
    PORT
      LAYER M4 ;
        RECT  0 4.464 0.084 4.488 ;
    END
  END a[522]
  PIN a[523]
    DIRECTION INPUT ;
    USE SIGNAL ;
    PORT
      LAYER M4 ;
        RECT  0 4.608 0.084 4.632 ;
    END
  END a[523]
  PIN a[524]
    DIRECTION INPUT ;
    USE SIGNAL ;
    PORT
      LAYER M4 ;
        RECT  0 4.752 0.084 4.776 ;
    END
  END a[524]
  PIN a[525]
    DIRECTION INPUT ;
    USE SIGNAL ;
    PORT
      LAYER M4 ;
        RECT  0 4.896 0.084 4.92 ;
    END
  END a[525]
  PIN a[526]
    DIRECTION INPUT ;
    USE SIGNAL ;
    PORT
      LAYER M4 ;
        RECT  0 5.04 0.084 5.064 ;
    END
  END a[526]
  PIN a[527]
    DIRECTION INPUT ;
    USE SIGNAL ;
    PORT
      LAYER M4 ;
        RECT  0 5.184 0.084 5.208 ;
    END
  END a[527]
  PIN a[52]
    DIRECTION INPUT ;
    USE SIGNAL ;
    PORT
      LAYER M4 ;
        RECT  0 37.008 0.084 37.032 ;
    END
  END a[52]
  PIN a[53]
    DIRECTION INPUT ;
    USE SIGNAL ;
    PORT
      LAYER M4 ;
        RECT  0 37.152 0.084 37.176 ;
    END
  END a[53]
  PIN a[54]
    DIRECTION INPUT ;
    USE SIGNAL ;
    PORT
      LAYER M4 ;
        RECT  0 37.296 0.084 37.32 ;
    END
  END a[54]
  PIN a[55]
    DIRECTION INPUT ;
    USE SIGNAL ;
    PORT
      LAYER M4 ;
        RECT  0 37.44 0.084 37.464 ;
    END
  END a[55]
  PIN a[56]
    DIRECTION INPUT ;
    USE SIGNAL ;
    PORT
      LAYER M4 ;
        RECT  0 37.584 0.084 37.608 ;
    END
  END a[56]
  PIN a[57]
    DIRECTION INPUT ;
    USE SIGNAL ;
    PORT
      LAYER M4 ;
        RECT  0 37.728 0.084 37.752 ;
    END
  END a[57]
  PIN a[58]
    DIRECTION INPUT ;
    USE SIGNAL ;
    PORT
      LAYER M4 ;
        RECT  0 37.872 0.084 37.896 ;
    END
  END a[58]
  PIN a[59]
    DIRECTION INPUT ;
    USE SIGNAL ;
    PORT
      LAYER M4 ;
        RECT  0 38.016 0.084 38.04 ;
    END
  END a[59]
  PIN a[5]
    DIRECTION INPUT ;
    USE SIGNAL ;
    PORT
      LAYER M4 ;
        RECT  0 25.632 0.084 25.656 ;
    END
  END a[5]
  PIN a[60]
    DIRECTION INPUT ;
    USE SIGNAL ;
    PORT
      LAYER M4 ;
        RECT  0 38.16 0.084 38.184 ;
    END
  END a[60]
  PIN a[61]
    DIRECTION INPUT ;
    USE SIGNAL ;
    PORT
      LAYER M4 ;
        RECT  0 38.304 0.084 38.328 ;
    END
  END a[61]
  PIN a[62]
    DIRECTION INPUT ;
    USE SIGNAL ;
    PORT
      LAYER M4 ;
        RECT  0 38.448 0.084 38.472 ;
    END
  END a[62]
  PIN a[63]
    DIRECTION INPUT ;
    USE SIGNAL ;
    PORT
      LAYER M4 ;
        RECT  0 38.592 0.084 38.616 ;
    END
  END a[63]
  PIN a[64]
    DIRECTION INPUT ;
    USE SIGNAL ;
    PORT
      LAYER M4 ;
        RECT  0 47.952 0.084 47.976 ;
    END
  END a[64]
  PIN a[65]
    DIRECTION INPUT ;
    USE SIGNAL ;
    PORT
      LAYER M4 ;
        RECT  0 48.096 0.084 48.12 ;
    END
  END a[65]
  PIN a[66]
    DIRECTION INPUT ;
    USE SIGNAL ;
    PORT
      LAYER M4 ;
        RECT  0 48.24 0.084 48.264 ;
    END
  END a[66]
  PIN a[67]
    DIRECTION INPUT ;
    USE SIGNAL ;
    PORT
      LAYER M4 ;
        RECT  0 48.384 0.084 48.408 ;
    END
  END a[67]
  PIN a[68]
    DIRECTION INPUT ;
    USE SIGNAL ;
    PORT
      LAYER M4 ;
        RECT  0 48.528 0.084 48.552 ;
    END
  END a[68]
  PIN a[69]
    DIRECTION INPUT ;
    USE SIGNAL ;
    PORT
      LAYER M4 ;
        RECT  0 48.672 0.084 48.696 ;
    END
  END a[69]
  PIN a[6]
    DIRECTION INPUT ;
    USE SIGNAL ;
    PORT
      LAYER M4 ;
        RECT  0 25.776 0.084 25.8 ;
    END
  END a[6]
  PIN a[70]
    DIRECTION INPUT ;
    USE SIGNAL ;
    PORT
      LAYER M4 ;
        RECT  0 48.816 0.084 48.84 ;
    END
  END a[70]
  PIN a[71]
    DIRECTION INPUT ;
    USE SIGNAL ;
    PORT
      LAYER M4 ;
        RECT  0 48.96 0.084 48.984 ;
    END
  END a[71]
  PIN a[72]
    DIRECTION INPUT ;
    USE SIGNAL ;
    PORT
      LAYER M4 ;
        RECT  0 49.104 0.084 49.128 ;
    END
  END a[72]
  PIN a[73]
    DIRECTION INPUT ;
    USE SIGNAL ;
    PORT
      LAYER M4 ;
        RECT  0 49.248 0.084 49.272 ;
    END
  END a[73]
  PIN a[74]
    DIRECTION INPUT ;
    USE SIGNAL ;
    PORT
      LAYER M4 ;
        RECT  0 49.392 0.084 49.416 ;
    END
  END a[74]
  PIN a[75]
    DIRECTION INPUT ;
    USE SIGNAL ;
    PORT
      LAYER M4 ;
        RECT  0 49.536 0.084 49.56 ;
    END
  END a[75]
  PIN a[76]
    DIRECTION INPUT ;
    USE SIGNAL ;
    PORT
      LAYER M4 ;
        RECT  0 49.68 0.084 49.704 ;
    END
  END a[76]
  PIN a[77]
    DIRECTION INPUT ;
    USE SIGNAL ;
    PORT
      LAYER M4 ;
        RECT  0 49.824 0.084 49.848 ;
    END
  END a[77]
  PIN a[78]
    DIRECTION INPUT ;
    USE SIGNAL ;
    PORT
      LAYER M4 ;
        RECT  0 49.968 0.084 49.992 ;
    END
  END a[78]
  PIN a[79]
    DIRECTION INPUT ;
    USE SIGNAL ;
    PORT
      LAYER M4 ;
        RECT  0 50.112 0.084 50.136 ;
    END
  END a[79]
  PIN a[7]
    DIRECTION INPUT ;
    USE SIGNAL ;
    PORT
      LAYER M4 ;
        RECT  0 25.92 0.084 25.944 ;
    END
  END a[7]
  PIN a[80]
    DIRECTION INPUT ;
    USE SIGNAL ;
    PORT
      LAYER M4 ;
        RECT  0 50.256 0.084 50.28 ;
    END
  END a[80]
  PIN a[81]
    DIRECTION INPUT ;
    USE SIGNAL ;
    PORT
      LAYER M4 ;
        RECT  0 50.4 0.084 50.424 ;
    END
  END a[81]
  PIN a[82]
    DIRECTION INPUT ;
    USE SIGNAL ;
    PORT
      LAYER M4 ;
        RECT  0 50.544 0.084 50.568 ;
    END
  END a[82]
  PIN a[83]
    DIRECTION INPUT ;
    USE SIGNAL ;
    PORT
      LAYER M4 ;
        RECT  0 50.688 0.084 50.712 ;
    END
  END a[83]
  PIN a[84]
    DIRECTION INPUT ;
    USE SIGNAL ;
    PORT
      LAYER M4 ;
        RECT  0 50.832 0.084 50.856 ;
    END
  END a[84]
  PIN a[85]
    DIRECTION INPUT ;
    USE SIGNAL ;
    PORT
      LAYER M4 ;
        RECT  0 50.976 0.084 51 ;
    END
  END a[85]
  PIN a[86]
    DIRECTION INPUT ;
    USE SIGNAL ;
    PORT
      LAYER M4 ;
        RECT  0 51.12 0.084 51.144 ;
    END
  END a[86]
  PIN a[87]
    DIRECTION INPUT ;
    USE SIGNAL ;
    PORT
      LAYER M4 ;
        RECT  0 51.264 0.084 51.288 ;
    END
  END a[87]
  PIN a[88]
    DIRECTION INPUT ;
    USE SIGNAL ;
    PORT
      LAYER M4 ;
        RECT  0 51.408 0.084 51.432 ;
    END
  END a[88]
  PIN a[89]
    DIRECTION INPUT ;
    USE SIGNAL ;
    PORT
      LAYER M4 ;
        RECT  0 51.552 0.084 51.576 ;
    END
  END a[89]
  PIN a[8]
    DIRECTION INPUT ;
    USE SIGNAL ;
    PORT
      LAYER M4 ;
        RECT  0 26.064 0.084 26.088 ;
    END
  END a[8]
  PIN a[90]
    DIRECTION INPUT ;
    USE SIGNAL ;
    PORT
      LAYER M4 ;
        RECT  0 51.696 0.084 51.72 ;
    END
  END a[90]
  PIN a[91]
    DIRECTION INPUT ;
    USE SIGNAL ;
    PORT
      LAYER M4 ;
        RECT  0 51.84 0.084 51.864 ;
    END
  END a[91]
  PIN a[92]
    DIRECTION INPUT ;
    USE SIGNAL ;
    PORT
      LAYER M4 ;
        RECT  0 51.984 0.084 52.008 ;
    END
  END a[92]
  PIN a[93]
    DIRECTION INPUT ;
    USE SIGNAL ;
    PORT
      LAYER M4 ;
        RECT  0 52.128 0.084 52.152 ;
    END
  END a[93]
  PIN a[94]
    DIRECTION INPUT ;
    USE SIGNAL ;
    PORT
      LAYER M4 ;
        RECT  0 52.272 0.084 52.296 ;
    END
  END a[94]
  PIN a[95]
    DIRECTION INPUT ;
    USE SIGNAL ;
    PORT
      LAYER M4 ;
        RECT  0 52.416 0.084 52.44 ;
    END
  END a[95]
  PIN a[96]
    DIRECTION INPUT ;
    USE SIGNAL ;
    PORT
      LAYER M4 ;
        RECT  0 29.52 0.084 29.544 ;
    END
  END a[96]
  PIN a[97]
    DIRECTION INPUT ;
    USE SIGNAL ;
    PORT
      LAYER M4 ;
        RECT  0 29.664 0.084 29.688 ;
    END
  END a[97]
  PIN a[98]
    DIRECTION INPUT ;
    USE SIGNAL ;
    PORT
      LAYER M4 ;
        RECT  0 29.808 0.084 29.832 ;
    END
  END a[98]
  PIN a[99]
    DIRECTION INPUT ;
    USE SIGNAL ;
    PORT
      LAYER M4 ;
        RECT  0 29.952 0.084 29.976 ;
    END
  END a[99]
  PIN a[9]
    DIRECTION INPUT ;
    USE SIGNAL ;
    PORT
      LAYER M4 ;
        RECT  0 26.208 0.084 26.232 ;
    END
  END a[9]
  PIN b[0]
    DIRECTION OUTPUT ;
    USE SIGNAL ;
    PORT
      LAYER M4 ;
        RECT  21.516 29.52 21.6 29.544 ;
    END
  END b[0]
  PIN b[100]
    DIRECTION OUTPUT ;
    USE SIGNAL ;
    PORT
      LAYER M4 ;
        RECT  21.516 34.704 21.6 34.728 ;
    END
  END b[100]
  PIN b[101]
    DIRECTION OUTPUT ;
    USE SIGNAL ;
    PORT
      LAYER M4 ;
        RECT  21.516 34.848 21.6 34.872 ;
    END
  END b[101]
  PIN b[102]
    DIRECTION OUTPUT ;
    USE SIGNAL ;
    PORT
      LAYER M4 ;
        RECT  21.516 34.992 21.6 35.016 ;
    END
  END b[102]
  PIN b[103]
    DIRECTION OUTPUT ;
    USE SIGNAL ;
    PORT
      LAYER M4 ;
        RECT  21.516 35.136 21.6 35.16 ;
    END
  END b[103]
  PIN b[104]
    DIRECTION OUTPUT ;
    USE SIGNAL ;
    PORT
      LAYER M4 ;
        RECT  21.516 35.28 21.6 35.304 ;
    END
  END b[104]
  PIN b[105]
    DIRECTION OUTPUT ;
    USE SIGNAL ;
    PORT
      LAYER M4 ;
        RECT  21.516 35.424 21.6 35.448 ;
    END
  END b[105]
  PIN b[106]
    DIRECTION OUTPUT ;
    USE SIGNAL ;
    PORT
      LAYER M4 ;
        RECT  21.516 35.568 21.6 35.592 ;
    END
  END b[106]
  PIN b[107]
    DIRECTION OUTPUT ;
    USE SIGNAL ;
    PORT
      LAYER M4 ;
        RECT  21.516 35.712 21.6 35.736 ;
    END
  END b[107]
  PIN b[108]
    DIRECTION OUTPUT ;
    USE SIGNAL ;
    PORT
      LAYER M4 ;
        RECT  21.516 35.856 21.6 35.88 ;
    END
  END b[108]
  PIN b[109]
    DIRECTION OUTPUT ;
    USE SIGNAL ;
    PORT
      LAYER M4 ;
        RECT  21.516 36 21.6 36.024 ;
    END
  END b[109]
  PIN b[10]
    DIRECTION OUTPUT ;
    USE SIGNAL ;
    PORT
      LAYER M4 ;
        RECT  21.516 30.96 21.6 30.984 ;
    END
  END b[10]
  PIN b[110]
    DIRECTION OUTPUT ;
    USE SIGNAL ;
    PORT
      LAYER M4 ;
        RECT  21.516 36.144 21.6 36.168 ;
    END
  END b[110]
  PIN b[111]
    DIRECTION OUTPUT ;
    USE SIGNAL ;
    PORT
      LAYER M4 ;
        RECT  21.516 36.288 21.6 36.312 ;
    END
  END b[111]
  PIN b[112]
    DIRECTION OUTPUT ;
    USE SIGNAL ;
    PORT
      LAYER M4 ;
        RECT  21.516 36.432 21.6 36.456 ;
    END
  END b[112]
  PIN b[113]
    DIRECTION OUTPUT ;
    USE SIGNAL ;
    PORT
      LAYER M4 ;
        RECT  21.516 36.576 21.6 36.6 ;
    END
  END b[113]
  PIN b[114]
    DIRECTION OUTPUT ;
    USE SIGNAL ;
    PORT
      LAYER M4 ;
        RECT  21.516 36.72 21.6 36.744 ;
    END
  END b[114]
  PIN b[115]
    DIRECTION OUTPUT ;
    USE SIGNAL ;
    PORT
      LAYER M4 ;
        RECT  21.516 36.864 21.6 36.888 ;
    END
  END b[115]
  PIN b[116]
    DIRECTION OUTPUT ;
    USE SIGNAL ;
    PORT
      LAYER M4 ;
        RECT  21.516 37.008 21.6 37.032 ;
    END
  END b[116]
  PIN b[117]
    DIRECTION OUTPUT ;
    USE SIGNAL ;
    PORT
      LAYER M4 ;
        RECT  21.516 37.152 21.6 37.176 ;
    END
  END b[117]
  PIN b[118]
    DIRECTION OUTPUT ;
    USE SIGNAL ;
    PORT
      LAYER M4 ;
        RECT  21.516 37.296 21.6 37.32 ;
    END
  END b[118]
  PIN b[119]
    DIRECTION OUTPUT ;
    USE SIGNAL ;
    PORT
      LAYER M4 ;
        RECT  21.516 37.44 21.6 37.464 ;
    END
  END b[119]
  PIN b[11]
    DIRECTION OUTPUT ;
    USE SIGNAL ;
    PORT
      LAYER M4 ;
        RECT  21.516 31.104 21.6 31.128 ;
    END
  END b[11]
  PIN b[120]
    DIRECTION OUTPUT ;
    USE SIGNAL ;
    PORT
      LAYER M4 ;
        RECT  21.516 37.584 21.6 37.608 ;
    END
  END b[120]
  PIN b[121]
    DIRECTION OUTPUT ;
    USE SIGNAL ;
    PORT
      LAYER M4 ;
        RECT  21.516 37.728 21.6 37.752 ;
    END
  END b[121]
  PIN b[122]
    DIRECTION OUTPUT ;
    USE SIGNAL ;
    PORT
      LAYER M4 ;
        RECT  21.516 37.872 21.6 37.896 ;
    END
  END b[122]
  PIN b[123]
    DIRECTION OUTPUT ;
    USE SIGNAL ;
    PORT
      LAYER M4 ;
        RECT  21.516 38.016 21.6 38.04 ;
    END
  END b[123]
  PIN b[124]
    DIRECTION OUTPUT ;
    USE SIGNAL ;
    PORT
      LAYER M4 ;
        RECT  21.516 38.16 21.6 38.184 ;
    END
  END b[124]
  PIN b[125]
    DIRECTION OUTPUT ;
    USE SIGNAL ;
    PORT
      LAYER M4 ;
        RECT  21.516 38.304 21.6 38.328 ;
    END
  END b[125]
  PIN b[126]
    DIRECTION OUTPUT ;
    USE SIGNAL ;
    PORT
      LAYER M4 ;
        RECT  21.516 38.448 21.6 38.472 ;
    END
  END b[126]
  PIN b[127]
    DIRECTION OUTPUT ;
    USE SIGNAL ;
    PORT
      LAYER M4 ;
        RECT  21.516 38.592 21.6 38.616 ;
    END
  END b[127]
  PIN b[128]
    DIRECTION OUTPUT ;
    USE SIGNAL ;
    PORT
      LAYER M4 ;
        RECT  21.516 47.952 21.6 47.976 ;
    END
  END b[128]
  PIN b[129]
    DIRECTION OUTPUT ;
    USE SIGNAL ;
    PORT
      LAYER M4 ;
        RECT  21.516 48.096 21.6 48.12 ;
    END
  END b[129]
  PIN b[12]
    DIRECTION OUTPUT ;
    USE SIGNAL ;
    PORT
      LAYER M4 ;
        RECT  21.516 31.248 21.6 31.272 ;
    END
  END b[12]
  PIN b[130]
    DIRECTION OUTPUT ;
    USE SIGNAL ;
    PORT
      LAYER M4 ;
        RECT  21.516 48.24 21.6 48.264 ;
    END
  END b[130]
  PIN b[131]
    DIRECTION OUTPUT ;
    USE SIGNAL ;
    PORT
      LAYER M4 ;
        RECT  21.516 48.384 21.6 48.408 ;
    END
  END b[131]
  PIN b[132]
    DIRECTION OUTPUT ;
    USE SIGNAL ;
    PORT
      LAYER M4 ;
        RECT  21.516 48.528 21.6 48.552 ;
    END
  END b[132]
  PIN b[133]
    DIRECTION OUTPUT ;
    USE SIGNAL ;
    PORT
      LAYER M4 ;
        RECT  21.516 48.672 21.6 48.696 ;
    END
  END b[133]
  PIN b[134]
    DIRECTION OUTPUT ;
    USE SIGNAL ;
    PORT
      LAYER M4 ;
        RECT  21.516 48.816 21.6 48.84 ;
    END
  END b[134]
  PIN b[135]
    DIRECTION OUTPUT ;
    USE SIGNAL ;
    PORT
      LAYER M4 ;
        RECT  21.516 48.96 21.6 48.984 ;
    END
  END b[135]
  PIN b[136]
    DIRECTION OUTPUT ;
    USE SIGNAL ;
    PORT
      LAYER M4 ;
        RECT  21.516 49.104 21.6 49.128 ;
    END
  END b[136]
  PIN b[137]
    DIRECTION OUTPUT ;
    USE SIGNAL ;
    PORT
      LAYER M4 ;
        RECT  21.516 49.248 21.6 49.272 ;
    END
  END b[137]
  PIN b[138]
    DIRECTION OUTPUT ;
    USE SIGNAL ;
    PORT
      LAYER M4 ;
        RECT  21.516 49.392 21.6 49.416 ;
    END
  END b[138]
  PIN b[139]
    DIRECTION OUTPUT ;
    USE SIGNAL ;
    PORT
      LAYER M4 ;
        RECT  21.516 49.536 21.6 49.56 ;
    END
  END b[139]
  PIN b[13]
    DIRECTION OUTPUT ;
    USE SIGNAL ;
    PORT
      LAYER M4 ;
        RECT  21.516 31.392 21.6 31.416 ;
    END
  END b[13]
  PIN b[140]
    DIRECTION OUTPUT ;
    USE SIGNAL ;
    PORT
      LAYER M4 ;
        RECT  21.516 49.68 21.6 49.704 ;
    END
  END b[140]
  PIN b[141]
    DIRECTION OUTPUT ;
    USE SIGNAL ;
    PORT
      LAYER M4 ;
        RECT  21.516 49.824 21.6 49.848 ;
    END
  END b[141]
  PIN b[142]
    DIRECTION OUTPUT ;
    USE SIGNAL ;
    PORT
      LAYER M4 ;
        RECT  21.516 49.968 21.6 49.992 ;
    END
  END b[142]
  PIN b[143]
    DIRECTION OUTPUT ;
    USE SIGNAL ;
    PORT
      LAYER M4 ;
        RECT  21.516 50.112 21.6 50.136 ;
    END
  END b[143]
  PIN b[144]
    DIRECTION OUTPUT ;
    USE SIGNAL ;
    PORT
      LAYER M4 ;
        RECT  21.516 50.256 21.6 50.28 ;
    END
  END b[144]
  PIN b[145]
    DIRECTION OUTPUT ;
    USE SIGNAL ;
    PORT
      LAYER M4 ;
        RECT  21.516 50.4 21.6 50.424 ;
    END
  END b[145]
  PIN b[146]
    DIRECTION OUTPUT ;
    USE SIGNAL ;
    PORT
      LAYER M4 ;
        RECT  21.516 50.544 21.6 50.568 ;
    END
  END b[146]
  PIN b[147]
    DIRECTION OUTPUT ;
    USE SIGNAL ;
    PORT
      LAYER M4 ;
        RECT  21.516 50.688 21.6 50.712 ;
    END
  END b[147]
  PIN b[148]
    DIRECTION OUTPUT ;
    USE SIGNAL ;
    PORT
      LAYER M4 ;
        RECT  21.516 50.832 21.6 50.856 ;
    END
  END b[148]
  PIN b[149]
    DIRECTION OUTPUT ;
    USE SIGNAL ;
    PORT
      LAYER M4 ;
        RECT  21.516 50.976 21.6 51 ;
    END
  END b[149]
  PIN b[14]
    DIRECTION OUTPUT ;
    USE SIGNAL ;
    PORT
      LAYER M4 ;
        RECT  21.516 31.536 21.6 31.56 ;
    END
  END b[14]
  PIN b[150]
    DIRECTION OUTPUT ;
    USE SIGNAL ;
    PORT
      LAYER M4 ;
        RECT  21.516 51.12 21.6 51.144 ;
    END
  END b[150]
  PIN b[151]
    DIRECTION OUTPUT ;
    USE SIGNAL ;
    PORT
      LAYER M4 ;
        RECT  21.516 51.264 21.6 51.288 ;
    END
  END b[151]
  PIN b[152]
    DIRECTION OUTPUT ;
    USE SIGNAL ;
    PORT
      LAYER M4 ;
        RECT  21.516 51.408 21.6 51.432 ;
    END
  END b[152]
  PIN b[153]
    DIRECTION OUTPUT ;
    USE SIGNAL ;
    PORT
      LAYER M4 ;
        RECT  21.516 51.552 21.6 51.576 ;
    END
  END b[153]
  PIN b[154]
    DIRECTION OUTPUT ;
    USE SIGNAL ;
    PORT
      LAYER M4 ;
        RECT  21.516 51.696 21.6 51.72 ;
    END
  END b[154]
  PIN b[155]
    DIRECTION OUTPUT ;
    USE SIGNAL ;
    PORT
      LAYER M4 ;
        RECT  21.516 51.84 21.6 51.864 ;
    END
  END b[155]
  PIN b[156]
    DIRECTION OUTPUT ;
    USE SIGNAL ;
    PORT
      LAYER M4 ;
        RECT  21.516 51.984 21.6 52.008 ;
    END
  END b[156]
  PIN b[157]
    DIRECTION OUTPUT ;
    USE SIGNAL ;
    PORT
      LAYER M4 ;
        RECT  21.516 52.128 21.6 52.152 ;
    END
  END b[157]
  PIN b[158]
    DIRECTION OUTPUT ;
    USE SIGNAL ;
    PORT
      LAYER M4 ;
        RECT  21.516 52.272 21.6 52.296 ;
    END
  END b[158]
  PIN b[159]
    DIRECTION OUTPUT ;
    USE SIGNAL ;
    PORT
      LAYER M4 ;
        RECT  21.516 52.416 21.6 52.44 ;
    END
  END b[159]
  PIN b[15]
    DIRECTION OUTPUT ;
    USE SIGNAL ;
    PORT
      LAYER M4 ;
        RECT  21.516 31.68 21.6 31.704 ;
    END
  END b[15]
  PIN b[160]
    DIRECTION OUTPUT ;
    USE SIGNAL ;
    PORT
      LAYER M4 ;
        RECT  21.516 43.344 21.6 43.368 ;
    END
  END b[160]
  PIN b[161]
    DIRECTION OUTPUT ;
    USE SIGNAL ;
    PORT
      LAYER M4 ;
        RECT  21.516 43.488 21.6 43.512 ;
    END
  END b[161]
  PIN b[162]
    DIRECTION OUTPUT ;
    USE SIGNAL ;
    PORT
      LAYER M4 ;
        RECT  21.516 43.632 21.6 43.656 ;
    END
  END b[162]
  PIN b[163]
    DIRECTION OUTPUT ;
    USE SIGNAL ;
    PORT
      LAYER M4 ;
        RECT  21.516 43.776 21.6 43.8 ;
    END
  END b[163]
  PIN b[164]
    DIRECTION OUTPUT ;
    USE SIGNAL ;
    PORT
      LAYER M4 ;
        RECT  21.516 43.92 21.6 43.944 ;
    END
  END b[164]
  PIN b[165]
    DIRECTION OUTPUT ;
    USE SIGNAL ;
    PORT
      LAYER M4 ;
        RECT  21.516 44.064 21.6 44.088 ;
    END
  END b[165]
  PIN b[166]
    DIRECTION OUTPUT ;
    USE SIGNAL ;
    PORT
      LAYER M4 ;
        RECT  21.516 44.208 21.6 44.232 ;
    END
  END b[166]
  PIN b[167]
    DIRECTION OUTPUT ;
    USE SIGNAL ;
    PORT
      LAYER M4 ;
        RECT  21.516 44.352 21.6 44.376 ;
    END
  END b[167]
  PIN b[168]
    DIRECTION OUTPUT ;
    USE SIGNAL ;
    PORT
      LAYER M4 ;
        RECT  21.516 44.496 21.6 44.52 ;
    END
  END b[168]
  PIN b[169]
    DIRECTION OUTPUT ;
    USE SIGNAL ;
    PORT
      LAYER M4 ;
        RECT  21.516 44.64 21.6 44.664 ;
    END
  END b[169]
  PIN b[16]
    DIRECTION OUTPUT ;
    USE SIGNAL ;
    PORT
      LAYER M4 ;
        RECT  21.516 31.824 21.6 31.848 ;
    END
  END b[16]
  PIN b[170]
    DIRECTION OUTPUT ;
    USE SIGNAL ;
    PORT
      LAYER M4 ;
        RECT  21.516 44.784 21.6 44.808 ;
    END
  END b[170]
  PIN b[171]
    DIRECTION OUTPUT ;
    USE SIGNAL ;
    PORT
      LAYER M4 ;
        RECT  21.516 44.928 21.6 44.952 ;
    END
  END b[171]
  PIN b[172]
    DIRECTION OUTPUT ;
    USE SIGNAL ;
    PORT
      LAYER M4 ;
        RECT  21.516 45.072 21.6 45.096 ;
    END
  END b[172]
  PIN b[173]
    DIRECTION OUTPUT ;
    USE SIGNAL ;
    PORT
      LAYER M4 ;
        RECT  21.516 45.216 21.6 45.24 ;
    END
  END b[173]
  PIN b[174]
    DIRECTION OUTPUT ;
    USE SIGNAL ;
    PORT
      LAYER M4 ;
        RECT  21.516 45.36 21.6 45.384 ;
    END
  END b[174]
  PIN b[175]
    DIRECTION OUTPUT ;
    USE SIGNAL ;
    PORT
      LAYER M4 ;
        RECT  21.516 45.504 21.6 45.528 ;
    END
  END b[175]
  PIN b[176]
    DIRECTION OUTPUT ;
    USE SIGNAL ;
    PORT
      LAYER M4 ;
        RECT  21.516 45.648 21.6 45.672 ;
    END
  END b[176]
  PIN b[177]
    DIRECTION OUTPUT ;
    USE SIGNAL ;
    PORT
      LAYER M4 ;
        RECT  21.516 45.792 21.6 45.816 ;
    END
  END b[177]
  PIN b[178]
    DIRECTION OUTPUT ;
    USE SIGNAL ;
    PORT
      LAYER M4 ;
        RECT  21.516 45.936 21.6 45.96 ;
    END
  END b[178]
  PIN b[179]
    DIRECTION OUTPUT ;
    USE SIGNAL ;
    PORT
      LAYER M4 ;
        RECT  21.516 46.08 21.6 46.104 ;
    END
  END b[179]
  PIN b[17]
    DIRECTION OUTPUT ;
    USE SIGNAL ;
    PORT
      LAYER M4 ;
        RECT  21.516 31.968 21.6 31.992 ;
    END
  END b[17]
  PIN b[180]
    DIRECTION OUTPUT ;
    USE SIGNAL ;
    PORT
      LAYER M4 ;
        RECT  21.516 46.224 21.6 46.248 ;
    END
  END b[180]
  PIN b[181]
    DIRECTION OUTPUT ;
    USE SIGNAL ;
    PORT
      LAYER M4 ;
        RECT  21.516 46.368 21.6 46.392 ;
    END
  END b[181]
  PIN b[182]
    DIRECTION OUTPUT ;
    USE SIGNAL ;
    PORT
      LAYER M4 ;
        RECT  21.516 46.512 21.6 46.536 ;
    END
  END b[182]
  PIN b[183]
    DIRECTION OUTPUT ;
    USE SIGNAL ;
    PORT
      LAYER M4 ;
        RECT  21.516 46.656 21.6 46.68 ;
    END
  END b[183]
  PIN b[184]
    DIRECTION OUTPUT ;
    USE SIGNAL ;
    PORT
      LAYER M4 ;
        RECT  21.516 46.8 21.6 46.824 ;
    END
  END b[184]
  PIN b[185]
    DIRECTION OUTPUT ;
    USE SIGNAL ;
    PORT
      LAYER M4 ;
        RECT  21.516 46.944 21.6 46.968 ;
    END
  END b[185]
  PIN b[186]
    DIRECTION OUTPUT ;
    USE SIGNAL ;
    PORT
      LAYER M4 ;
        RECT  21.516 47.088 21.6 47.112 ;
    END
  END b[186]
  PIN b[187]
    DIRECTION OUTPUT ;
    USE SIGNAL ;
    PORT
      LAYER M4 ;
        RECT  21.516 47.232 21.6 47.256 ;
    END
  END b[187]
  PIN b[188]
    DIRECTION OUTPUT ;
    USE SIGNAL ;
    PORT
      LAYER M4 ;
        RECT  21.516 47.376 21.6 47.4 ;
    END
  END b[188]
  PIN b[189]
    DIRECTION OUTPUT ;
    USE SIGNAL ;
    PORT
      LAYER M4 ;
        RECT  21.516 47.52 21.6 47.544 ;
    END
  END b[189]
  PIN b[18]
    DIRECTION OUTPUT ;
    USE SIGNAL ;
    PORT
      LAYER M4 ;
        RECT  21.516 32.112 21.6 32.136 ;
    END
  END b[18]
  PIN b[190]
    DIRECTION OUTPUT ;
    USE SIGNAL ;
    PORT
      LAYER M4 ;
        RECT  21.516 47.664 21.6 47.688 ;
    END
  END b[190]
  PIN b[191]
    DIRECTION OUTPUT ;
    USE SIGNAL ;
    PORT
      LAYER M4 ;
        RECT  21.516 47.808 21.6 47.832 ;
    END
  END b[191]
  PIN b[192]
    DIRECTION OUTPUT ;
    USE SIGNAL ;
    PORT
      LAYER M4 ;
        RECT  21.516 5.328 21.6 5.352 ;
    END
  END b[192]
  PIN b[193]
    DIRECTION OUTPUT ;
    USE SIGNAL ;
    PORT
      LAYER M4 ;
        RECT  21.516 5.472 21.6 5.496 ;
    END
  END b[193]
  PIN b[194]
    DIRECTION OUTPUT ;
    USE SIGNAL ;
    PORT
      LAYER M4 ;
        RECT  21.516 5.616 21.6 5.64 ;
    END
  END b[194]
  PIN b[195]
    DIRECTION OUTPUT ;
    USE SIGNAL ;
    PORT
      LAYER M4 ;
        RECT  21.516 5.76 21.6 5.784 ;
    END
  END b[195]
  PIN b[196]
    DIRECTION OUTPUT ;
    USE SIGNAL ;
    PORT
      LAYER M4 ;
        RECT  21.516 5.904 21.6 5.928 ;
    END
  END b[196]
  PIN b[197]
    DIRECTION OUTPUT ;
    USE SIGNAL ;
    PORT
      LAYER M4 ;
        RECT  21.516 6.048 21.6 6.072 ;
    END
  END b[197]
  PIN b[198]
    DIRECTION OUTPUT ;
    USE SIGNAL ;
    PORT
      LAYER M4 ;
        RECT  21.516 6.192 21.6 6.216 ;
    END
  END b[198]
  PIN b[199]
    DIRECTION OUTPUT ;
    USE SIGNAL ;
    PORT
      LAYER M4 ;
        RECT  21.516 6.336 21.6 6.36 ;
    END
  END b[199]
  PIN b[19]
    DIRECTION OUTPUT ;
    USE SIGNAL ;
    PORT
      LAYER M4 ;
        RECT  21.516 32.256 21.6 32.28 ;
    END
  END b[19]
  PIN b[1]
    DIRECTION OUTPUT ;
    USE SIGNAL ;
    PORT
      LAYER M4 ;
        RECT  21.516 29.664 21.6 29.688 ;
    END
  END b[1]
  PIN b[200]
    DIRECTION OUTPUT ;
    USE SIGNAL ;
    PORT
      LAYER M4 ;
        RECT  21.516 6.48 21.6 6.504 ;
    END
  END b[200]
  PIN b[201]
    DIRECTION OUTPUT ;
    USE SIGNAL ;
    PORT
      LAYER M4 ;
        RECT  21.516 6.624 21.6 6.648 ;
    END
  END b[201]
  PIN b[202]
    DIRECTION OUTPUT ;
    USE SIGNAL ;
    PORT
      LAYER M4 ;
        RECT  21.516 6.768 21.6 6.792 ;
    END
  END b[202]
  PIN b[203]
    DIRECTION OUTPUT ;
    USE SIGNAL ;
    PORT
      LAYER M4 ;
        RECT  21.516 6.912 21.6 6.936 ;
    END
  END b[203]
  PIN b[204]
    DIRECTION OUTPUT ;
    USE SIGNAL ;
    PORT
      LAYER M4 ;
        RECT  21.516 7.056 21.6 7.08 ;
    END
  END b[204]
  PIN b[205]
    DIRECTION OUTPUT ;
    USE SIGNAL ;
    PORT
      LAYER M4 ;
        RECT  21.516 7.2 21.6 7.224 ;
    END
  END b[205]
  PIN b[206]
    DIRECTION OUTPUT ;
    USE SIGNAL ;
    PORT
      LAYER M4 ;
        RECT  21.516 7.344 21.6 7.368 ;
    END
  END b[206]
  PIN b[207]
    DIRECTION OUTPUT ;
    USE SIGNAL ;
    PORT
      LAYER M4 ;
        RECT  21.516 7.488 21.6 7.512 ;
    END
  END b[207]
  PIN b[208]
    DIRECTION OUTPUT ;
    USE SIGNAL ;
    PORT
      LAYER M4 ;
        RECT  21.516 7.632 21.6 7.656 ;
    END
  END b[208]
  PIN b[209]
    DIRECTION OUTPUT ;
    USE SIGNAL ;
    PORT
      LAYER M4 ;
        RECT  21.516 7.776 21.6 7.8 ;
    END
  END b[209]
  PIN b[20]
    DIRECTION OUTPUT ;
    USE SIGNAL ;
    PORT
      LAYER M4 ;
        RECT  21.516 32.4 21.6 32.424 ;
    END
  END b[20]
  PIN b[210]
    DIRECTION OUTPUT ;
    USE SIGNAL ;
    PORT
      LAYER M4 ;
        RECT  21.516 7.92 21.6 7.944 ;
    END
  END b[210]
  PIN b[211]
    DIRECTION OUTPUT ;
    USE SIGNAL ;
    PORT
      LAYER M4 ;
        RECT  21.516 8.064 21.6 8.088 ;
    END
  END b[211]
  PIN b[212]
    DIRECTION OUTPUT ;
    USE SIGNAL ;
    PORT
      LAYER M4 ;
        RECT  21.516 8.208 21.6 8.232 ;
    END
  END b[212]
  PIN b[213]
    DIRECTION OUTPUT ;
    USE SIGNAL ;
    PORT
      LAYER M4 ;
        RECT  21.516 8.352 21.6 8.376 ;
    END
  END b[213]
  PIN b[214]
    DIRECTION OUTPUT ;
    USE SIGNAL ;
    PORT
      LAYER M4 ;
        RECT  21.516 8.496 21.6 8.52 ;
    END
  END b[214]
  PIN b[215]
    DIRECTION OUTPUT ;
    USE SIGNAL ;
    PORT
      LAYER M4 ;
        RECT  21.516 8.64 21.6 8.664 ;
    END
  END b[215]
  PIN b[216]
    DIRECTION OUTPUT ;
    USE SIGNAL ;
    PORT
      LAYER M4 ;
        RECT  21.516 8.784 21.6 8.808 ;
    END
  END b[216]
  PIN b[217]
    DIRECTION OUTPUT ;
    USE SIGNAL ;
    PORT
      LAYER M4 ;
        RECT  21.516 8.928 21.6 8.952 ;
    END
  END b[217]
  PIN b[218]
    DIRECTION OUTPUT ;
    USE SIGNAL ;
    PORT
      LAYER M4 ;
        RECT  21.516 9.072 21.6 9.096 ;
    END
  END b[218]
  PIN b[219]
    DIRECTION OUTPUT ;
    USE SIGNAL ;
    PORT
      LAYER M4 ;
        RECT  21.516 9.216 21.6 9.24 ;
    END
  END b[219]
  PIN b[21]
    DIRECTION OUTPUT ;
    USE SIGNAL ;
    PORT
      LAYER M4 ;
        RECT  21.516 32.544 21.6 32.568 ;
    END
  END b[21]
  PIN b[220]
    DIRECTION OUTPUT ;
    USE SIGNAL ;
    PORT
      LAYER M4 ;
        RECT  21.516 9.36 21.6 9.384 ;
    END
  END b[220]
  PIN b[221]
    DIRECTION OUTPUT ;
    USE SIGNAL ;
    PORT
      LAYER M4 ;
        RECT  21.516 9.504 21.6 9.528 ;
    END
  END b[221]
  PIN b[222]
    DIRECTION OUTPUT ;
    USE SIGNAL ;
    PORT
      LAYER M4 ;
        RECT  21.516 9.648 21.6 9.672 ;
    END
  END b[222]
  PIN b[223]
    DIRECTION OUTPUT ;
    USE SIGNAL ;
    PORT
      LAYER M4 ;
        RECT  21.516 9.792 21.6 9.816 ;
    END
  END b[223]
  PIN b[224]
    DIRECTION OUTPUT ;
    USE SIGNAL ;
    PORT
      LAYER M4 ;
        RECT  21.516 19.152 21.6 19.176 ;
    END
  END b[224]
  PIN b[225]
    DIRECTION OUTPUT ;
    USE SIGNAL ;
    PORT
      LAYER M4 ;
        RECT  21.516 19.296 21.6 19.32 ;
    END
  END b[225]
  PIN b[226]
    DIRECTION OUTPUT ;
    USE SIGNAL ;
    PORT
      LAYER M4 ;
        RECT  21.516 19.44 21.6 19.464 ;
    END
  END b[226]
  PIN b[227]
    DIRECTION OUTPUT ;
    USE SIGNAL ;
    PORT
      LAYER M4 ;
        RECT  21.516 19.584 21.6 19.608 ;
    END
  END b[227]
  PIN b[228]
    DIRECTION OUTPUT ;
    USE SIGNAL ;
    PORT
      LAYER M4 ;
        RECT  21.516 19.728 21.6 19.752 ;
    END
  END b[228]
  PIN b[229]
    DIRECTION OUTPUT ;
    USE SIGNAL ;
    PORT
      LAYER M4 ;
        RECT  21.516 19.872 21.6 19.896 ;
    END
  END b[229]
  PIN b[22]
    DIRECTION OUTPUT ;
    USE SIGNAL ;
    PORT
      LAYER M4 ;
        RECT  21.516 32.688 21.6 32.712 ;
    END
  END b[22]
  PIN b[230]
    DIRECTION OUTPUT ;
    USE SIGNAL ;
    PORT
      LAYER M4 ;
        RECT  21.516 20.016 21.6 20.04 ;
    END
  END b[230]
  PIN b[231]
    DIRECTION OUTPUT ;
    USE SIGNAL ;
    PORT
      LAYER M4 ;
        RECT  21.516 20.16 21.6 20.184 ;
    END
  END b[231]
  PIN b[232]
    DIRECTION OUTPUT ;
    USE SIGNAL ;
    PORT
      LAYER M4 ;
        RECT  21.516 20.304 21.6 20.328 ;
    END
  END b[232]
  PIN b[233]
    DIRECTION OUTPUT ;
    USE SIGNAL ;
    PORT
      LAYER M4 ;
        RECT  21.516 20.448 21.6 20.472 ;
    END
  END b[233]
  PIN b[234]
    DIRECTION OUTPUT ;
    USE SIGNAL ;
    PORT
      LAYER M4 ;
        RECT  21.516 20.592 21.6 20.616 ;
    END
  END b[234]
  PIN b[235]
    DIRECTION OUTPUT ;
    USE SIGNAL ;
    PORT
      LAYER M4 ;
        RECT  21.516 20.736 21.6 20.76 ;
    END
  END b[235]
  PIN b[236]
    DIRECTION OUTPUT ;
    USE SIGNAL ;
    PORT
      LAYER M4 ;
        RECT  21.516 20.88 21.6 20.904 ;
    END
  END b[236]
  PIN b[237]
    DIRECTION OUTPUT ;
    USE SIGNAL ;
    PORT
      LAYER M4 ;
        RECT  21.516 21.024 21.6 21.048 ;
    END
  END b[237]
  PIN b[238]
    DIRECTION OUTPUT ;
    USE SIGNAL ;
    PORT
      LAYER M4 ;
        RECT  21.516 21.168 21.6 21.192 ;
    END
  END b[238]
  PIN b[239]
    DIRECTION OUTPUT ;
    USE SIGNAL ;
    PORT
      LAYER M4 ;
        RECT  21.516 21.312 21.6 21.336 ;
    END
  END b[239]
  PIN b[23]
    DIRECTION OUTPUT ;
    USE SIGNAL ;
    PORT
      LAYER M4 ;
        RECT  21.516 32.832 21.6 32.856 ;
    END
  END b[23]
  PIN b[240]
    DIRECTION OUTPUT ;
    USE SIGNAL ;
    PORT
      LAYER M4 ;
        RECT  21.516 21.456 21.6 21.48 ;
    END
  END b[240]
  PIN b[241]
    DIRECTION OUTPUT ;
    USE SIGNAL ;
    PORT
      LAYER M4 ;
        RECT  21.516 21.6 21.6 21.624 ;
    END
  END b[241]
  PIN b[242]
    DIRECTION OUTPUT ;
    USE SIGNAL ;
    PORT
      LAYER M4 ;
        RECT  21.516 21.744 21.6 21.768 ;
    END
  END b[242]
  PIN b[243]
    DIRECTION OUTPUT ;
    USE SIGNAL ;
    PORT
      LAYER M4 ;
        RECT  21.516 21.888 21.6 21.912 ;
    END
  END b[243]
  PIN b[244]
    DIRECTION OUTPUT ;
    USE SIGNAL ;
    PORT
      LAYER M4 ;
        RECT  21.516 22.032 21.6 22.056 ;
    END
  END b[244]
  PIN b[245]
    DIRECTION OUTPUT ;
    USE SIGNAL ;
    PORT
      LAYER M4 ;
        RECT  21.516 22.176 21.6 22.2 ;
    END
  END b[245]
  PIN b[246]
    DIRECTION OUTPUT ;
    USE SIGNAL ;
    PORT
      LAYER M4 ;
        RECT  21.516 22.32 21.6 22.344 ;
    END
  END b[246]
  PIN b[247]
    DIRECTION OUTPUT ;
    USE SIGNAL ;
    PORT
      LAYER M4 ;
        RECT  21.516 22.464 21.6 22.488 ;
    END
  END b[247]
  PIN b[248]
    DIRECTION OUTPUT ;
    USE SIGNAL ;
    PORT
      LAYER M4 ;
        RECT  21.516 22.608 21.6 22.632 ;
    END
  END b[248]
  PIN b[249]
    DIRECTION OUTPUT ;
    USE SIGNAL ;
    PORT
      LAYER M4 ;
        RECT  21.516 22.752 21.6 22.776 ;
    END
  END b[249]
  PIN b[24]
    DIRECTION OUTPUT ;
    USE SIGNAL ;
    PORT
      LAYER M4 ;
        RECT  21.516 32.976 21.6 33 ;
    END
  END b[24]
  PIN b[250]
    DIRECTION OUTPUT ;
    USE SIGNAL ;
    PORT
      LAYER M4 ;
        RECT  21.516 22.896 21.6 22.92 ;
    END
  END b[250]
  PIN b[251]
    DIRECTION OUTPUT ;
    USE SIGNAL ;
    PORT
      LAYER M4 ;
        RECT  21.516 23.04 21.6 23.064 ;
    END
  END b[251]
  PIN b[252]
    DIRECTION OUTPUT ;
    USE SIGNAL ;
    PORT
      LAYER M4 ;
        RECT  21.516 23.184 21.6 23.208 ;
    END
  END b[252]
  PIN b[253]
    DIRECTION OUTPUT ;
    USE SIGNAL ;
    PORT
      LAYER M4 ;
        RECT  21.516 23.328 21.6 23.352 ;
    END
  END b[253]
  PIN b[254]
    DIRECTION OUTPUT ;
    USE SIGNAL ;
    PORT
      LAYER M4 ;
        RECT  21.516 23.472 21.6 23.496 ;
    END
  END b[254]
  PIN b[255]
    DIRECTION OUTPUT ;
    USE SIGNAL ;
    PORT
      LAYER M4 ;
        RECT  21.516 23.616 21.6 23.64 ;
    END
  END b[255]
  PIN b[256]
    DIRECTION OUTPUT ;
    USE SIGNAL ;
    PORT
      LAYER M4 ;
        RECT  21.516 9.936 21.6 9.96 ;
    END
  END b[256]
  PIN b[257]
    DIRECTION OUTPUT ;
    USE SIGNAL ;
    PORT
      LAYER M4 ;
        RECT  21.516 10.08 21.6 10.104 ;
    END
  END b[257]
  PIN b[258]
    DIRECTION OUTPUT ;
    USE SIGNAL ;
    PORT
      LAYER M4 ;
        RECT  21.516 10.224 21.6 10.248 ;
    END
  END b[258]
  PIN b[259]
    DIRECTION OUTPUT ;
    USE SIGNAL ;
    PORT
      LAYER M4 ;
        RECT  21.516 10.368 21.6 10.392 ;
    END
  END b[259]
  PIN b[25]
    DIRECTION OUTPUT ;
    USE SIGNAL ;
    PORT
      LAYER M4 ;
        RECT  21.516 33.12 21.6 33.144 ;
    END
  END b[25]
  PIN b[260]
    DIRECTION OUTPUT ;
    USE SIGNAL ;
    PORT
      LAYER M4 ;
        RECT  21.516 10.512 21.6 10.536 ;
    END
  END b[260]
  PIN b[261]
    DIRECTION OUTPUT ;
    USE SIGNAL ;
    PORT
      LAYER M4 ;
        RECT  21.516 10.656 21.6 10.68 ;
    END
  END b[261]
  PIN b[262]
    DIRECTION OUTPUT ;
    USE SIGNAL ;
    PORT
      LAYER M4 ;
        RECT  21.516 10.8 21.6 10.824 ;
    END
  END b[262]
  PIN b[263]
    DIRECTION OUTPUT ;
    USE SIGNAL ;
    PORT
      LAYER M4 ;
        RECT  21.516 10.944 21.6 10.968 ;
    END
  END b[263]
  PIN b[264]
    DIRECTION OUTPUT ;
    USE SIGNAL ;
    PORT
      LAYER M4 ;
        RECT  21.516 11.088 21.6 11.112 ;
    END
  END b[264]
  PIN b[265]
    DIRECTION OUTPUT ;
    USE SIGNAL ;
    PORT
      LAYER M4 ;
        RECT  21.516 11.232 21.6 11.256 ;
    END
  END b[265]
  PIN b[266]
    DIRECTION OUTPUT ;
    USE SIGNAL ;
    PORT
      LAYER M4 ;
        RECT  21.516 11.376 21.6 11.4 ;
    END
  END b[266]
  PIN b[267]
    DIRECTION OUTPUT ;
    USE SIGNAL ;
    PORT
      LAYER M4 ;
        RECT  21.516 11.52 21.6 11.544 ;
    END
  END b[267]
  PIN b[268]
    DIRECTION OUTPUT ;
    USE SIGNAL ;
    PORT
      LAYER M4 ;
        RECT  21.516 11.664 21.6 11.688 ;
    END
  END b[268]
  PIN b[269]
    DIRECTION OUTPUT ;
    USE SIGNAL ;
    PORT
      LAYER M4 ;
        RECT  21.516 11.808 21.6 11.832 ;
    END
  END b[269]
  PIN b[26]
    DIRECTION OUTPUT ;
    USE SIGNAL ;
    PORT
      LAYER M4 ;
        RECT  21.516 33.264 21.6 33.288 ;
    END
  END b[26]
  PIN b[270]
    DIRECTION OUTPUT ;
    USE SIGNAL ;
    PORT
      LAYER M4 ;
        RECT  21.516 11.952 21.6 11.976 ;
    END
  END b[270]
  PIN b[271]
    DIRECTION OUTPUT ;
    USE SIGNAL ;
    PORT
      LAYER M4 ;
        RECT  21.516 12.096 21.6 12.12 ;
    END
  END b[271]
  PIN b[272]
    DIRECTION OUTPUT ;
    USE SIGNAL ;
    PORT
      LAYER M4 ;
        RECT  21.516 12.24 21.6 12.264 ;
    END
  END b[272]
  PIN b[273]
    DIRECTION OUTPUT ;
    USE SIGNAL ;
    PORT
      LAYER M4 ;
        RECT  21.516 12.384 21.6 12.408 ;
    END
  END b[273]
  PIN b[274]
    DIRECTION OUTPUT ;
    USE SIGNAL ;
    PORT
      LAYER M4 ;
        RECT  21.516 12.528 21.6 12.552 ;
    END
  END b[274]
  PIN b[275]
    DIRECTION OUTPUT ;
    USE SIGNAL ;
    PORT
      LAYER M4 ;
        RECT  21.516 12.672 21.6 12.696 ;
    END
  END b[275]
  PIN b[276]
    DIRECTION OUTPUT ;
    USE SIGNAL ;
    PORT
      LAYER M4 ;
        RECT  21.516 12.816 21.6 12.84 ;
    END
  END b[276]
  PIN b[277]
    DIRECTION OUTPUT ;
    USE SIGNAL ;
    PORT
      LAYER M4 ;
        RECT  21.516 12.96 21.6 12.984 ;
    END
  END b[277]
  PIN b[278]
    DIRECTION OUTPUT ;
    USE SIGNAL ;
    PORT
      LAYER M4 ;
        RECT  21.516 13.104 21.6 13.128 ;
    END
  END b[278]
  PIN b[279]
    DIRECTION OUTPUT ;
    USE SIGNAL ;
    PORT
      LAYER M4 ;
        RECT  21.516 13.248 21.6 13.272 ;
    END
  END b[279]
  PIN b[27]
    DIRECTION OUTPUT ;
    USE SIGNAL ;
    PORT
      LAYER M4 ;
        RECT  21.516 33.408 21.6 33.432 ;
    END
  END b[27]
  PIN b[280]
    DIRECTION OUTPUT ;
    USE SIGNAL ;
    PORT
      LAYER M4 ;
        RECT  21.516 13.392 21.6 13.416 ;
    END
  END b[280]
  PIN b[281]
    DIRECTION OUTPUT ;
    USE SIGNAL ;
    PORT
      LAYER M4 ;
        RECT  21.516 13.536 21.6 13.56 ;
    END
  END b[281]
  PIN b[282]
    DIRECTION OUTPUT ;
    USE SIGNAL ;
    PORT
      LAYER M4 ;
        RECT  21.516 13.68 21.6 13.704 ;
    END
  END b[282]
  PIN b[283]
    DIRECTION OUTPUT ;
    USE SIGNAL ;
    PORT
      LAYER M4 ;
        RECT  21.516 13.824 21.6 13.848 ;
    END
  END b[283]
  PIN b[284]
    DIRECTION OUTPUT ;
    USE SIGNAL ;
    PORT
      LAYER M4 ;
        RECT  21.516 13.968 21.6 13.992 ;
    END
  END b[284]
  PIN b[285]
    DIRECTION OUTPUT ;
    USE SIGNAL ;
    PORT
      LAYER M4 ;
        RECT  21.516 14.112 21.6 14.136 ;
    END
  END b[285]
  PIN b[286]
    DIRECTION OUTPUT ;
    USE SIGNAL ;
    PORT
      LAYER M4 ;
        RECT  21.516 14.256 21.6 14.28 ;
    END
  END b[286]
  PIN b[287]
    DIRECTION OUTPUT ;
    USE SIGNAL ;
    PORT
      LAYER M4 ;
        RECT  21.516 14.4 21.6 14.424 ;
    END
  END b[287]
  PIN b[288]
    DIRECTION OUTPUT ;
    USE SIGNAL ;
    PORT
      LAYER M4 ;
        RECT  21.516 14.544 21.6 14.568 ;
    END
  END b[288]
  PIN b[289]
    DIRECTION OUTPUT ;
    USE SIGNAL ;
    PORT
      LAYER M4 ;
        RECT  21.516 14.688 21.6 14.712 ;
    END
  END b[289]
  PIN b[28]
    DIRECTION OUTPUT ;
    USE SIGNAL ;
    PORT
      LAYER M4 ;
        RECT  21.516 33.552 21.6 33.576 ;
    END
  END b[28]
  PIN b[290]
    DIRECTION OUTPUT ;
    USE SIGNAL ;
    PORT
      LAYER M4 ;
        RECT  21.516 14.832 21.6 14.856 ;
    END
  END b[290]
  PIN b[291]
    DIRECTION OUTPUT ;
    USE SIGNAL ;
    PORT
      LAYER M4 ;
        RECT  21.516 14.976 21.6 15 ;
    END
  END b[291]
  PIN b[292]
    DIRECTION OUTPUT ;
    USE SIGNAL ;
    PORT
      LAYER M4 ;
        RECT  21.516 15.12 21.6 15.144 ;
    END
  END b[292]
  PIN b[293]
    DIRECTION OUTPUT ;
    USE SIGNAL ;
    PORT
      LAYER M4 ;
        RECT  21.516 15.264 21.6 15.288 ;
    END
  END b[293]
  PIN b[294]
    DIRECTION OUTPUT ;
    USE SIGNAL ;
    PORT
      LAYER M4 ;
        RECT  21.516 15.408 21.6 15.432 ;
    END
  END b[294]
  PIN b[295]
    DIRECTION OUTPUT ;
    USE SIGNAL ;
    PORT
      LAYER M4 ;
        RECT  21.516 15.552 21.6 15.576 ;
    END
  END b[295]
  PIN b[296]
    DIRECTION OUTPUT ;
    USE SIGNAL ;
    PORT
      LAYER M4 ;
        RECT  21.516 15.696 21.6 15.72 ;
    END
  END b[296]
  PIN b[297]
    DIRECTION OUTPUT ;
    USE SIGNAL ;
    PORT
      LAYER M4 ;
        RECT  21.516 15.84 21.6 15.864 ;
    END
  END b[297]
  PIN b[298]
    DIRECTION OUTPUT ;
    USE SIGNAL ;
    PORT
      LAYER M4 ;
        RECT  21.516 15.984 21.6 16.008 ;
    END
  END b[298]
  PIN b[299]
    DIRECTION OUTPUT ;
    USE SIGNAL ;
    PORT
      LAYER M4 ;
        RECT  21.516 16.128 21.6 16.152 ;
    END
  END b[299]
  PIN b[29]
    DIRECTION OUTPUT ;
    USE SIGNAL ;
    PORT
      LAYER M4 ;
        RECT  21.516 33.696 21.6 33.72 ;
    END
  END b[29]
  PIN b[2]
    DIRECTION OUTPUT ;
    USE SIGNAL ;
    PORT
      LAYER M4 ;
        RECT  21.516 29.808 21.6 29.832 ;
    END
  END b[2]
  PIN b[300]
    DIRECTION OUTPUT ;
    USE SIGNAL ;
    PORT
      LAYER M4 ;
        RECT  21.516 16.272 21.6 16.296 ;
    END
  END b[300]
  PIN b[301]
    DIRECTION OUTPUT ;
    USE SIGNAL ;
    PORT
      LAYER M4 ;
        RECT  21.516 16.416 21.6 16.44 ;
    END
  END b[301]
  PIN b[302]
    DIRECTION OUTPUT ;
    USE SIGNAL ;
    PORT
      LAYER M4 ;
        RECT  21.516 16.56 21.6 16.584 ;
    END
  END b[302]
  PIN b[303]
    DIRECTION OUTPUT ;
    USE SIGNAL ;
    PORT
      LAYER M4 ;
        RECT  21.516 16.704 21.6 16.728 ;
    END
  END b[303]
  PIN b[304]
    DIRECTION OUTPUT ;
    USE SIGNAL ;
    PORT
      LAYER M4 ;
        RECT  21.516 16.848 21.6 16.872 ;
    END
  END b[304]
  PIN b[305]
    DIRECTION OUTPUT ;
    USE SIGNAL ;
    PORT
      LAYER M4 ;
        RECT  21.516 16.992 21.6 17.016 ;
    END
  END b[305]
  PIN b[306]
    DIRECTION OUTPUT ;
    USE SIGNAL ;
    PORT
      LAYER M4 ;
        RECT  21.516 17.136 21.6 17.16 ;
    END
  END b[306]
  PIN b[307]
    DIRECTION OUTPUT ;
    USE SIGNAL ;
    PORT
      LAYER M4 ;
        RECT  21.516 17.28 21.6 17.304 ;
    END
  END b[307]
  PIN b[308]
    DIRECTION OUTPUT ;
    USE SIGNAL ;
    PORT
      LAYER M4 ;
        RECT  21.516 17.424 21.6 17.448 ;
    END
  END b[308]
  PIN b[309]
    DIRECTION OUTPUT ;
    USE SIGNAL ;
    PORT
      LAYER M4 ;
        RECT  21.516 17.568 21.6 17.592 ;
    END
  END b[309]
  PIN b[30]
    DIRECTION OUTPUT ;
    USE SIGNAL ;
    PORT
      LAYER M4 ;
        RECT  21.516 33.84 21.6 33.864 ;
    END
  END b[30]
  PIN b[310]
    DIRECTION OUTPUT ;
    USE SIGNAL ;
    PORT
      LAYER M4 ;
        RECT  21.516 17.712 21.6 17.736 ;
    END
  END b[310]
  PIN b[311]
    DIRECTION OUTPUT ;
    USE SIGNAL ;
    PORT
      LAYER M4 ;
        RECT  21.516 17.856 21.6 17.88 ;
    END
  END b[311]
  PIN b[312]
    DIRECTION OUTPUT ;
    USE SIGNAL ;
    PORT
      LAYER M4 ;
        RECT  21.516 18 21.6 18.024 ;
    END
  END b[312]
  PIN b[313]
    DIRECTION OUTPUT ;
    USE SIGNAL ;
    PORT
      LAYER M4 ;
        RECT  21.516 18.144 21.6 18.168 ;
    END
  END b[313]
  PIN b[314]
    DIRECTION OUTPUT ;
    USE SIGNAL ;
    PORT
      LAYER M4 ;
        RECT  21.516 18.288 21.6 18.312 ;
    END
  END b[314]
  PIN b[315]
    DIRECTION OUTPUT ;
    USE SIGNAL ;
    PORT
      LAYER M4 ;
        RECT  21.516 18.432 21.6 18.456 ;
    END
  END b[315]
  PIN b[316]
    DIRECTION OUTPUT ;
    USE SIGNAL ;
    PORT
      LAYER M4 ;
        RECT  21.516 18.576 21.6 18.6 ;
    END
  END b[316]
  PIN b[317]
    DIRECTION OUTPUT ;
    USE SIGNAL ;
    PORT
      LAYER M4 ;
        RECT  21.516 18.72 21.6 18.744 ;
    END
  END b[317]
  PIN b[318]
    DIRECTION OUTPUT ;
    USE SIGNAL ;
    PORT
      LAYER M4 ;
        RECT  21.516 18.864 21.6 18.888 ;
    END
  END b[318]
  PIN b[319]
    DIRECTION OUTPUT ;
    USE SIGNAL ;
    PORT
      LAYER M4 ;
        RECT  21.516 19.008 21.6 19.032 ;
    END
  END b[319]
  PIN b[31]
    DIRECTION OUTPUT ;
    USE SIGNAL ;
    PORT
      LAYER M4 ;
        RECT  21.516 33.984 21.6 34.008 ;
    END
  END b[31]
  PIN b[320]
    DIRECTION OUTPUT ;
    USE SIGNAL ;
    PORT
      LAYER M4 ;
        RECT  21.516 23.76 21.6 23.784 ;
    END
  END b[320]
  PIN b[321]
    DIRECTION OUTPUT ;
    USE SIGNAL ;
    PORT
      LAYER M4 ;
        RECT  21.516 23.904 21.6 23.928 ;
    END
  END b[321]
  PIN b[322]
    DIRECTION OUTPUT ;
    USE SIGNAL ;
    PORT
      LAYER M4 ;
        RECT  21.516 24.048 21.6 24.072 ;
    END
  END b[322]
  PIN b[323]
    DIRECTION OUTPUT ;
    USE SIGNAL ;
    PORT
      LAYER M4 ;
        RECT  21.516 24.192 21.6 24.216 ;
    END
  END b[323]
  PIN b[324]
    DIRECTION OUTPUT ;
    USE SIGNAL ;
    PORT
      LAYER M4 ;
        RECT  21.516 24.336 21.6 24.36 ;
    END
  END b[324]
  PIN b[325]
    DIRECTION OUTPUT ;
    USE SIGNAL ;
    PORT
      LAYER M4 ;
        RECT  21.516 24.48 21.6 24.504 ;
    END
  END b[325]
  PIN b[326]
    DIRECTION OUTPUT ;
    USE SIGNAL ;
    PORT
      LAYER M4 ;
        RECT  21.516 24.624 21.6 24.648 ;
    END
  END b[326]
  PIN b[327]
    DIRECTION OUTPUT ;
    USE SIGNAL ;
    PORT
      LAYER M4 ;
        RECT  21.516 24.768 21.6 24.792 ;
    END
  END b[327]
  PIN b[328]
    DIRECTION OUTPUT ;
    USE SIGNAL ;
    PORT
      LAYER M4 ;
        RECT  21.516 24.912 21.6 24.936 ;
    END
  END b[328]
  PIN b[329]
    DIRECTION OUTPUT ;
    USE SIGNAL ;
    PORT
      LAYER M4 ;
        RECT  21.516 25.056 21.6 25.08 ;
    END
  END b[329]
  PIN b[32]
    DIRECTION OUTPUT ;
    USE SIGNAL ;
    PORT
      LAYER M4 ;
        RECT  21.516 38.736 21.6 38.76 ;
    END
  END b[32]
  PIN b[330]
    DIRECTION OUTPUT ;
    USE SIGNAL ;
    PORT
      LAYER M4 ;
        RECT  21.516 25.2 21.6 25.224 ;
    END
  END b[330]
  PIN b[331]
    DIRECTION OUTPUT ;
    USE SIGNAL ;
    PORT
      LAYER M4 ;
        RECT  21.516 25.344 21.6 25.368 ;
    END
  END b[331]
  PIN b[332]
    DIRECTION OUTPUT ;
    USE SIGNAL ;
    PORT
      LAYER M4 ;
        RECT  21.516 25.488 21.6 25.512 ;
    END
  END b[332]
  PIN b[333]
    DIRECTION OUTPUT ;
    USE SIGNAL ;
    PORT
      LAYER M4 ;
        RECT  21.516 25.632 21.6 25.656 ;
    END
  END b[333]
  PIN b[334]
    DIRECTION OUTPUT ;
    USE SIGNAL ;
    PORT
      LAYER M4 ;
        RECT  21.516 25.776 21.6 25.8 ;
    END
  END b[334]
  PIN b[335]
    DIRECTION OUTPUT ;
    USE SIGNAL ;
    PORT
      LAYER M4 ;
        RECT  21.516 25.92 21.6 25.944 ;
    END
  END b[335]
  PIN b[336]
    DIRECTION OUTPUT ;
    USE SIGNAL ;
    PORT
      LAYER M4 ;
        RECT  21.516 26.064 21.6 26.088 ;
    END
  END b[336]
  PIN b[337]
    DIRECTION OUTPUT ;
    USE SIGNAL ;
    PORT
      LAYER M4 ;
        RECT  21.516 26.208 21.6 26.232 ;
    END
  END b[337]
  PIN b[338]
    DIRECTION OUTPUT ;
    USE SIGNAL ;
    PORT
      LAYER M4 ;
        RECT  21.516 26.352 21.6 26.376 ;
    END
  END b[338]
  PIN b[339]
    DIRECTION OUTPUT ;
    USE SIGNAL ;
    PORT
      LAYER M4 ;
        RECT  21.516 26.496 21.6 26.52 ;
    END
  END b[339]
  PIN b[33]
    DIRECTION OUTPUT ;
    USE SIGNAL ;
    PORT
      LAYER M4 ;
        RECT  21.516 38.88 21.6 38.904 ;
    END
  END b[33]
  PIN b[340]
    DIRECTION OUTPUT ;
    USE SIGNAL ;
    PORT
      LAYER M4 ;
        RECT  21.516 26.64 21.6 26.664 ;
    END
  END b[340]
  PIN b[341]
    DIRECTION OUTPUT ;
    USE SIGNAL ;
    PORT
      LAYER M4 ;
        RECT  21.516 26.784 21.6 26.808 ;
    END
  END b[341]
  PIN b[342]
    DIRECTION OUTPUT ;
    USE SIGNAL ;
    PORT
      LAYER M4 ;
        RECT  21.516 26.928 21.6 26.952 ;
    END
  END b[342]
  PIN b[343]
    DIRECTION OUTPUT ;
    USE SIGNAL ;
    PORT
      LAYER M4 ;
        RECT  21.516 27.072 21.6 27.096 ;
    END
  END b[343]
  PIN b[344]
    DIRECTION OUTPUT ;
    USE SIGNAL ;
    PORT
      LAYER M4 ;
        RECT  21.516 27.216 21.6 27.24 ;
    END
  END b[344]
  PIN b[345]
    DIRECTION OUTPUT ;
    USE SIGNAL ;
    PORT
      LAYER M4 ;
        RECT  21.516 27.36 21.6 27.384 ;
    END
  END b[345]
  PIN b[346]
    DIRECTION OUTPUT ;
    USE SIGNAL ;
    PORT
      LAYER M4 ;
        RECT  21.516 27.504 21.6 27.528 ;
    END
  END b[346]
  PIN b[347]
    DIRECTION OUTPUT ;
    USE SIGNAL ;
    PORT
      LAYER M4 ;
        RECT  21.516 27.648 21.6 27.672 ;
    END
  END b[347]
  PIN b[348]
    DIRECTION OUTPUT ;
    USE SIGNAL ;
    PORT
      LAYER M4 ;
        RECT  21.516 27.792 21.6 27.816 ;
    END
  END b[348]
  PIN b[349]
    DIRECTION OUTPUT ;
    USE SIGNAL ;
    PORT
      LAYER M4 ;
        RECT  21.516 27.936 21.6 27.96 ;
    END
  END b[349]
  PIN b[34]
    DIRECTION OUTPUT ;
    USE SIGNAL ;
    PORT
      LAYER M4 ;
        RECT  21.516 39.024 21.6 39.048 ;
    END
  END b[34]
  PIN b[350]
    DIRECTION OUTPUT ;
    USE SIGNAL ;
    PORT
      LAYER M4 ;
        RECT  21.516 28.08 21.6 28.104 ;
    END
  END b[350]
  PIN b[351]
    DIRECTION OUTPUT ;
    USE SIGNAL ;
    PORT
      LAYER M4 ;
        RECT  21.516 28.224 21.6 28.248 ;
    END
  END b[351]
  PIN b[352]
    DIRECTION OUTPUT ;
    USE SIGNAL ;
    PORT
      LAYER M4 ;
        RECT  21.516 0.72 21.6 0.744 ;
    END
  END b[352]
  PIN b[353]
    DIRECTION OUTPUT ;
    USE SIGNAL ;
    PORT
      LAYER M4 ;
        RECT  21.516 0.864 21.6 0.888 ;
    END
  END b[353]
  PIN b[354]
    DIRECTION OUTPUT ;
    USE SIGNAL ;
    PORT
      LAYER M4 ;
        RECT  21.516 1.008 21.6 1.032 ;
    END
  END b[354]
  PIN b[355]
    DIRECTION OUTPUT ;
    USE SIGNAL ;
    PORT
      LAYER M4 ;
        RECT  21.516 1.152 21.6 1.176 ;
    END
  END b[355]
  PIN b[356]
    DIRECTION OUTPUT ;
    USE SIGNAL ;
    PORT
      LAYER M4 ;
        RECT  21.516 1.296 21.6 1.32 ;
    END
  END b[356]
  PIN b[357]
    DIRECTION OUTPUT ;
    USE SIGNAL ;
    PORT
      LAYER M4 ;
        RECT  21.516 1.44 21.6 1.464 ;
    END
  END b[357]
  PIN b[358]
    DIRECTION OUTPUT ;
    USE SIGNAL ;
    PORT
      LAYER M4 ;
        RECT  21.516 1.584 21.6 1.608 ;
    END
  END b[358]
  PIN b[359]
    DIRECTION OUTPUT ;
    USE SIGNAL ;
    PORT
      LAYER M4 ;
        RECT  21.516 1.728 21.6 1.752 ;
    END
  END b[359]
  PIN b[35]
    DIRECTION OUTPUT ;
    USE SIGNAL ;
    PORT
      LAYER M4 ;
        RECT  21.516 39.168 21.6 39.192 ;
    END
  END b[35]
  PIN b[360]
    DIRECTION OUTPUT ;
    USE SIGNAL ;
    PORT
      LAYER M4 ;
        RECT  21.516 1.872 21.6 1.896 ;
    END
  END b[360]
  PIN b[361]
    DIRECTION OUTPUT ;
    USE SIGNAL ;
    PORT
      LAYER M4 ;
        RECT  21.516 2.016 21.6 2.04 ;
    END
  END b[361]
  PIN b[362]
    DIRECTION OUTPUT ;
    USE SIGNAL ;
    PORT
      LAYER M4 ;
        RECT  21.516 2.16 21.6 2.184 ;
    END
  END b[362]
  PIN b[363]
    DIRECTION OUTPUT ;
    USE SIGNAL ;
    PORT
      LAYER M4 ;
        RECT  21.516 2.304 21.6 2.328 ;
    END
  END b[363]
  PIN b[364]
    DIRECTION OUTPUT ;
    USE SIGNAL ;
    PORT
      LAYER M4 ;
        RECT  21.516 2.448 21.6 2.472 ;
    END
  END b[364]
  PIN b[365]
    DIRECTION OUTPUT ;
    USE SIGNAL ;
    PORT
      LAYER M4 ;
        RECT  21.516 2.592 21.6 2.616 ;
    END
  END b[365]
  PIN b[366]
    DIRECTION OUTPUT ;
    USE SIGNAL ;
    PORT
      LAYER M4 ;
        RECT  21.516 2.736 21.6 2.76 ;
    END
  END b[366]
  PIN b[367]
    DIRECTION OUTPUT ;
    USE SIGNAL ;
    PORT
      LAYER M4 ;
        RECT  21.516 2.88 21.6 2.904 ;
    END
  END b[367]
  PIN b[368]
    DIRECTION OUTPUT ;
    USE SIGNAL ;
    PORT
      LAYER M4 ;
        RECT  21.516 3.024 21.6 3.048 ;
    END
  END b[368]
  PIN b[369]
    DIRECTION OUTPUT ;
    USE SIGNAL ;
    PORT
      LAYER M4 ;
        RECT  21.516 3.168 21.6 3.192 ;
    END
  END b[369]
  PIN b[36]
    DIRECTION OUTPUT ;
    USE SIGNAL ;
    PORT
      LAYER M4 ;
        RECT  21.516 39.312 21.6 39.336 ;
    END
  END b[36]
  PIN b[370]
    DIRECTION OUTPUT ;
    USE SIGNAL ;
    PORT
      LAYER M4 ;
        RECT  21.516 3.312 21.6 3.336 ;
    END
  END b[370]
  PIN b[371]
    DIRECTION OUTPUT ;
    USE SIGNAL ;
    PORT
      LAYER M4 ;
        RECT  21.516 3.456 21.6 3.48 ;
    END
  END b[371]
  PIN b[372]
    DIRECTION OUTPUT ;
    USE SIGNAL ;
    PORT
      LAYER M4 ;
        RECT  21.516 3.6 21.6 3.624 ;
    END
  END b[372]
  PIN b[373]
    DIRECTION OUTPUT ;
    USE SIGNAL ;
    PORT
      LAYER M4 ;
        RECT  21.516 3.744 21.6 3.768 ;
    END
  END b[373]
  PIN b[374]
    DIRECTION OUTPUT ;
    USE SIGNAL ;
    PORT
      LAYER M4 ;
        RECT  21.516 3.888 21.6 3.912 ;
    END
  END b[374]
  PIN b[375]
    DIRECTION OUTPUT ;
    USE SIGNAL ;
    PORT
      LAYER M4 ;
        RECT  21.516 4.032 21.6 4.056 ;
    END
  END b[375]
  PIN b[376]
    DIRECTION OUTPUT ;
    USE SIGNAL ;
    PORT
      LAYER M4 ;
        RECT  21.516 4.176 21.6 4.2 ;
    END
  END b[376]
  PIN b[377]
    DIRECTION OUTPUT ;
    USE SIGNAL ;
    PORT
      LAYER M4 ;
        RECT  21.516 4.32 21.6 4.344 ;
    END
  END b[377]
  PIN b[378]
    DIRECTION OUTPUT ;
    USE SIGNAL ;
    PORT
      LAYER M4 ;
        RECT  21.516 4.464 21.6 4.488 ;
    END
  END b[378]
  PIN b[379]
    DIRECTION OUTPUT ;
    USE SIGNAL ;
    PORT
      LAYER M4 ;
        RECT  21.516 4.608 21.6 4.632 ;
    END
  END b[379]
  PIN b[37]
    DIRECTION OUTPUT ;
    USE SIGNAL ;
    PORT
      LAYER M4 ;
        RECT  21.516 39.456 21.6 39.48 ;
    END
  END b[37]
  PIN b[380]
    DIRECTION OUTPUT ;
    USE SIGNAL ;
    PORT
      LAYER M4 ;
        RECT  21.516 4.752 21.6 4.776 ;
    END
  END b[380]
  PIN b[381]
    DIRECTION OUTPUT ;
    USE SIGNAL ;
    PORT
      LAYER M4 ;
        RECT  21.516 4.896 21.6 4.92 ;
    END
  END b[381]
  PIN b[382]
    DIRECTION OUTPUT ;
    USE SIGNAL ;
    PORT
      LAYER M4 ;
        RECT  21.516 5.04 21.6 5.064 ;
    END
  END b[382]
  PIN b[383]
    DIRECTION OUTPUT ;
    USE SIGNAL ;
    PORT
      LAYER M4 ;
        RECT  21.516 5.184 21.6 5.208 ;
    END
  END b[383]
  PIN b[384]
    DIRECTION OUTPUT ;
    USE SIGNAL ;
    PORT
      LAYER M4 ;
        RECT  21.516 72.144 21.6 72.168 ;
    END
  END b[384]
  PIN b[385]
    DIRECTION OUTPUT ;
    USE SIGNAL ;
    PORT
      LAYER M4 ;
        RECT  21.516 72.288 21.6 72.312 ;
    END
  END b[385]
  PIN b[386]
    DIRECTION OUTPUT ;
    USE SIGNAL ;
    PORT
      LAYER M4 ;
        RECT  21.516 72.432 21.6 72.456 ;
    END
  END b[386]
  PIN b[387]
    DIRECTION OUTPUT ;
    USE SIGNAL ;
    PORT
      LAYER M4 ;
        RECT  21.516 72.576 21.6 72.6 ;
    END
  END b[387]
  PIN b[388]
    DIRECTION OUTPUT ;
    USE SIGNAL ;
    PORT
      LAYER M4 ;
        RECT  21.516 72.72 21.6 72.744 ;
    END
  END b[388]
  PIN b[389]
    DIRECTION OUTPUT ;
    USE SIGNAL ;
    PORT
      LAYER M4 ;
        RECT  21.516 72.864 21.6 72.888 ;
    END
  END b[389]
  PIN b[38]
    DIRECTION OUTPUT ;
    USE SIGNAL ;
    PORT
      LAYER M4 ;
        RECT  21.516 39.6 21.6 39.624 ;
    END
  END b[38]
  PIN b[390]
    DIRECTION OUTPUT ;
    USE SIGNAL ;
    PORT
      LAYER M4 ;
        RECT  21.516 73.008 21.6 73.032 ;
    END
  END b[390]
  PIN b[391]
    DIRECTION OUTPUT ;
    USE SIGNAL ;
    PORT
      LAYER M4 ;
        RECT  21.516 73.152 21.6 73.176 ;
    END
  END b[391]
  PIN b[392]
    DIRECTION OUTPUT ;
    USE SIGNAL ;
    PORT
      LAYER M4 ;
        RECT  21.516 73.296 21.6 73.32 ;
    END
  END b[392]
  PIN b[393]
    DIRECTION OUTPUT ;
    USE SIGNAL ;
    PORT
      LAYER M4 ;
        RECT  21.516 73.44 21.6 73.464 ;
    END
  END b[393]
  PIN b[394]
    DIRECTION OUTPUT ;
    USE SIGNAL ;
    PORT
      LAYER M4 ;
        RECT  21.516 73.584 21.6 73.608 ;
    END
  END b[394]
  PIN b[395]
    DIRECTION OUTPUT ;
    USE SIGNAL ;
    PORT
      LAYER M4 ;
        RECT  21.516 73.728 21.6 73.752 ;
    END
  END b[395]
  PIN b[396]
    DIRECTION OUTPUT ;
    USE SIGNAL ;
    PORT
      LAYER M4 ;
        RECT  21.516 73.872 21.6 73.896 ;
    END
  END b[396]
  PIN b[397]
    DIRECTION OUTPUT ;
    USE SIGNAL ;
    PORT
      LAYER M4 ;
        RECT  21.516 74.016 21.6 74.04 ;
    END
  END b[397]
  PIN b[398]
    DIRECTION OUTPUT ;
    USE SIGNAL ;
    PORT
      LAYER M4 ;
        RECT  21.516 74.16 21.6 74.184 ;
    END
  END b[398]
  PIN b[399]
    DIRECTION OUTPUT ;
    USE SIGNAL ;
    PORT
      LAYER M4 ;
        RECT  21.516 74.304 21.6 74.328 ;
    END
  END b[399]
  PIN b[39]
    DIRECTION OUTPUT ;
    USE SIGNAL ;
    PORT
      LAYER M4 ;
        RECT  21.516 39.744 21.6 39.768 ;
    END
  END b[39]
  PIN b[3]
    DIRECTION OUTPUT ;
    USE SIGNAL ;
    PORT
      LAYER M4 ;
        RECT  21.516 29.952 21.6 29.976 ;
    END
  END b[3]
  PIN b[400]
    DIRECTION OUTPUT ;
    USE SIGNAL ;
    PORT
      LAYER M4 ;
        RECT  21.516 74.448 21.6 74.472 ;
    END
  END b[400]
  PIN b[401]
    DIRECTION OUTPUT ;
    USE SIGNAL ;
    PORT
      LAYER M4 ;
        RECT  21.516 74.592 21.6 74.616 ;
    END
  END b[401]
  PIN b[402]
    DIRECTION OUTPUT ;
    USE SIGNAL ;
    PORT
      LAYER M4 ;
        RECT  21.516 74.736 21.6 74.76 ;
    END
  END b[402]
  PIN b[403]
    DIRECTION OUTPUT ;
    USE SIGNAL ;
    PORT
      LAYER M4 ;
        RECT  21.516 74.88 21.6 74.904 ;
    END
  END b[403]
  PIN b[404]
    DIRECTION OUTPUT ;
    USE SIGNAL ;
    PORT
      LAYER M4 ;
        RECT  21.516 75.024 21.6 75.048 ;
    END
  END b[404]
  PIN b[405]
    DIRECTION OUTPUT ;
    USE SIGNAL ;
    PORT
      LAYER M4 ;
        RECT  21.516 75.168 21.6 75.192 ;
    END
  END b[405]
  PIN b[406]
    DIRECTION OUTPUT ;
    USE SIGNAL ;
    PORT
      LAYER M4 ;
        RECT  21.516 75.312 21.6 75.336 ;
    END
  END b[406]
  PIN b[407]
    DIRECTION OUTPUT ;
    USE SIGNAL ;
    PORT
      LAYER M4 ;
        RECT  21.516 75.456 21.6 75.48 ;
    END
  END b[407]
  PIN b[408]
    DIRECTION OUTPUT ;
    USE SIGNAL ;
    PORT
      LAYER M4 ;
        RECT  21.516 75.6 21.6 75.624 ;
    END
  END b[408]
  PIN b[409]
    DIRECTION OUTPUT ;
    USE SIGNAL ;
    PORT
      LAYER M4 ;
        RECT  21.516 75.744 21.6 75.768 ;
    END
  END b[409]
  PIN b[40]
    DIRECTION OUTPUT ;
    USE SIGNAL ;
    PORT
      LAYER M4 ;
        RECT  21.516 39.888 21.6 39.912 ;
    END
  END b[40]
  PIN b[410]
    DIRECTION OUTPUT ;
    USE SIGNAL ;
    PORT
      LAYER M4 ;
        RECT  21.516 75.888 21.6 75.912 ;
    END
  END b[410]
  PIN b[411]
    DIRECTION OUTPUT ;
    USE SIGNAL ;
    PORT
      LAYER M4 ;
        RECT  21.516 76.032 21.6 76.056 ;
    END
  END b[411]
  PIN b[412]
    DIRECTION OUTPUT ;
    USE SIGNAL ;
    PORT
      LAYER M4 ;
        RECT  21.516 76.176 21.6 76.2 ;
    END
  END b[412]
  PIN b[413]
    DIRECTION OUTPUT ;
    USE SIGNAL ;
    PORT
      LAYER M4 ;
        RECT  21.516 76.32 21.6 76.344 ;
    END
  END b[413]
  PIN b[414]
    DIRECTION OUTPUT ;
    USE SIGNAL ;
    PORT
      LAYER M4 ;
        RECT  21.516 76.464 21.6 76.488 ;
    END
  END b[414]
  PIN b[415]
    DIRECTION OUTPUT ;
    USE SIGNAL ;
    PORT
      LAYER M4 ;
        RECT  21.516 76.608 21.6 76.632 ;
    END
  END b[415]
  PIN b[416]
    DIRECTION OUTPUT ;
    USE SIGNAL ;
    PORT
      LAYER M4 ;
        RECT  21.516 67.536 21.6 67.56 ;
    END
  END b[416]
  PIN b[417]
    DIRECTION OUTPUT ;
    USE SIGNAL ;
    PORT
      LAYER M4 ;
        RECT  21.516 67.68 21.6 67.704 ;
    END
  END b[417]
  PIN b[418]
    DIRECTION OUTPUT ;
    USE SIGNAL ;
    PORT
      LAYER M4 ;
        RECT  21.516 67.824 21.6 67.848 ;
    END
  END b[418]
  PIN b[419]
    DIRECTION OUTPUT ;
    USE SIGNAL ;
    PORT
      LAYER M4 ;
        RECT  21.516 67.968 21.6 67.992 ;
    END
  END b[419]
  PIN b[41]
    DIRECTION OUTPUT ;
    USE SIGNAL ;
    PORT
      LAYER M4 ;
        RECT  21.516 40.032 21.6 40.056 ;
    END
  END b[41]
  PIN b[420]
    DIRECTION OUTPUT ;
    USE SIGNAL ;
    PORT
      LAYER M4 ;
        RECT  21.516 68.112 21.6 68.136 ;
    END
  END b[420]
  PIN b[421]
    DIRECTION OUTPUT ;
    USE SIGNAL ;
    PORT
      LAYER M4 ;
        RECT  21.516 68.256 21.6 68.28 ;
    END
  END b[421]
  PIN b[422]
    DIRECTION OUTPUT ;
    USE SIGNAL ;
    PORT
      LAYER M4 ;
        RECT  21.516 68.4 21.6 68.424 ;
    END
  END b[422]
  PIN b[423]
    DIRECTION OUTPUT ;
    USE SIGNAL ;
    PORT
      LAYER M4 ;
        RECT  21.516 68.544 21.6 68.568 ;
    END
  END b[423]
  PIN b[424]
    DIRECTION OUTPUT ;
    USE SIGNAL ;
    PORT
      LAYER M4 ;
        RECT  21.516 68.688 21.6 68.712 ;
    END
  END b[424]
  PIN b[425]
    DIRECTION OUTPUT ;
    USE SIGNAL ;
    PORT
      LAYER M4 ;
        RECT  21.516 68.832 21.6 68.856 ;
    END
  END b[425]
  PIN b[426]
    DIRECTION OUTPUT ;
    USE SIGNAL ;
    PORT
      LAYER M4 ;
        RECT  21.516 68.976 21.6 69 ;
    END
  END b[426]
  PIN b[427]
    DIRECTION OUTPUT ;
    USE SIGNAL ;
    PORT
      LAYER M4 ;
        RECT  21.516 69.12 21.6 69.144 ;
    END
  END b[427]
  PIN b[428]
    DIRECTION OUTPUT ;
    USE SIGNAL ;
    PORT
      LAYER M4 ;
        RECT  21.516 69.264 21.6 69.288 ;
    END
  END b[428]
  PIN b[429]
    DIRECTION OUTPUT ;
    USE SIGNAL ;
    PORT
      LAYER M4 ;
        RECT  21.516 69.408 21.6 69.432 ;
    END
  END b[429]
  PIN b[42]
    DIRECTION OUTPUT ;
    USE SIGNAL ;
    PORT
      LAYER M4 ;
        RECT  21.516 40.176 21.6 40.2 ;
    END
  END b[42]
  PIN b[430]
    DIRECTION OUTPUT ;
    USE SIGNAL ;
    PORT
      LAYER M4 ;
        RECT  21.516 69.552 21.6 69.576 ;
    END
  END b[430]
  PIN b[431]
    DIRECTION OUTPUT ;
    USE SIGNAL ;
    PORT
      LAYER M4 ;
        RECT  21.516 69.696 21.6 69.72 ;
    END
  END b[431]
  PIN b[432]
    DIRECTION OUTPUT ;
    USE SIGNAL ;
    PORT
      LAYER M4 ;
        RECT  21.516 69.84 21.6 69.864 ;
    END
  END b[432]
  PIN b[433]
    DIRECTION OUTPUT ;
    USE SIGNAL ;
    PORT
      LAYER M4 ;
        RECT  21.516 69.984 21.6 70.008 ;
    END
  END b[433]
  PIN b[434]
    DIRECTION OUTPUT ;
    USE SIGNAL ;
    PORT
      LAYER M4 ;
        RECT  21.516 70.128 21.6 70.152 ;
    END
  END b[434]
  PIN b[435]
    DIRECTION OUTPUT ;
    USE SIGNAL ;
    PORT
      LAYER M4 ;
        RECT  21.516 70.272 21.6 70.296 ;
    END
  END b[435]
  PIN b[436]
    DIRECTION OUTPUT ;
    USE SIGNAL ;
    PORT
      LAYER M4 ;
        RECT  21.516 70.416 21.6 70.44 ;
    END
  END b[436]
  PIN b[437]
    DIRECTION OUTPUT ;
    USE SIGNAL ;
    PORT
      LAYER M4 ;
        RECT  21.516 70.56 21.6 70.584 ;
    END
  END b[437]
  PIN b[438]
    DIRECTION OUTPUT ;
    USE SIGNAL ;
    PORT
      LAYER M4 ;
        RECT  21.516 70.704 21.6 70.728 ;
    END
  END b[438]
  PIN b[439]
    DIRECTION OUTPUT ;
    USE SIGNAL ;
    PORT
      LAYER M4 ;
        RECT  21.516 70.848 21.6 70.872 ;
    END
  END b[439]
  PIN b[43]
    DIRECTION OUTPUT ;
    USE SIGNAL ;
    PORT
      LAYER M4 ;
        RECT  21.516 40.32 21.6 40.344 ;
    END
  END b[43]
  PIN b[440]
    DIRECTION OUTPUT ;
    USE SIGNAL ;
    PORT
      LAYER M4 ;
        RECT  21.516 70.992 21.6 71.016 ;
    END
  END b[440]
  PIN b[441]
    DIRECTION OUTPUT ;
    USE SIGNAL ;
    PORT
      LAYER M4 ;
        RECT  21.516 71.136 21.6 71.16 ;
    END
  END b[441]
  PIN b[442]
    DIRECTION OUTPUT ;
    USE SIGNAL ;
    PORT
      LAYER M4 ;
        RECT  21.516 71.28 21.6 71.304 ;
    END
  END b[442]
  PIN b[443]
    DIRECTION OUTPUT ;
    USE SIGNAL ;
    PORT
      LAYER M4 ;
        RECT  21.516 71.424 21.6 71.448 ;
    END
  END b[443]
  PIN b[444]
    DIRECTION OUTPUT ;
    USE SIGNAL ;
    PORT
      LAYER M4 ;
        RECT  21.516 71.568 21.6 71.592 ;
    END
  END b[444]
  PIN b[445]
    DIRECTION OUTPUT ;
    USE SIGNAL ;
    PORT
      LAYER M4 ;
        RECT  21.516 71.712 21.6 71.736 ;
    END
  END b[445]
  PIN b[446]
    DIRECTION OUTPUT ;
    USE SIGNAL ;
    PORT
      LAYER M4 ;
        RECT  21.516 71.856 21.6 71.88 ;
    END
  END b[446]
  PIN b[447]
    DIRECTION OUTPUT ;
    USE SIGNAL ;
    PORT
      LAYER M4 ;
        RECT  21.516 72 21.6 72.024 ;
    END
  END b[447]
  PIN b[448]
    DIRECTION OUTPUT ;
    USE SIGNAL ;
    PORT
      LAYER M4 ;
        RECT  21.516 62.928 21.6 62.952 ;
    END
  END b[448]
  PIN b[449]
    DIRECTION OUTPUT ;
    USE SIGNAL ;
    PORT
      LAYER M4 ;
        RECT  21.516 63.072 21.6 63.096 ;
    END
  END b[449]
  PIN b[44]
    DIRECTION OUTPUT ;
    USE SIGNAL ;
    PORT
      LAYER M4 ;
        RECT  21.516 40.464 21.6 40.488 ;
    END
  END b[44]
  PIN b[450]
    DIRECTION OUTPUT ;
    USE SIGNAL ;
    PORT
      LAYER M4 ;
        RECT  21.516 63.216 21.6 63.24 ;
    END
  END b[450]
  PIN b[451]
    DIRECTION OUTPUT ;
    USE SIGNAL ;
    PORT
      LAYER M4 ;
        RECT  21.516 63.36 21.6 63.384 ;
    END
  END b[451]
  PIN b[452]
    DIRECTION OUTPUT ;
    USE SIGNAL ;
    PORT
      LAYER M4 ;
        RECT  21.516 63.504 21.6 63.528 ;
    END
  END b[452]
  PIN b[453]
    DIRECTION OUTPUT ;
    USE SIGNAL ;
    PORT
      LAYER M4 ;
        RECT  21.516 63.648 21.6 63.672 ;
    END
  END b[453]
  PIN b[454]
    DIRECTION OUTPUT ;
    USE SIGNAL ;
    PORT
      LAYER M4 ;
        RECT  21.516 63.792 21.6 63.816 ;
    END
  END b[454]
  PIN b[455]
    DIRECTION OUTPUT ;
    USE SIGNAL ;
    PORT
      LAYER M4 ;
        RECT  21.516 63.936 21.6 63.96 ;
    END
  END b[455]
  PIN b[456]
    DIRECTION OUTPUT ;
    USE SIGNAL ;
    PORT
      LAYER M4 ;
        RECT  21.516 64.08 21.6 64.104 ;
    END
  END b[456]
  PIN b[457]
    DIRECTION OUTPUT ;
    USE SIGNAL ;
    PORT
      LAYER M4 ;
        RECT  21.516 64.224 21.6 64.248 ;
    END
  END b[457]
  PIN b[458]
    DIRECTION OUTPUT ;
    USE SIGNAL ;
    PORT
      LAYER M4 ;
        RECT  21.516 64.368 21.6 64.392 ;
    END
  END b[458]
  PIN b[459]
    DIRECTION OUTPUT ;
    USE SIGNAL ;
    PORT
      LAYER M4 ;
        RECT  21.516 64.512 21.6 64.536 ;
    END
  END b[459]
  PIN b[45]
    DIRECTION OUTPUT ;
    USE SIGNAL ;
    PORT
      LAYER M4 ;
        RECT  21.516 40.608 21.6 40.632 ;
    END
  END b[45]
  PIN b[460]
    DIRECTION OUTPUT ;
    USE SIGNAL ;
    PORT
      LAYER M4 ;
        RECT  21.516 64.656 21.6 64.68 ;
    END
  END b[460]
  PIN b[461]
    DIRECTION OUTPUT ;
    USE SIGNAL ;
    PORT
      LAYER M4 ;
        RECT  21.516 64.8 21.6 64.824 ;
    END
  END b[461]
  PIN b[462]
    DIRECTION OUTPUT ;
    USE SIGNAL ;
    PORT
      LAYER M4 ;
        RECT  21.516 64.944 21.6 64.968 ;
    END
  END b[462]
  PIN b[463]
    DIRECTION OUTPUT ;
    USE SIGNAL ;
    PORT
      LAYER M4 ;
        RECT  21.516 65.088 21.6 65.112 ;
    END
  END b[463]
  PIN b[464]
    DIRECTION OUTPUT ;
    USE SIGNAL ;
    PORT
      LAYER M4 ;
        RECT  21.516 65.232 21.6 65.256 ;
    END
  END b[464]
  PIN b[465]
    DIRECTION OUTPUT ;
    USE SIGNAL ;
    PORT
      LAYER M4 ;
        RECT  21.516 65.376 21.6 65.4 ;
    END
  END b[465]
  PIN b[466]
    DIRECTION OUTPUT ;
    USE SIGNAL ;
    PORT
      LAYER M4 ;
        RECT  21.516 65.52 21.6 65.544 ;
    END
  END b[466]
  PIN b[467]
    DIRECTION OUTPUT ;
    USE SIGNAL ;
    PORT
      LAYER M4 ;
        RECT  21.516 65.664 21.6 65.688 ;
    END
  END b[467]
  PIN b[468]
    DIRECTION OUTPUT ;
    USE SIGNAL ;
    PORT
      LAYER M4 ;
        RECT  21.516 65.808 21.6 65.832 ;
    END
  END b[468]
  PIN b[469]
    DIRECTION OUTPUT ;
    USE SIGNAL ;
    PORT
      LAYER M4 ;
        RECT  21.516 65.952 21.6 65.976 ;
    END
  END b[469]
  PIN b[46]
    DIRECTION OUTPUT ;
    USE SIGNAL ;
    PORT
      LAYER M4 ;
        RECT  21.516 40.752 21.6 40.776 ;
    END
  END b[46]
  PIN b[470]
    DIRECTION OUTPUT ;
    USE SIGNAL ;
    PORT
      LAYER M4 ;
        RECT  21.516 66.096 21.6 66.12 ;
    END
  END b[470]
  PIN b[471]
    DIRECTION OUTPUT ;
    USE SIGNAL ;
    PORT
      LAYER M4 ;
        RECT  21.516 66.24 21.6 66.264 ;
    END
  END b[471]
  PIN b[472]
    DIRECTION OUTPUT ;
    USE SIGNAL ;
    PORT
      LAYER M4 ;
        RECT  21.516 66.384 21.6 66.408 ;
    END
  END b[472]
  PIN b[473]
    DIRECTION OUTPUT ;
    USE SIGNAL ;
    PORT
      LAYER M4 ;
        RECT  21.516 66.528 21.6 66.552 ;
    END
  END b[473]
  PIN b[474]
    DIRECTION OUTPUT ;
    USE SIGNAL ;
    PORT
      LAYER M4 ;
        RECT  21.516 66.672 21.6 66.696 ;
    END
  END b[474]
  PIN b[475]
    DIRECTION OUTPUT ;
    USE SIGNAL ;
    PORT
      LAYER M4 ;
        RECT  21.516 66.816 21.6 66.84 ;
    END
  END b[475]
  PIN b[476]
    DIRECTION OUTPUT ;
    USE SIGNAL ;
    PORT
      LAYER M4 ;
        RECT  21.516 66.96 21.6 66.984 ;
    END
  END b[476]
  PIN b[477]
    DIRECTION OUTPUT ;
    USE SIGNAL ;
    PORT
      LAYER M4 ;
        RECT  21.516 67.104 21.6 67.128 ;
    END
  END b[477]
  PIN b[478]
    DIRECTION OUTPUT ;
    USE SIGNAL ;
    PORT
      LAYER M4 ;
        RECT  21.516 67.248 21.6 67.272 ;
    END
  END b[478]
  PIN b[479]
    DIRECTION OUTPUT ;
    USE SIGNAL ;
    PORT
      LAYER M4 ;
        RECT  21.516 67.392 21.6 67.416 ;
    END
  END b[479]
  PIN b[47]
    DIRECTION OUTPUT ;
    USE SIGNAL ;
    PORT
      LAYER M4 ;
        RECT  21.516 40.896 21.6 40.92 ;
    END
  END b[47]
  PIN b[480]
    DIRECTION OUTPUT ;
    USE SIGNAL ;
    PORT
      LAYER M4 ;
        RECT  21.516 58.32 21.6 58.344 ;
    END
  END b[480]
  PIN b[481]
    DIRECTION OUTPUT ;
    USE SIGNAL ;
    PORT
      LAYER M4 ;
        RECT  21.516 58.464 21.6 58.488 ;
    END
  END b[481]
  PIN b[482]
    DIRECTION OUTPUT ;
    USE SIGNAL ;
    PORT
      LAYER M4 ;
        RECT  21.516 58.608 21.6 58.632 ;
    END
  END b[482]
  PIN b[483]
    DIRECTION OUTPUT ;
    USE SIGNAL ;
    PORT
      LAYER M4 ;
        RECT  21.516 58.752 21.6 58.776 ;
    END
  END b[483]
  PIN b[484]
    DIRECTION OUTPUT ;
    USE SIGNAL ;
    PORT
      LAYER M4 ;
        RECT  21.516 58.896 21.6 58.92 ;
    END
  END b[484]
  PIN b[485]
    DIRECTION OUTPUT ;
    USE SIGNAL ;
    PORT
      LAYER M4 ;
        RECT  21.516 59.04 21.6 59.064 ;
    END
  END b[485]
  PIN b[486]
    DIRECTION OUTPUT ;
    USE SIGNAL ;
    PORT
      LAYER M4 ;
        RECT  21.516 59.184 21.6 59.208 ;
    END
  END b[486]
  PIN b[487]
    DIRECTION OUTPUT ;
    USE SIGNAL ;
    PORT
      LAYER M4 ;
        RECT  21.516 59.328 21.6 59.352 ;
    END
  END b[487]
  PIN b[488]
    DIRECTION OUTPUT ;
    USE SIGNAL ;
    PORT
      LAYER M4 ;
        RECT  21.516 59.472 21.6 59.496 ;
    END
  END b[488]
  PIN b[489]
    DIRECTION OUTPUT ;
    USE SIGNAL ;
    PORT
      LAYER M4 ;
        RECT  21.516 59.616 21.6 59.64 ;
    END
  END b[489]
  PIN b[48]
    DIRECTION OUTPUT ;
    USE SIGNAL ;
    PORT
      LAYER M4 ;
        RECT  21.516 41.04 21.6 41.064 ;
    END
  END b[48]
  PIN b[490]
    DIRECTION OUTPUT ;
    USE SIGNAL ;
    PORT
      LAYER M4 ;
        RECT  21.516 59.76 21.6 59.784 ;
    END
  END b[490]
  PIN b[491]
    DIRECTION OUTPUT ;
    USE SIGNAL ;
    PORT
      LAYER M4 ;
        RECT  21.516 59.904 21.6 59.928 ;
    END
  END b[491]
  PIN b[492]
    DIRECTION OUTPUT ;
    USE SIGNAL ;
    PORT
      LAYER M4 ;
        RECT  21.516 60.048 21.6 60.072 ;
    END
  END b[492]
  PIN b[493]
    DIRECTION OUTPUT ;
    USE SIGNAL ;
    PORT
      LAYER M4 ;
        RECT  21.516 60.192 21.6 60.216 ;
    END
  END b[493]
  PIN b[494]
    DIRECTION OUTPUT ;
    USE SIGNAL ;
    PORT
      LAYER M4 ;
        RECT  21.516 60.336 21.6 60.36 ;
    END
  END b[494]
  PIN b[495]
    DIRECTION OUTPUT ;
    USE SIGNAL ;
    PORT
      LAYER M4 ;
        RECT  21.516 60.48 21.6 60.504 ;
    END
  END b[495]
  PIN b[496]
    DIRECTION OUTPUT ;
    USE SIGNAL ;
    PORT
      LAYER M4 ;
        RECT  21.516 60.624 21.6 60.648 ;
    END
  END b[496]
  PIN b[497]
    DIRECTION OUTPUT ;
    USE SIGNAL ;
    PORT
      LAYER M4 ;
        RECT  21.516 60.768 21.6 60.792 ;
    END
  END b[497]
  PIN b[498]
    DIRECTION OUTPUT ;
    USE SIGNAL ;
    PORT
      LAYER M4 ;
        RECT  21.516 60.912 21.6 60.936 ;
    END
  END b[498]
  PIN b[499]
    DIRECTION OUTPUT ;
    USE SIGNAL ;
    PORT
      LAYER M4 ;
        RECT  21.516 61.056 21.6 61.08 ;
    END
  END b[499]
  PIN b[49]
    DIRECTION OUTPUT ;
    USE SIGNAL ;
    PORT
      LAYER M4 ;
        RECT  21.516 41.184 21.6 41.208 ;
    END
  END b[49]
  PIN b[4]
    DIRECTION OUTPUT ;
    USE SIGNAL ;
    PORT
      LAYER M4 ;
        RECT  21.516 30.096 21.6 30.12 ;
    END
  END b[4]
  PIN b[500]
    DIRECTION OUTPUT ;
    USE SIGNAL ;
    PORT
      LAYER M4 ;
        RECT  21.516 61.2 21.6 61.224 ;
    END
  END b[500]
  PIN b[501]
    DIRECTION OUTPUT ;
    USE SIGNAL ;
    PORT
      LAYER M4 ;
        RECT  21.516 61.344 21.6 61.368 ;
    END
  END b[501]
  PIN b[502]
    DIRECTION OUTPUT ;
    USE SIGNAL ;
    PORT
      LAYER M4 ;
        RECT  21.516 61.488 21.6 61.512 ;
    END
  END b[502]
  PIN b[503]
    DIRECTION OUTPUT ;
    USE SIGNAL ;
    PORT
      LAYER M4 ;
        RECT  21.516 61.632 21.6 61.656 ;
    END
  END b[503]
  PIN b[504]
    DIRECTION OUTPUT ;
    USE SIGNAL ;
    PORT
      LAYER M4 ;
        RECT  21.516 61.776 21.6 61.8 ;
    END
  END b[504]
  PIN b[505]
    DIRECTION OUTPUT ;
    USE SIGNAL ;
    PORT
      LAYER M4 ;
        RECT  21.516 61.92 21.6 61.944 ;
    END
  END b[505]
  PIN b[506]
    DIRECTION OUTPUT ;
    USE SIGNAL ;
    PORT
      LAYER M4 ;
        RECT  21.516 62.064 21.6 62.088 ;
    END
  END b[506]
  PIN b[507]
    DIRECTION OUTPUT ;
    USE SIGNAL ;
    PORT
      LAYER M4 ;
        RECT  21.516 62.208 21.6 62.232 ;
    END
  END b[507]
  PIN b[508]
    DIRECTION OUTPUT ;
    USE SIGNAL ;
    PORT
      LAYER M4 ;
        RECT  21.516 62.352 21.6 62.376 ;
    END
  END b[508]
  PIN b[509]
    DIRECTION OUTPUT ;
    USE SIGNAL ;
    PORT
      LAYER M4 ;
        RECT  21.516 62.496 21.6 62.52 ;
    END
  END b[509]
  PIN b[50]
    DIRECTION OUTPUT ;
    USE SIGNAL ;
    PORT
      LAYER M4 ;
        RECT  21.516 41.328 21.6 41.352 ;
    END
  END b[50]
  PIN b[510]
    DIRECTION OUTPUT ;
    USE SIGNAL ;
    PORT
      LAYER M4 ;
        RECT  21.516 62.64 21.6 62.664 ;
    END
  END b[510]
  PIN b[511]
    DIRECTION OUTPUT ;
    USE SIGNAL ;
    PORT
      LAYER M4 ;
        RECT  21.516 62.784 21.6 62.808 ;
    END
  END b[511]
  PIN b[512]
    DIRECTION OUTPUT ;
    USE SIGNAL ;
    PORT
      LAYER M4 ;
        RECT  21.516 76.752 21.6 76.776 ;
    END
  END b[512]
  PIN b[513]
    DIRECTION OUTPUT ;
    USE SIGNAL ;
    PORT
      LAYER M4 ;
        RECT  21.516 76.896 21.6 76.92 ;
    END
  END b[513]
  PIN b[514]
    DIRECTION OUTPUT ;
    USE SIGNAL ;
    PORT
      LAYER M4 ;
        RECT  21.516 77.04 21.6 77.064 ;
    END
  END b[514]
  PIN b[515]
    DIRECTION OUTPUT ;
    USE SIGNAL ;
    PORT
      LAYER M4 ;
        RECT  21.516 77.184 21.6 77.208 ;
    END
  END b[515]
  PIN b[516]
    DIRECTION OUTPUT ;
    USE SIGNAL ;
    PORT
      LAYER M4 ;
        RECT  21.516 77.328 21.6 77.352 ;
    END
  END b[516]
  PIN b[517]
    DIRECTION OUTPUT ;
    USE SIGNAL ;
    PORT
      LAYER M4 ;
        RECT  21.516 77.472 21.6 77.496 ;
    END
  END b[517]
  PIN b[518]
    DIRECTION OUTPUT ;
    USE SIGNAL ;
    PORT
      LAYER M4 ;
        RECT  21.516 77.616 21.6 77.64 ;
    END
  END b[518]
  PIN b[519]
    DIRECTION OUTPUT ;
    USE SIGNAL ;
    PORT
      LAYER M4 ;
        RECT  21.516 77.76 21.6 77.784 ;
    END
  END b[519]
  PIN b[51]
    DIRECTION OUTPUT ;
    USE SIGNAL ;
    PORT
      LAYER M4 ;
        RECT  21.516 41.472 21.6 41.496 ;
    END
  END b[51]
  PIN b[520]
    DIRECTION OUTPUT ;
    USE SIGNAL ;
    PORT
      LAYER M4 ;
        RECT  21.516 77.904 21.6 77.928 ;
    END
  END b[520]
  PIN b[521]
    DIRECTION OUTPUT ;
    USE SIGNAL ;
    PORT
      LAYER M4 ;
        RECT  21.516 78.048 21.6 78.072 ;
    END
  END b[521]
  PIN b[522]
    DIRECTION OUTPUT ;
    USE SIGNAL ;
    PORT
      LAYER M4 ;
        RECT  21.516 78.192 21.6 78.216 ;
    END
  END b[522]
  PIN b[523]
    DIRECTION OUTPUT ;
    USE SIGNAL ;
    PORT
      LAYER M4 ;
        RECT  21.516 78.336 21.6 78.36 ;
    END
  END b[523]
  PIN b[524]
    DIRECTION OUTPUT ;
    USE SIGNAL ;
    PORT
      LAYER M4 ;
        RECT  21.516 78.48 21.6 78.504 ;
    END
  END b[524]
  PIN b[525]
    DIRECTION OUTPUT ;
    USE SIGNAL ;
    PORT
      LAYER M4 ;
        RECT  21.516 78.624 21.6 78.648 ;
    END
  END b[525]
  PIN b[526]
    DIRECTION OUTPUT ;
    USE SIGNAL ;
    PORT
      LAYER M4 ;
        RECT  21.516 78.768 21.6 78.792 ;
    END
  END b[526]
  PIN b[527]
    DIRECTION OUTPUT ;
    USE SIGNAL ;
    PORT
      LAYER M4 ;
        RECT  21.516 78.912 21.6 78.936 ;
    END
  END b[527]
  PIN b[52]
    DIRECTION OUTPUT ;
    USE SIGNAL ;
    PORT
      LAYER M4 ;
        RECT  21.516 41.616 21.6 41.64 ;
    END
  END b[52]
  PIN b[53]
    DIRECTION OUTPUT ;
    USE SIGNAL ;
    PORT
      LAYER M4 ;
        RECT  21.516 41.76 21.6 41.784 ;
    END
  END b[53]
  PIN b[54]
    DIRECTION OUTPUT ;
    USE SIGNAL ;
    PORT
      LAYER M4 ;
        RECT  21.516 41.904 21.6 41.928 ;
    END
  END b[54]
  PIN b[55]
    DIRECTION OUTPUT ;
    USE SIGNAL ;
    PORT
      LAYER M4 ;
        RECT  21.516 42.048 21.6 42.072 ;
    END
  END b[55]
  PIN b[56]
    DIRECTION OUTPUT ;
    USE SIGNAL ;
    PORT
      LAYER M4 ;
        RECT  21.516 42.192 21.6 42.216 ;
    END
  END b[56]
  PIN b[57]
    DIRECTION OUTPUT ;
    USE SIGNAL ;
    PORT
      LAYER M4 ;
        RECT  21.516 42.336 21.6 42.36 ;
    END
  END b[57]
  PIN b[58]
    DIRECTION OUTPUT ;
    USE SIGNAL ;
    PORT
      LAYER M4 ;
        RECT  21.516 42.48 21.6 42.504 ;
    END
  END b[58]
  PIN b[59]
    DIRECTION OUTPUT ;
    USE SIGNAL ;
    PORT
      LAYER M4 ;
        RECT  21.516 42.624 21.6 42.648 ;
    END
  END b[59]
  PIN b[5]
    DIRECTION OUTPUT ;
    USE SIGNAL ;
    PORT
      LAYER M4 ;
        RECT  21.516 30.24 21.6 30.264 ;
    END
  END b[5]
  PIN b[60]
    DIRECTION OUTPUT ;
    USE SIGNAL ;
    PORT
      LAYER M4 ;
        RECT  21.516 42.768 21.6 42.792 ;
    END
  END b[60]
  PIN b[61]
    DIRECTION OUTPUT ;
    USE SIGNAL ;
    PORT
      LAYER M4 ;
        RECT  21.516 42.912 21.6 42.936 ;
    END
  END b[61]
  PIN b[62]
    DIRECTION OUTPUT ;
    USE SIGNAL ;
    PORT
      LAYER M4 ;
        RECT  21.516 43.056 21.6 43.08 ;
    END
  END b[62]
  PIN b[63]
    DIRECTION OUTPUT ;
    USE SIGNAL ;
    PORT
      LAYER M4 ;
        RECT  21.516 43.2 21.6 43.224 ;
    END
  END b[63]
  PIN b[64]
    DIRECTION OUTPUT ;
    USE SIGNAL ;
    PORT
      LAYER M4 ;
        RECT  21.516 52.56 21.6 52.584 ;
    END
  END b[64]
  PIN b[65]
    DIRECTION OUTPUT ;
    USE SIGNAL ;
    PORT
      LAYER M4 ;
        RECT  21.516 52.704 21.6 52.728 ;
    END
  END b[65]
  PIN b[66]
    DIRECTION OUTPUT ;
    USE SIGNAL ;
    PORT
      LAYER M4 ;
        RECT  21.516 52.848 21.6 52.872 ;
    END
  END b[66]
  PIN b[67]
    DIRECTION OUTPUT ;
    USE SIGNAL ;
    PORT
      LAYER M4 ;
        RECT  21.516 52.992 21.6 53.016 ;
    END
  END b[67]
  PIN b[68]
    DIRECTION OUTPUT ;
    USE SIGNAL ;
    PORT
      LAYER M4 ;
        RECT  21.516 53.136 21.6 53.16 ;
    END
  END b[68]
  PIN b[69]
    DIRECTION OUTPUT ;
    USE SIGNAL ;
    PORT
      LAYER M4 ;
        RECT  21.516 53.28 21.6 53.304 ;
    END
  END b[69]
  PIN b[6]
    DIRECTION OUTPUT ;
    USE SIGNAL ;
    PORT
      LAYER M4 ;
        RECT  21.516 30.384 21.6 30.408 ;
    END
  END b[6]
  PIN b[70]
    DIRECTION OUTPUT ;
    USE SIGNAL ;
    PORT
      LAYER M4 ;
        RECT  21.516 53.424 21.6 53.448 ;
    END
  END b[70]
  PIN b[71]
    DIRECTION OUTPUT ;
    USE SIGNAL ;
    PORT
      LAYER M4 ;
        RECT  21.516 53.568 21.6 53.592 ;
    END
  END b[71]
  PIN b[72]
    DIRECTION OUTPUT ;
    USE SIGNAL ;
    PORT
      LAYER M4 ;
        RECT  21.516 53.712 21.6 53.736 ;
    END
  END b[72]
  PIN b[73]
    DIRECTION OUTPUT ;
    USE SIGNAL ;
    PORT
      LAYER M4 ;
        RECT  21.516 53.856 21.6 53.88 ;
    END
  END b[73]
  PIN b[74]
    DIRECTION OUTPUT ;
    USE SIGNAL ;
    PORT
      LAYER M4 ;
        RECT  21.516 54 21.6 54.024 ;
    END
  END b[74]
  PIN b[75]
    DIRECTION OUTPUT ;
    USE SIGNAL ;
    PORT
      LAYER M4 ;
        RECT  21.516 54.144 21.6 54.168 ;
    END
  END b[75]
  PIN b[76]
    DIRECTION OUTPUT ;
    USE SIGNAL ;
    PORT
      LAYER M4 ;
        RECT  21.516 54.288 21.6 54.312 ;
    END
  END b[76]
  PIN b[77]
    DIRECTION OUTPUT ;
    USE SIGNAL ;
    PORT
      LAYER M4 ;
        RECT  21.516 54.432 21.6 54.456 ;
    END
  END b[77]
  PIN b[78]
    DIRECTION OUTPUT ;
    USE SIGNAL ;
    PORT
      LAYER M4 ;
        RECT  21.516 54.576 21.6 54.6 ;
    END
  END b[78]
  PIN b[79]
    DIRECTION OUTPUT ;
    USE SIGNAL ;
    PORT
      LAYER M4 ;
        RECT  21.516 54.72 21.6 54.744 ;
    END
  END b[79]
  PIN b[7]
    DIRECTION OUTPUT ;
    USE SIGNAL ;
    PORT
      LAYER M4 ;
        RECT  21.516 30.528 21.6 30.552 ;
    END
  END b[7]
  PIN b[80]
    DIRECTION OUTPUT ;
    USE SIGNAL ;
    PORT
      LAYER M4 ;
        RECT  21.516 54.864 21.6 54.888 ;
    END
  END b[80]
  PIN b[81]
    DIRECTION OUTPUT ;
    USE SIGNAL ;
    PORT
      LAYER M4 ;
        RECT  21.516 55.008 21.6 55.032 ;
    END
  END b[81]
  PIN b[82]
    DIRECTION OUTPUT ;
    USE SIGNAL ;
    PORT
      LAYER M4 ;
        RECT  21.516 55.152 21.6 55.176 ;
    END
  END b[82]
  PIN b[83]
    DIRECTION OUTPUT ;
    USE SIGNAL ;
    PORT
      LAYER M4 ;
        RECT  21.516 55.296 21.6 55.32 ;
    END
  END b[83]
  PIN b[84]
    DIRECTION OUTPUT ;
    USE SIGNAL ;
    PORT
      LAYER M4 ;
        RECT  21.516 55.44 21.6 55.464 ;
    END
  END b[84]
  PIN b[85]
    DIRECTION OUTPUT ;
    USE SIGNAL ;
    PORT
      LAYER M4 ;
        RECT  21.516 55.584 21.6 55.608 ;
    END
  END b[85]
  PIN b[86]
    DIRECTION OUTPUT ;
    USE SIGNAL ;
    PORT
      LAYER M4 ;
        RECT  21.516 55.728 21.6 55.752 ;
    END
  END b[86]
  PIN b[87]
    DIRECTION OUTPUT ;
    USE SIGNAL ;
    PORT
      LAYER M4 ;
        RECT  21.516 55.872 21.6 55.896 ;
    END
  END b[87]
  PIN b[88]
    DIRECTION OUTPUT ;
    USE SIGNAL ;
    PORT
      LAYER M4 ;
        RECT  21.516 56.016 21.6 56.04 ;
    END
  END b[88]
  PIN b[89]
    DIRECTION OUTPUT ;
    USE SIGNAL ;
    PORT
      LAYER M4 ;
        RECT  21.516 56.16 21.6 56.184 ;
    END
  END b[89]
  PIN b[8]
    DIRECTION OUTPUT ;
    USE SIGNAL ;
    PORT
      LAYER M4 ;
        RECT  21.516 30.672 21.6 30.696 ;
    END
  END b[8]
  PIN b[90]
    DIRECTION OUTPUT ;
    USE SIGNAL ;
    PORT
      LAYER M4 ;
        RECT  21.516 56.304 21.6 56.328 ;
    END
  END b[90]
  PIN b[91]
    DIRECTION OUTPUT ;
    USE SIGNAL ;
    PORT
      LAYER M4 ;
        RECT  21.516 56.448 21.6 56.472 ;
    END
  END b[91]
  PIN b[92]
    DIRECTION OUTPUT ;
    USE SIGNAL ;
    PORT
      LAYER M4 ;
        RECT  21.516 56.592 21.6 56.616 ;
    END
  END b[92]
  PIN b[93]
    DIRECTION OUTPUT ;
    USE SIGNAL ;
    PORT
      LAYER M4 ;
        RECT  21.516 56.736 21.6 56.76 ;
    END
  END b[93]
  PIN b[94]
    DIRECTION OUTPUT ;
    USE SIGNAL ;
    PORT
      LAYER M4 ;
        RECT  21.516 56.88 21.6 56.904 ;
    END
  END b[94]
  PIN b[95]
    DIRECTION OUTPUT ;
    USE SIGNAL ;
    PORT
      LAYER M4 ;
        RECT  21.516 57.024 21.6 57.048 ;
    END
  END b[95]
  PIN b[96]
    DIRECTION OUTPUT ;
    USE SIGNAL ;
    PORT
      LAYER M4 ;
        RECT  21.516 34.128 21.6 34.152 ;
    END
  END b[96]
  PIN b[97]
    DIRECTION OUTPUT ;
    USE SIGNAL ;
    PORT
      LAYER M4 ;
        RECT  21.516 34.272 21.6 34.296 ;
    END
  END b[97]
  PIN b[98]
    DIRECTION OUTPUT ;
    USE SIGNAL ;
    PORT
      LAYER M4 ;
        RECT  21.516 34.416 21.6 34.44 ;
    END
  END b[98]
  PIN b[99]
    DIRECTION OUTPUT ;
    USE SIGNAL ;
    PORT
      LAYER M4 ;
        RECT  21.516 34.56 21.6 34.584 ;
    END
  END b[99]
  PIN b[9]
    DIRECTION OUTPUT ;
    USE SIGNAL ;
    PORT
      LAYER M4 ;
        RECT  21.516 30.816 21.6 30.84 ;
    END
  END b[9]
  PIN ck
    DIRECTION INPUT ;
    USE SIGNAL ;
    PORT
      LAYER M5 ;
        RECT  9.792 0 9.816 0.084 ;
    END
  END ck
  PIN VDD
    DIRECTION INOUT ;
    USE POWER ;
    PORT
      LAYER M5 ;
        RECT  18.792 2.151 18.912 79.929 ;
        RECT  16.092 2.151 16.212 79.929 ;
        RECT  13.392 2.151 13.512 79.929 ;
        RECT  10.692 2.151 10.812 79.929 ;
        RECT  7.992 2.151 8.112 79.929 ;
        RECT  5.292 2.151 5.412 79.929 ;
        RECT  2.592 2.151 2.712 79.929 ;
    END
  END VDD
  PIN VSS
    DIRECTION INOUT ;
    USE GROUND ;
    PORT
      LAYER M5 ;
        RECT  18.6 2.137 18.72 79.943 ;
        RECT  15.9 2.137 16.02 79.943 ;
        RECT  13.2 2.137 13.32 79.943 ;
        RECT  10.5 2.137 10.62 79.943 ;
        RECT  7.8 2.137 7.92 79.943 ;
        RECT  5.1 2.137 5.22 79.943 ;
        RECT  2.4 2.137 2.52 79.943 ;
    END
  END VSS
  OBS
    LAYER RVTN ;
     RECT  2.16 2.16 19.44 2.295 ;
     RECT  2.16 2.565 19.44 2.835 ;
     RECT  2.16 3.105 19.44 3.375 ;
     RECT  2.16 3.645 19.44 3.915 ;
     RECT  2.16 4.185 19.44 4.455 ;
     RECT  2.16 4.725 19.44 4.995 ;
     RECT  2.16 5.265 19.44 5.535 ;
     RECT  2.16 5.805 19.44 6.075 ;
     RECT  2.16 6.345 19.44 6.615 ;
     RECT  2.16 6.885 19.44 7.155 ;
     RECT  2.16 7.425 19.44 7.695 ;
     RECT  2.16 7.965 19.44 8.235 ;
     RECT  2.16 8.505 19.44 8.775 ;
     RECT  2.16 9.045 19.44 9.315 ;
     RECT  2.16 9.585 19.44 9.855 ;
     RECT  2.16 10.125 19.44 10.395 ;
     RECT  2.16 10.665 19.44 10.935 ;
     RECT  2.16 11.205 19.44 11.475 ;
     RECT  2.16 11.745 19.44 12.015 ;
     RECT  2.16 12.285 19.44 12.555 ;
     RECT  2.16 12.825 19.44 13.095 ;
     RECT  2.16 13.365 19.44 13.635 ;
     RECT  2.16 13.905 19.44 14.175 ;
     RECT  2.16 14.445 19.44 14.715 ;
     RECT  2.16 14.985 19.44 15.255 ;
     RECT  2.16 15.525 19.44 15.795 ;
     RECT  2.16 16.065 19.44 16.335 ;
     RECT  2.16 16.605 19.44 16.875 ;
     RECT  2.16 17.145 19.44 17.415 ;
     RECT  2.16 17.685 19.44 17.955 ;
     RECT  2.16 18.225 19.44 18.495 ;
     RECT  2.16 18.765 19.44 19.035 ;
     RECT  2.16 19.305 19.44 19.575 ;
     RECT  2.16 19.845 19.44 20.115 ;
     RECT  2.16 20.385 19.44 20.655 ;
     RECT  2.16 20.925 19.44 21.195 ;
     RECT  2.16 21.465 19.44 21.735 ;
     RECT  2.16 22.005 19.44 22.275 ;
     RECT  2.16 22.545 19.44 22.815 ;
     RECT  2.16 23.085 19.44 23.355 ;
     RECT  2.16 23.625 19.44 23.895 ;
     RECT  2.16 24.165 19.44 24.435 ;
     RECT  2.16 24.705 19.44 24.975 ;
     RECT  2.16 25.245 19.44 25.515 ;
     RECT  2.16 25.785 19.44 26.055 ;
     RECT  2.16 26.325 19.44 26.595 ;
     RECT  2.16 26.865 19.44 27.135 ;
     RECT  2.16 27.405 19.44 27.675 ;
     RECT  2.16 27.945 19.44 28.215 ;
     RECT  2.16 28.485 19.44 28.755 ;
     RECT  2.16 29.025 19.44 29.295 ;
     RECT  2.16 29.565 19.44 29.835 ;
     RECT  2.16 30.105 19.44 30.375 ;
     RECT  2.16 30.645 19.44 30.915 ;
     RECT  2.16 31.185 19.44 31.455 ;
     RECT  2.16 31.725 19.44 31.995 ;
     RECT  2.16 32.265 19.44 32.535 ;
     RECT  2.16 32.805 19.44 33.075 ;
     RECT  2.16 33.345 19.44 33.615 ;
     RECT  2.16 33.885 19.44 34.155 ;
     RECT  2.16 34.425 19.44 34.695 ;
     RECT  2.16 34.965 19.44 35.235 ;
     RECT  2.16 35.505 19.44 35.775 ;
     RECT  2.16 36.045 19.44 36.315 ;
     RECT  2.16 36.585 19.44 36.855 ;
     RECT  2.16 37.125 19.44 37.395 ;
     RECT  2.16 37.665 19.44 37.935 ;
     RECT  2.16 38.205 19.44 38.475 ;
     RECT  2.16 38.745 19.44 39.015 ;
     RECT  2.16 39.285 19.44 39.555 ;
     RECT  2.16 39.825 19.44 40.095 ;
     RECT  2.16 40.365 19.44 40.635 ;
     RECT  2.16 40.905 19.44 41.175 ;
     RECT  2.16 41.445 19.44 41.715 ;
     RECT  2.16 41.985 19.44 42.255 ;
     RECT  2.16 42.525 19.44 42.795 ;
     RECT  2.16 43.065 19.44 43.335 ;
     RECT  2.16 43.605 19.44 43.875 ;
     RECT  2.16 44.145 19.44 44.415 ;
     RECT  2.16 44.685 19.44 44.955 ;
     RECT  2.16 45.225 19.44 45.495 ;
     RECT  2.16 45.765 19.44 46.035 ;
     RECT  2.16 46.305 19.44 46.575 ;
     RECT  2.16 46.845 19.44 47.115 ;
     RECT  2.16 47.385 19.44 47.655 ;
     RECT  2.16 47.925 19.44 48.195 ;
     RECT  2.16 48.465 19.44 48.735 ;
     RECT  2.16 49.005 19.44 49.275 ;
     RECT  2.16 49.545 19.44 49.815 ;
     RECT  2.16 50.085 19.44 50.355 ;
     RECT  2.16 50.625 19.44 50.895 ;
     RECT  2.16 51.165 19.44 51.435 ;
     RECT  2.16 51.705 19.44 51.975 ;
     RECT  2.16 52.245 19.44 52.515 ;
     RECT  2.16 52.785 19.44 53.055 ;
     RECT  2.16 53.325 19.44 53.595 ;
     RECT  2.16 53.865 19.44 54.135 ;
     RECT  2.16 54.405 19.44 54.675 ;
     RECT  2.16 54.945 19.44 55.215 ;
     RECT  2.16 55.485 19.44 55.755 ;
     RECT  2.16 56.025 19.44 56.295 ;
     RECT  2.16 56.565 19.44 56.835 ;
     RECT  2.16 57.105 19.44 57.375 ;
     RECT  2.16 57.645 19.44 57.915 ;
     RECT  2.16 58.185 19.44 58.455 ;
     RECT  2.16 58.725 19.44 58.995 ;
     RECT  2.16 59.265 19.44 59.535 ;
     RECT  2.16 59.805 19.44 60.075 ;
     RECT  2.16 60.345 19.44 60.615 ;
     RECT  2.16 60.885 19.44 61.155 ;
     RECT  2.16 61.425 19.44 61.695 ;
     RECT  2.16 61.965 19.44 62.235 ;
     RECT  2.16 62.505 19.44 62.775 ;
     RECT  2.16 63.045 19.44 63.315 ;
     RECT  2.16 63.585 19.44 63.855 ;
     RECT  2.16 64.125 19.44 64.395 ;
     RECT  2.16 64.665 19.44 64.935 ;
     RECT  2.16 65.205 19.44 65.475 ;
     RECT  2.16 65.745 19.44 66.015 ;
     RECT  2.16 66.285 19.44 66.555 ;
     RECT  2.16 66.825 19.44 67.095 ;
     RECT  2.16 67.365 19.44 67.635 ;
     RECT  2.16 67.905 19.44 68.175 ;
     RECT  2.16 68.445 19.44 68.715 ;
     RECT  2.16 68.985 19.44 69.255 ;
     RECT  2.16 69.525 19.44 69.795 ;
     RECT  2.16 70.065 19.44 70.335 ;
     RECT  2.16 70.605 19.44 70.875 ;
     RECT  2.16 71.145 19.44 71.415 ;
     RECT  2.16 71.685 19.44 71.955 ;
     RECT  2.16 72.225 19.44 72.495 ;
     RECT  2.16 72.765 19.44 73.035 ;
     RECT  2.16 73.305 19.44 73.575 ;
     RECT  2.16 73.845 19.44 74.115 ;
     RECT  2.16 74.385 19.44 74.655 ;
     RECT  2.16 74.925 19.44 75.195 ;
     RECT  2.16 75.465 19.44 75.735 ;
     RECT  2.16 76.005 19.44 76.275 ;
     RECT  2.16 76.545 19.44 76.815 ;
     RECT  2.16 77.085 19.44 77.355 ;
     RECT  2.16 77.625 19.44 77.895 ;
     RECT  2.16 78.165 19.44 78.435 ;
     RECT  2.16 78.705 19.44 78.975 ;
     RECT  2.16 79.245 19.44 79.515 ;
     RECT  2.16 79.785 19.44 79.92 ;
    LAYER RVTP ;
     RECT  2.16 2.295 19.44 2.565 ;
     RECT  2.16 2.835 19.44 3.105 ;
     RECT  2.16 3.375 19.44 3.645 ;
     RECT  2.16 3.915 19.44 4.185 ;
     RECT  2.16 4.455 19.44 4.725 ;
     RECT  2.16 4.995 19.44 5.265 ;
     RECT  2.16 5.535 19.44 5.805 ;
     RECT  2.16 6.075 19.44 6.345 ;
     RECT  2.16 6.615 19.44 6.885 ;
     RECT  2.16 7.155 19.44 7.425 ;
     RECT  2.16 7.695 19.44 7.965 ;
     RECT  2.16 8.235 19.44 8.505 ;
     RECT  2.16 8.775 19.44 9.045 ;
     RECT  2.16 9.315 19.44 9.585 ;
     RECT  2.16 9.855 19.44 10.125 ;
     RECT  2.16 10.395 19.44 10.665 ;
     RECT  2.16 10.935 19.44 11.205 ;
     RECT  2.16 11.475 19.44 11.745 ;
     RECT  2.16 12.015 19.44 12.285 ;
     RECT  2.16 12.555 19.44 12.825 ;
     RECT  2.16 13.095 19.44 13.365 ;
     RECT  2.16 13.635 19.44 13.905 ;
     RECT  2.16 14.175 19.44 14.445 ;
     RECT  2.16 14.715 19.44 14.985 ;
     RECT  2.16 15.255 19.44 15.525 ;
     RECT  2.16 15.795 19.44 16.065 ;
     RECT  2.16 16.335 19.44 16.605 ;
     RECT  2.16 16.875 19.44 17.145 ;
     RECT  2.16 17.415 19.44 17.685 ;
     RECT  2.16 17.955 19.44 18.225 ;
     RECT  2.16 18.495 19.44 18.765 ;
     RECT  2.16 19.035 19.44 19.305 ;
     RECT  2.16 19.575 19.44 19.845 ;
     RECT  2.16 20.115 19.44 20.385 ;
     RECT  2.16 20.655 19.44 20.925 ;
     RECT  2.16 21.195 19.44 21.465 ;
     RECT  2.16 21.735 19.44 22.005 ;
     RECT  2.16 22.275 19.44 22.545 ;
     RECT  2.16 22.815 19.44 23.085 ;
     RECT  2.16 23.355 19.44 23.625 ;
     RECT  2.16 23.895 19.44 24.165 ;
     RECT  2.16 24.435 19.44 24.705 ;
     RECT  2.16 24.975 19.44 25.245 ;
     RECT  2.16 25.515 19.44 25.785 ;
     RECT  2.16 26.055 19.44 26.325 ;
     RECT  2.16 26.595 19.44 26.865 ;
     RECT  2.16 27.135 19.44 27.405 ;
     RECT  2.16 27.675 19.44 27.945 ;
     RECT  2.16 28.215 19.44 28.485 ;
     RECT  2.16 28.755 19.44 29.025 ;
     RECT  2.16 29.295 19.44 29.565 ;
     RECT  2.16 29.835 19.44 30.105 ;
     RECT  2.16 30.375 19.44 30.645 ;
     RECT  2.16 30.915 19.44 31.185 ;
     RECT  2.16 31.455 19.44 31.725 ;
     RECT  2.16 31.995 19.44 32.265 ;
     RECT  2.16 32.535 19.44 32.805 ;
     RECT  2.16 33.075 19.44 33.345 ;
     RECT  2.16 33.615 19.44 33.885 ;
     RECT  2.16 34.155 19.44 34.425 ;
     RECT  2.16 34.695 19.44 34.965 ;
     RECT  2.16 35.235 19.44 35.505 ;
     RECT  2.16 35.775 19.44 36.045 ;
     RECT  2.16 36.315 19.44 36.585 ;
     RECT  2.16 36.855 19.44 37.125 ;
     RECT  2.16 37.395 19.44 37.665 ;
     RECT  2.16 37.935 19.44 38.205 ;
     RECT  2.16 38.475 19.44 38.745 ;
     RECT  2.16 39.015 19.44 39.285 ;
     RECT  2.16 39.555 19.44 39.825 ;
     RECT  2.16 40.095 19.44 40.365 ;
     RECT  2.16 40.635 19.44 40.905 ;
     RECT  2.16 41.175 19.44 41.445 ;
     RECT  2.16 41.715 19.44 41.985 ;
     RECT  2.16 42.255 19.44 42.525 ;
     RECT  2.16 42.795 19.44 43.065 ;
     RECT  2.16 43.335 19.44 43.605 ;
     RECT  2.16 43.875 19.44 44.145 ;
     RECT  2.16 44.415 19.44 44.685 ;
     RECT  2.16 44.955 19.44 45.225 ;
     RECT  2.16 45.495 19.44 45.765 ;
     RECT  2.16 46.035 19.44 46.305 ;
     RECT  2.16 46.575 19.44 46.845 ;
     RECT  2.16 47.115 19.44 47.385 ;
     RECT  2.16 47.655 19.44 47.925 ;
     RECT  2.16 48.195 19.44 48.465 ;
     RECT  2.16 48.735 19.44 49.005 ;
     RECT  2.16 49.275 19.44 49.545 ;
     RECT  2.16 49.815 19.44 50.085 ;
     RECT  2.16 50.355 19.44 50.625 ;
     RECT  2.16 50.895 19.44 51.165 ;
     RECT  2.16 51.435 19.44 51.705 ;
     RECT  2.16 51.975 19.44 52.245 ;
     RECT  2.16 52.515 19.44 52.785 ;
     RECT  2.16 53.055 19.44 53.325 ;
     RECT  2.16 53.595 19.44 53.865 ;
     RECT  2.16 54.135 19.44 54.405 ;
     RECT  2.16 54.675 19.44 54.945 ;
     RECT  2.16 55.215 19.44 55.485 ;
     RECT  2.16 55.755 19.44 56.025 ;
     RECT  2.16 56.295 19.44 56.565 ;
     RECT  2.16 56.835 19.44 57.105 ;
     RECT  2.16 57.375 19.44 57.645 ;
     RECT  2.16 57.915 19.44 58.185 ;
     RECT  2.16 58.455 19.44 58.725 ;
     RECT  2.16 58.995 19.44 59.265 ;
     RECT  2.16 59.535 19.44 59.805 ;
     RECT  2.16 60.075 19.44 60.345 ;
     RECT  2.16 60.615 19.44 60.885 ;
     RECT  2.16 61.155 19.44 61.425 ;
     RECT  2.16 61.695 19.44 61.965 ;
     RECT  2.16 62.235 19.44 62.505 ;
     RECT  2.16 62.775 19.44 63.045 ;
     RECT  2.16 63.315 19.44 63.585 ;
     RECT  2.16 63.855 19.44 64.125 ;
     RECT  2.16 64.395 19.44 64.665 ;
     RECT  2.16 64.935 19.44 65.205 ;
     RECT  2.16 65.475 19.44 65.745 ;
     RECT  2.16 66.015 19.44 66.285 ;
     RECT  2.16 66.555 19.44 66.825 ;
     RECT  2.16 67.095 19.44 67.365 ;
     RECT  2.16 67.635 19.44 67.905 ;
     RECT  2.16 68.175 19.44 68.445 ;
     RECT  2.16 68.715 19.44 68.985 ;
     RECT  2.16 69.255 19.44 69.525 ;
     RECT  2.16 69.795 19.44 70.065 ;
     RECT  2.16 70.335 19.44 70.605 ;
     RECT  2.16 70.875 19.44 71.145 ;
     RECT  2.16 71.415 19.44 71.685 ;
     RECT  2.16 71.955 19.44 72.225 ;
     RECT  2.16 72.495 19.44 72.765 ;
     RECT  2.16 73.035 19.44 73.305 ;
     RECT  2.16 73.575 19.44 73.845 ;
     RECT  2.16 74.115 19.44 74.385 ;
     RECT  2.16 74.655 19.44 74.925 ;
     RECT  2.16 75.195 19.44 75.465 ;
     RECT  2.16 75.735 19.44 76.005 ;
     RECT  2.16 76.275 19.44 76.545 ;
     RECT  2.16 76.815 19.44 77.085 ;
     RECT  2.16 77.355 19.44 77.625 ;
     RECT  2.16 77.895 19.44 78.165 ;
     RECT  2.16 78.435 19.44 78.705 ;
     RECT  2.16 78.975 19.44 79.245 ;
     RECT  2.16 79.515 19.44 79.785 ;
    LAYER M1 ;
     RECT  2.16 2.151 19.44 79.929 ;
    LAYER M2 ;
     RECT  0.103 26.532 0.139 27.63 ;
     RECT  0.103 28.422 0.139 28.44 ;
     RECT  0.139 26.532 0.211 28.71 ;
     RECT  0.211 26.496 0.247 28.71 ;
     RECT  0.247 26.262 0.283 28.71 ;
     RECT  0.283 62.712 0.319 62.73 ;
     RECT  0.283 64.674 0.355 64.692 ;
     RECT  0.211 58.932 0.391 58.95 ;
     RECT  0.283 61.2 0.391 61.218 ;
     RECT  0.355 64.674 0.391 64.764 ;
     RECT  0.319 62.712 0.419 63.414 ;
     RECT  0.391 17.964 0.427 17.982 ;
     RECT  0.427 17.766 0.463 17.982 ;
     RECT  0.463 17.766 0.499 18.522 ;
     RECT  0.103 74.592 0.499 74.61 ;
     RECT  0.463 75.744 0.499 75.762 ;
     RECT  0.391 61.128 0.535 61.218 ;
     RECT  0.391 64.602 0.535 64.764 ;
     RECT  0.427 73.08 0.535 73.098 ;
     RECT  0.031 78.516 0.535 78.696 ;
     RECT  0.283 25.56 0.563 28.71 ;
     RECT  0.535 60.93 0.563 61.218 ;
     RECT  0.419 62.784 0.563 63.414 ;
     RECT  0.535 64.206 0.751 64.764 ;
     RECT  0.319 24.606 0.787 24.624 ;
     RECT  0.391 58.77 0.823 58.95 ;
     RECT  0.103 12.528 0.859 12.546 ;
     RECT  0.103 68.382 0.895 68.4 ;
     RECT  0.103 69.498 0.895 70.668 ;
     RECT  0.895 16.416 0.931 16.434 ;
     RECT  0.499 17.496 0.931 18.522 ;
     RECT  0.499 74.592 0.931 75.762 ;
     RECT  0.715 67.176 0.967 67.194 ;
     RECT  0.895 68.382 0.967 70.668 ;
     RECT  0.967 2.574 1.003 2.592 ;
     RECT  0.103 53.532 1.327 53.55 ;
     RECT  1.327 19.584 1.363 19.602 ;
     RECT  0.535 78.516 1.399 78.804 ;
     RECT  1.399 22.554 1.435 22.572 ;
     RECT  1.399 57.078 1.435 57.096 ;
     RECT  1.327 53.532 1.471 53.964 ;
     RECT  1.291 54.756 1.471 54.774 ;
     RECT  0.563 25.56 1.507 25.578 ;
     RECT  0.563 26.532 1.507 28.71 ;
     RECT  0.823 10.476 1.579 10.494 ;
     RECT  1.543 11.25 1.579 11.268 ;
     RECT  0.823 58.266 1.579 58.95 ;
     RECT  0.103 59.742 1.579 59.76 ;
     RECT  1.579 10.476 1.651 11.268 ;
     RECT  1.651 10.206 1.687 11.268 ;
     RECT  1.399 78.21 1.687 78.804 ;
     RECT  1.435 57.078 1.723 57.366 ;
     RECT  1.579 58.266 1.723 59.76 ;
     RECT  1.723 55.692 1.759 55.71 ;
     RECT  1.687 10.134 1.795 11.268 ;
     RECT  1.075 8.514 1.831 8.532 ;
     RECT  1.687 78.21 1.831 79.344 ;
     RECT  1.903 46.548 1.939 46.566 ;
     RECT  0.563 62.856 2.011 63.414 ;
     RECT  1.795 9.936 2.047 11.268 ;
     RECT  0.967 67.176 2.047 70.668 ;
     RECT  1.831 8.514 2.083 8.964 ;
     RECT  2.047 9.9 2.083 11.268 ;
     RECT  1.903 42.84 2.083 42.858 ;
     RECT  0.535 72.576 2.083 73.098 ;
     RECT  1.795 76.626 2.119 76.644 ;
     RECT  1.831 77.706 2.119 79.344 ;
     RECT  0.859 12.096 2.155 12.546 ;
     RECT  1.939 42.066 2.155 42.084 ;
     RECT  2.083 42.84 2.155 43.092 ;
     RECT  1.939 46.314 2.155 46.566 ;
     RECT  1.003 2.34 2.16 2.592 ;
     RECT  1.039 4.266 2.16 4.284 ;
     RECT  1.867 6.12 2.16 6.138 ;
     RECT  0.535 7.236 2.16 7.254 ;
     RECT  2.083 8.514 2.16 11.268 ;
     RECT  2.155 12.096 2.16 12.816 ;
     RECT  2.119 13.95 2.16 13.968 ;
     RECT  0.931 16.416 2.16 18.522 ;
     RECT  1.363 19.584 2.16 19.944 ;
     RECT  1.291 21.006 2.16 21.024 ;
     RECT  1.435 22.32 2.16 22.572 ;
     RECT  0.787 24.372 2.16 24.624 ;
     RECT  1.507 25.56 2.16 28.71 ;
     RECT  1.831 33.084 2.16 33.102 ;
     RECT  1.831 35.514 2.16 35.604 ;
     RECT  2.155 42.066 2.16 43.092 ;
     RECT  2.155 46.206 2.16 46.566 ;
     RECT  1.723 52.758 2.16 52.776 ;
     RECT  1.471 53.532 2.16 54.774 ;
     RECT  1.759 55.692 2.16 56.088 ;
     RECT  1.723 57.042 2.16 59.76 ;
     RECT  0.563 60.93 2.16 60.948 ;
     RECT  0.859 61.776 2.16 61.794 ;
     RECT  2.011 62.82 2.16 63.414 ;
     RECT  0.751 64.206 2.16 65.502 ;
     RECT  2.047 67.068 2.16 70.668 ;
     RECT  2.083 72.126 2.16 73.098 ;
     RECT  0.931 74.196 2.16 75.762 ;
     RECT  2.119 76.626 2.16 79.344 ;
     RECT  2.16 2.151 12.955 79.929 ;
     RECT  12.955 1.962 13.567 79.929 ;
     RECT  13.567 1.8 13.783 79.929 ;
     RECT  13.783 1.728 16.043 79.929 ;
     RECT  16.043 1.8 16.907 79.929 ;
     RECT  16.907 1.881 17.915 79.929 ;
     RECT  17.915 1.926 18.167 79.929 ;
     RECT  18.167 1.962 18.239 79.929 ;
     RECT  18.239 2.034 19.44 79.929 ;
     RECT  19.44 38.25 19.499 79.344 ;
     RECT  19.499 38.25 19.823 55.404 ;
     RECT  19.823 38.25 19.895 48.294 ;
     RECT  19.44 3.816 19.931 26.424 ;
     RECT  19.44 35.478 19.931 37.458 ;
     RECT  19.895 38.286 19.931 48.294 ;
     RECT  19.823 49.05 19.931 55.404 ;
     RECT  19.499 56.376 19.931 79.344 ;
     RECT  19.931 4.734 19.967 19.908 ;
     RECT  19.44 27.216 19.967 28.674 ;
     RECT  19.44 29.466 19.967 34.722 ;
     RECT  19.931 40.446 19.967 44.784 ;
     RECT  19.931 45.846 19.967 48.294 ;
     RECT  19.931 50.904 19.967 55.404 ;
     RECT  19.931 56.376 19.967 72.144 ;
     RECT  19.931 73.116 19.967 73.674 ;
     RECT  19.931 20.736 20.003 26.424 ;
     RECT  19.967 30.888 20.003 32.022 ;
     RECT  19.931 35.478 20.003 37.422 ;
     RECT  19.967 50.904 20.003 54.504 ;
     RECT  19.967 56.376 20.219 60.948 ;
     RECT  19.967 4.734 20.399 17.946 ;
     RECT  19.44 2.034 20.435 2.754 ;
     RECT  19.967 32.886 20.435 34.722 ;
     RECT  20.435 2.034 20.471 2.556 ;
     RECT  19.967 65.988 20.471 72.144 ;
     RECT  20.471 2.034 20.507 2.214 ;
     RECT  19.931 3.816 20.507 3.834 ;
     RECT  20.399 4.734 20.507 5.454 ;
     RECT  20.399 6.39 20.507 17.946 ;
     RECT  19.967 18.81 20.507 19.908 ;
     RECT  20.003 20.736 20.507 22.536 ;
     RECT  19.967 27.45 20.507 28.674 ;
     RECT  20.435 33.39 20.507 34.722 ;
     RECT  20.003 35.514 20.507 37.422 ;
     RECT  19.931 38.448 20.507 39.474 ;
     RECT  19.967 40.446 20.507 42.048 ;
     RECT  19.967 46.35 20.507 48.294 ;
     RECT  19.931 49.05 20.507 50.112 ;
     RECT  19.967 55.386 20.507 55.404 ;
     RECT  20.219 56.376 20.507 58.104 ;
     RECT  20.219 58.932 20.507 60.948 ;
     RECT  19.967 61.776 20.507 64.962 ;
     RECT  20.471 65.988 20.507 67.734 ;
     RECT  20.471 68.49 20.507 72.144 ;
     RECT  19.967 73.116 20.507 73.638 ;
     RECT  19.931 74.466 20.507 76.914 ;
     RECT  19.931 77.67 20.507 79.344 ;
     RECT  20.507 11.448 20.543 17.784 ;
     RECT  20.507 20.736 20.543 21.762 ;
     RECT  20.003 23.328 20.543 25.884 ;
     RECT  20.003 31.5 20.543 32.022 ;
     RECT  20.507 36.054 20.543 36.072 ;
     RECT  20.507 36.936 20.543 37.422 ;
     RECT  20.507 38.448 20.543 39.384 ;
     RECT  20.507 40.446 20.543 40.932 ;
     RECT  20.003 50.904 20.543 53.154 ;
     RECT  20.003 54.108 20.543 54.504 ;
     RECT  20.507 56.376 20.543 56.664 ;
     RECT  20.507 58.086 20.543 58.104 ;
     RECT  20.507 59.544 20.543 60.948 ;
     RECT  20.507 62.28 20.543 64.386 ;
     RECT  20.507 65.988 20.543 66.006 ;
     RECT  20.507 67.374 20.543 67.734 ;
     RECT  20.507 68.49 20.543 71.208 ;
     RECT  20.507 75.78 20.543 76.914 ;
     RECT  20.543 31.734 20.579 32.022 ;
     RECT  20.543 37.251 20.579 37.422 ;
     RECT  20.507 46.35 20.579 47.952 ;
     RECT  20.543 56.61 20.579 56.664 ;
     RECT  20.543 60.894 20.579 60.912 ;
     RECT  20.543 64.368 20.579 64.386 ;
     RECT  20.543 15.03 20.615 17.748 ;
     RECT  20.615 15.03 21.443 17.676 ;
     RECT  20.543 62.28 21.443 63.414 ;
     RECT  20.507 2.034 21.479 2.124 ;
     RECT  20.507 6.966 21.479 10.692 ;
     RECT  20.543 11.916 21.479 13.464 ;
     RECT  21.443 16.506 21.479 17.676 ;
     RECT  20.507 19.044 21.479 19.332 ;
     RECT  20.543 20.898 21.479 21.186 ;
     RECT  20.543 24.174 21.479 25.272 ;
     RECT  20.507 27.45 21.479 27.504 ;
     RECT  19.967 43.074 21.479 44.784 ;
     RECT  20.579 47.16 21.479 47.952 ;
     RECT  20.507 49.05 21.479 50.04 ;
     RECT  20.543 50.904 21.479 51.462 ;
     RECT  20.543 52.956 21.479 53.118 ;
     RECT  21.443 62.28 21.479 62.568 ;
     RECT  20.507 72 21.479 72.054 ;
     RECT  20.543 75.78 21.479 76.644 ;
     RECT  21.479 2.034 21.515 2.052 ;
     RECT  20.507 5.436 21.515 5.454 ;
     RECT  21.479 6.966 21.515 8.874 ;
     RECT  21.479 9.936 21.515 10.692 ;
     RECT  21.479 11.916 21.515 11.934 ;
     RECT  21.479 12.798 21.515 13.356 ;
     RECT  21.443 15.03 21.515 15.354 ;
     RECT  21.479 16.506 21.515 16.524 ;
     RECT  21.479 17.658 21.515 17.676 ;
     RECT  21.479 19.314 21.515 19.332 ;
     RECT  21.479 20.934 21.515 21.186 ;
     RECT  20.507 22.518 21.515 22.536 ;
     RECT  21.479 24.876 21.515 24.894 ;
     RECT  21.479 27.45 21.515 27.468 ;
     RECT  19.967 29.466 21.515 29.484 ;
     RECT  20.579 31.734 21.515 31.752 ;
     RECT  20.507 33.39 21.515 33.984 ;
     RECT  20.579 37.404 21.515 37.422 ;
     RECT  20.543 38.988 21.515 39.006 ;
     RECT  20.543 40.914 21.515 40.932 ;
     RECT  20.507 41.796 21.515 41.814 ;
     RECT  21.479 43.416 21.515 43.974 ;
     RECT  21.479 44.766 21.515 44.784 ;
     RECT  20.579 46.35 21.515 46.368 ;
     RECT  21.479 47.16 21.515 47.844 ;
     RECT  21.479 49.824 21.515 50.04 ;
     RECT  21.479 50.976 21.515 51.462 ;
     RECT  21.479 52.956 21.515 52.974 ;
     RECT  20.579 56.646 21.515 56.664 ;
     RECT  20.543 59.616 21.515 60.102 ;
     RECT  21.479 62.28 21.515 62.298 ;
     RECT  21.443 63.396 21.515 63.414 ;
     RECT  20.543 67.374 21.515 67.698 ;
     RECT  20.543 68.49 21.515 69.624 ;
     RECT  20.543 70.686 21.515 71.208 ;
     RECT  21.479 72 21.515 72.018 ;
     RECT  20.507 73.62 21.515 73.638 ;
     RECT  20.507 75.006 21.515 75.024 ;
     RECT  21.479 75.78 21.515 75.798 ;
     RECT  21.479 76.626 21.515 76.644 ;
     RECT  20.507 77.67 21.515 78.804 ;
    LAYER M3 ;
     RECT  15.876 0.859 15.894 1.003 ;
     RECT  20.484 0.715 20.502 1.435 ;
     RECT  21.492 1.291 21.51 1.723 ;
     RECT  13.788 1.723 13.806 1.795 ;
     RECT  15.876 1.003 16.434 1.795 ;
     RECT  15.12 1.867 15.138 1.876 ;
     RECT  14.832 1.876 15.138 1.921 ;
     RECT  15.876 1.795 16.902 1.921 ;
     RECT  17.892 1.876 17.91 1.921 ;
     RECT  13.572 1.795 13.806 1.957 ;
     RECT  17.892 1.921 18.162 1.957 ;
     RECT  12.96 1.957 13.806 2.011 ;
     RECT  21.456 1.723 21.51 2.057 ;
     RECT  14.832 1.921 16.902 2.059 ;
     RECT  17.892 1.957 18.234 2.059 ;
     RECT  14.652 2.059 16.902 2.065 ;
     RECT  17.892 2.059 19.098 2.065 ;
     RECT  21.456 2.057 21.474 2.129 ;
     RECT  5.292 2.059 5.31 2.143 ;
     RECT  10.692 2.059 10.854 2.143 ;
     RECT  14.652 2.065 19.098 2.189 ;
     RECT  12.564 2.011 13.806 2.227 ;
     RECT  14.652 2.189 19.026 2.227 ;
     RECT  10.515 2.143 10.854 2.237 ;
     RECT  11.808 2.227 11.826 2.285 ;
     RECT  12.564 2.227 19.026 2.335 ;
     RECT  2.415 2.143 2.505 2.413 ;
     RECT  5.115 2.143 5.31 2.413 ;
     RECT  7.815 2.143 7.905 2.413 ;
     RECT  6.84 2.059 6.858 2.489 ;
     RECT  20.34 1.435 20.502 2.492 ;
     RECT  1.008 2.335 1.026 2.497 ;
     RECT  20.376 2.492 20.502 2.561 ;
     RECT  1.008 2.497 1.134 2.569 ;
     RECT  20.412 2.561 20.502 2.759 ;
     RECT  21.42 2.539 21.438 2.765 ;
     RECT  3.744 2.191 3.762 2.803 ;
     RECT  3.744 2.803 4.194 2.911 ;
     RECT  10.515 2.237 10.797 3.001 ;
     RECT  2.415 2.413 2.697 3.109 ;
     RECT  10.515 3.001 10.854 3.137 ;
     RECT  2.415 3.109 2.826 3.163 ;
     RECT  2.304 3.163 2.826 3.307 ;
     RECT  3.708 2.911 4.194 3.307 ;
     RECT  11.988 2.335 19.026 3.307 ;
     RECT  6.804 3.403 6.822 3.581 ;
     RECT  11.988 3.307 19.386 3.721 ;
     RECT  11.664 3.721 19.386 3.749 ;
     RECT  20.484 2.759 20.502 3.839 ;
     RECT  2.304 3.307 4.194 3.883 ;
     RECT  2.304 3.883 4.302 3.92 ;
     RECT  12.6 3.749 19.386 4.027 ;
     RECT  10.515 3.137 10.797 4.189 ;
     RECT  11.664 3.749 11.826 4.217 ;
     RECT  21.492 3.019 21.51 4.219 ;
     RECT  10.515 4.189 10.854 4.261 ;
     RECT  12.6 4.027 19.926 4.289 ;
     RECT  21.42 4.219 21.51 4.349 ;
     RECT  10.515 4.261 10.926 4.351 ;
     RECT  10.404 4.351 10.926 4.397 ;
     RECT  10.515 4.397 10.926 4.729 ;
     RECT  11.664 4.217 11.682 4.729 ;
     RECT  6.84 4.657 6.858 4.829 ;
     RECT  10.515 4.729 11.682 4.829 ;
     RECT  2.304 3.92 4.194 4.891 ;
     RECT  10.515 4.829 10.926 4.919 ;
     RECT  10.515 4.919 10.854 5.027 ;
     RECT  11.664 4.829 11.682 5.083 ;
     RECT  12.6 4.289 19.386 5.083 ;
     RECT  11.664 5.083 19.386 5.117 ;
     RECT  2.268 4.891 4.194 5.161 ;
     RECT  5.115 2.413 5.397 5.161 ;
     RECT  2.268 5.161 5.397 5.225 ;
     RECT  0.972 2.569 1.134 5.323 ;
     RECT  21.492 4.349 21.51 5.459 ;
     RECT  0.324 5.323 1.134 5.501 ;
     RECT  20.484 4.603 20.502 5.611 ;
     RECT  13.104 5.117 19.386 5.645 ;
     RECT  7.815 2.413 8.097 5.707 ;
     RECT  20.448 5.611 20.502 5.755 ;
     RECT  7.815 5.707 8.19 5.837 ;
     RECT  10.515 5.027 10.797 5.851 ;
     RECT  20.412 5.755 20.502 5.899 ;
     RECT  0.144 5.899 0.162 6.029 ;
     RECT  13.176 5.645 19.386 6.043 ;
     RECT  2.304 5.225 5.397 6.115 ;
     RECT  13.176 6.043 19.422 6.139 ;
     RECT  12.132 5.117 12.186 6.151 ;
     RECT  20.376 5.899 20.502 6.178 ;
     RECT  10.515 5.851 11.322 6.385 ;
     RECT  12.132 6.151 12.258 6.385 ;
     RECT  20.34 6.178 20.502 6.413 ;
     RECT  21.312 6.475 21.33 6.653 ;
     RECT  10.515 6.385 12.258 6.667 ;
     RECT  13.176 6.139 19.494 6.667 ;
     RECT  0.972 5.501 1.134 7.231 ;
     RECT  10.515 6.667 19.494 7.231 ;
     RECT  20.34 6.413 20.466 7.231 ;
     RECT  10.515 7.231 20.466 7.373 ;
     RECT  21.456 6.763 21.51 7.627 ;
     RECT  6.66 7.087 6.678 7.663 ;
     RECT  20.52 7.501 20.538 7.771 ;
     RECT  7.815 5.837 8.097 7.867 ;
     RECT  20.52 7.771 20.574 7.949 ;
     RECT  21.42 7.627 21.51 8.033 ;
     RECT  7.815 7.867 8.19 8.477 ;
     RECT  20.52 7.949 20.538 8.525 ;
     RECT  21.456 8.033 21.51 8.879 ;
     RECT  0.54 7.231 1.134 8.941 ;
     RECT  1.872 6.115 5.397 8.941 ;
     RECT  6.552 7.663 6.678 8.977 ;
     RECT  20.484 8.923 20.502 9.067 ;
     RECT  10.515 7.373 19.494 9.085 ;
     RECT  20.448 9.067 20.502 9.085 ;
     RECT  6.516 8.977 6.678 9.211 ;
     RECT  21.456 8.879 21.474 9.347 ;
     RECT  6.516 9.211 6.858 9.389 ;
     RECT  6.516 9.389 6.75 9.392 ;
     RECT  0.54 8.941 5.397 9.481 ;
     RECT  10.515 9.085 20.502 9.859 ;
     RECT  10.515 9.859 20.538 9.965 ;
     RECT  0.54 9.481 5.454 10.123 ;
     RECT  0.144 10.123 5.454 10.253 ;
     RECT  21.492 9.643 21.51 10.507 ;
     RECT  21.42 10.507 21.51 10.637 ;
     RECT  7.815 8.477 8.097 10.669 ;
     RECT  6.516 9.392 6.714 10.831 ;
     RECT  10.515 9.965 20.502 11.039 ;
     RECT  6.516 10.831 6.822 11.281 ;
     RECT  6.516 11.281 6.858 11.399 ;
     RECT  20.448 11.039 20.502 11.443 ;
     RECT  20.448 11.443 20.538 11.777 ;
     RECT  21.492 10.637 21.51 11.803 ;
     RECT  7.704 10.669 8.097 11.911 ;
     RECT  21.312 11.803 21.51 11.981 ;
     RECT  21.456 11.981 21.51 12.317 ;
     RECT  20.52 11.777 20.538 12.413 ;
     RECT  9.612 11.677 9.63 12.487 ;
     RECT  0.54 10.253 5.454 12.523 ;
     RECT  0.108 12.523 5.454 12.56 ;
     RECT  0.144 12.56 5.454 12.721 ;
     RECT  7.704 11.911 8.298 12.721 ;
     RECT  6.516 11.399 6.822 12.859 ;
     RECT  0.144 12.721 5.526 13.085 ;
     RECT  21.492 12.317 21.51 13.361 ;
     RECT  9.576 12.487 9.63 13.405 ;
     RECT  6.516 12.859 6.858 13.441 ;
     RECT  7.704 12.721 8.334 13.441 ;
     RECT  21.456 13.387 21.474 13.469 ;
     RECT  10.515 11.039 19.494 13.531 ;
     RECT  20.484 13.243 20.502 13.531 ;
     RECT  9.108 13.405 9.63 13.603 ;
     RECT  10.515 13.531 20.502 13.667 ;
     RECT  20.484 13.667 20.502 13.669 ;
     RECT  20.484 13.669 20.538 14.549 ;
     RECT  0.54 13.085 5.526 14.683 ;
     RECT  6.516 13.441 8.334 14.683 ;
     RECT  20.52 14.549 20.538 14.717 ;
     RECT  0.54 14.683 8.334 14.791 ;
     RECT  9.108 13.603 9.666 14.791 ;
     RECT  21.492 14.395 21.51 14.827 ;
     RECT  21.456 14.827 21.51 14.971 ;
     RECT  10.515 13.667 19.494 15.061 ;
     RECT  0.54 14.791 9.666 15.493 ;
     RECT  10.476 15.061 19.494 15.493 ;
     RECT  0.54 15.493 19.494 15.601 ;
     RECT  21.42 14.971 21.51 16.169 ;
     RECT  20.484 15.835 20.502 16.405 ;
     RECT  21.456 16.169 21.51 16.529 ;
     RECT  0.54 15.601 19.602 16.645 ;
     RECT  20.484 16.405 20.538 16.645 ;
     RECT  0.54 16.645 20.538 16.987 ;
     RECT  0.144 16.987 20.538 17.117 ;
     RECT  0.432 17.117 20.538 17.165 ;
     RECT  21.456 16.529 21.474 17.275 ;
     RECT  21.456 17.275 21.51 17.419 ;
     RECT  21.42 17.419 21.51 17.681 ;
     RECT  20.484 17.165 20.538 17.725 ;
     RECT  0.432 17.165 19.602 17.959 ;
     RECT  20.484 17.725 20.61 18.029 ;
     RECT  0.396 17.959 19.602 18.301 ;
     RECT  20.484 18.029 20.502 18.301 ;
     RECT  21.312 18.283 21.33 18.427 ;
     RECT  21.312 18.427 21.51 18.461 ;
     RECT  0.396 18.301 20.502 18.749 ;
     RECT  21.456 18.461 21.51 19.067 ;
     RECT  20.448 18.749 20.502 19.111 ;
     RECT  20.448 19.111 20.538 19.181 ;
     RECT  21.492 19.067 21.51 19.337 ;
     RECT  0.396 18.749 19.638 19.579 ;
     RECT  20.448 19.181 20.502 19.579 ;
     RECT  0.396 19.579 20.502 19.913 ;
     RECT  0.396 19.913 19.926 20.731 ;
     RECT  21.492 20.443 21.51 20.875 ;
     RECT  21.456 20.875 21.51 20.921 ;
     RECT  21.492 20.921 21.51 21.2 ;
     RECT  0.396 20.731 20.538 22.061 ;
     RECT  21.492 22.315 21.51 22.541 ;
     RECT  21.312 22.603 21.33 22.781 ;
     RECT  0.396 22.061 20.502 23.179 ;
     RECT  0.144 23.179 20.538 23.309 ;
     RECT  0.396 23.309 20.538 23.729 ;
     RECT  0.396 23.729 19.926 23.789 ;
     RECT  21.492 24.043 21.51 24.169 ;
     RECT  0.396 23.789 19.638 24.511 ;
     RECT  0.396 24.511 19.962 24.601 ;
     RECT  0.324 24.601 19.962 24.745 ;
     RECT  21.456 24.169 21.51 24.899 ;
     RECT  21.456 24.899 21.474 25.277 ;
     RECT  0.324 24.745 20.502 25.555 ;
     RECT  0.288 25.555 20.502 25.627 ;
     RECT  0.288 25.627 20.538 25.889 ;
     RECT  0.288 25.889 19.998 26.203 ;
     RECT  21.42 26.203 21.438 26.333 ;
     RECT  0.108 26.203 19.998 26.525 ;
     RECT  21.492 26.779 21.51 27.211 ;
     RECT  0.108 26.525 19.962 27.355 ;
     RECT  21.456 27.211 21.51 27.473 ;
     RECT  21.456 27.473 21.474 27.509 ;
     RECT  0.108 27.355 20.502 27.635 ;
     RECT  0.144 27.635 20.502 28.363 ;
     RECT  0.108 28.363 20.502 28.445 ;
     RECT  0.144 28.445 20.502 28.481 ;
     RECT  20.484 28.481 20.502 28.679 ;
     RECT  0.144 28.481 19.71 28.715 ;
     RECT  0.18 28.715 19.71 28.781 ;
     RECT  21.492 29.461 21.51 29.693 ;
     RECT  0.324 28.781 19.71 29.803 ;
     RECT  0.324 29.803 19.926 29.947 ;
     RECT  0.144 29.947 19.926 30.145 ;
     RECT  0.144 30.145 19.962 30.365 ;
     RECT  0.324 30.365 19.962 30.883 ;
     RECT  0.324 30.883 19.998 31.421 ;
     RECT  21.492 31.675 21.51 31.757 ;
     RECT  20.52 31.495 20.538 31.996 ;
     RECT  0.324 31.421 19.71 32.107 ;
     RECT  0.144 32.107 19.71 32.251 ;
     RECT  20.52 31.996 20.574 32.251 ;
     RECT  0.144 32.251 20.574 32.429 ;
     RECT  0.144 32.429 20.43 32.909 ;
     RECT  0.144 32.909 19.926 33.005 ;
     RECT  0.324 33.005 19.926 33.691 ;
     RECT  0.324 33.691 20.502 33.835 ;
     RECT  0.324 33.835 20.538 33.853 ;
     RECT  21.492 33.259 21.51 33.989 ;
     RECT  0.324 33.853 20.574 34.013 ;
     RECT  0.324 34.013 20.502 34.267 ;
     RECT  0.144 34.267 20.502 34.397 ;
     RECT  21.42 35.131 21.438 35.261 ;
     RECT  0.324 34.397 20.502 35.563 ;
     RECT  21.42 36.139 21.438 36.269 ;
     RECT  0.324 35.563 20.538 37.246 ;
     RECT  21.492 37.147 21.51 37.427 ;
     RECT  21.42 37.723 21.438 37.997 ;
     RECT  0.324 37.246 20.574 38.045 ;
     RECT  0.324 38.045 20.538 38.299 ;
     RECT  0.144 38.299 20.538 38.333 ;
     RECT  0.144 38.333 19.674 38.429 ;
     RECT  21.492 38.875 21.51 39.011 ;
     RECT  0.324 38.429 19.674 39.163 ;
     RECT  20.484 38.333 20.538 39.163 ;
     RECT  0.324 39.163 20.538 39.485 ;
     RECT  0.324 39.485 19.962 39.629 ;
     RECT  0.324 39.629 19.926 40.441 ;
     RECT  0.324 40.441 20.538 40.493 ;
     RECT  21.492 40.747 21.51 40.937 ;
     RECT  0.324 40.493 19.962 41.323 ;
     RECT  21.492 41.755 21.51 41.819 ;
     RECT  0.324 41.323 20.502 42.053 ;
     RECT  21.42 41.947 21.438 42.077 ;
     RECT  0.324 42.053 20.466 42.509 ;
     RECT  0.324 42.509 19.674 42.619 ;
     RECT  0.144 42.619 19.674 42.749 ;
     RECT  21.492 42.619 21.51 42.907 ;
     RECT  21.456 42.907 21.51 43.097 ;
     RECT  20.448 42.509 20.466 43.141 ;
     RECT  20.448 43.141 20.538 43.373 ;
     RECT  0.324 42.749 19.674 43.375 ;
     RECT  20.448 43.373 20.502 43.375 ;
     RECT  0.324 43.375 20.502 43.637 ;
     RECT  0.324 43.637 20.466 43.661 ;
     RECT  20.448 43.661 20.466 43.673 ;
     RECT  0.324 43.661 19.674 43.771 ;
     RECT  0.144 43.771 19.674 43.901 ;
     RECT  21.492 43.097 21.51 43.915 ;
     RECT  21.456 43.915 21.51 44.203 ;
     RECT  0.324 43.901 19.674 44.635 ;
     RECT  21.42 44.203 21.51 44.789 ;
     RECT  21.42 44.789 21.438 44.909 ;
     RECT  0.324 44.635 19.926 45.067 ;
     RECT  0.144 45.067 19.926 45.197 ;
     RECT  0.324 45.197 19.926 45.49 ;
     RECT  0.324 45.49 19.962 45.787 ;
     RECT  0.324 45.787 19.998 45.931 ;
     RECT  0.144 45.931 19.998 46.061 ;
     RECT  0.324 46.061 19.998 46.795 ;
     RECT  0.324 46.795 20.538 46.813 ;
     RECT  0.324 46.813 20.574 46.939 ;
     RECT  0.144 46.939 20.574 47.117 ;
     RECT  20.484 47.117 20.574 47.261 ;
     RECT  21.492 46.345 21.51 47.371 ;
     RECT  0.144 47.117 19.638 47.645 ;
     RECT  21.456 47.371 21.51 47.957 ;
     RECT  20.484 47.261 20.502 48.299 ;
     RECT  0.324 47.645 19.638 48.379 ;
     RECT  21.492 47.957 21.51 48.811 ;
     RECT  0.324 48.379 19.926 49.099 ;
     RECT  0.144 49.099 20.502 49.229 ;
     RECT  21.456 48.811 21.51 49.579 ;
     RECT  21.42 49.579 21.51 49.709 ;
     RECT  0.324 49.229 20.502 49.855 ;
     RECT  0.324 49.855 20.538 50.141 ;
     RECT  0.324 50.141 19.926 50.251 ;
     RECT  0.144 50.251 19.926 50.381 ;
     RECT  21.492 49.709 21.51 50.683 ;
     RECT  21.456 50.683 21.51 50.927 ;
     RECT  0.324 50.381 19.926 50.935 ;
     RECT  0.324 50.935 20.538 52.123 ;
     RECT  0.144 52.123 20.538 52.253 ;
     RECT  21.492 50.927 21.51 52.555 ;
     RECT  0.324 52.253 20.538 52.817 ;
     RECT  21.42 52.555 21.51 52.843 ;
     RECT  21.348 52.843 21.51 52.979 ;
     RECT  21.348 52.979 21.474 53.123 ;
     RECT  20.52 52.817 20.538 53.165 ;
     RECT  0.324 52.817 19.638 53.527 ;
     RECT  21.348 53.123 21.438 53.549 ;
     RECT  0.108 53.527 19.638 53.707 ;
     RECT  0.108 53.707 19.998 53.741 ;
     RECT  21.348 53.549 21.366 53.933 ;
     RECT  0.324 53.741 19.998 53.995 ;
     RECT  0.324 53.995 20.538 54.605 ;
     RECT  0.324 54.605 20.502 55.867 ;
     RECT  0.324 55.867 20.538 56.155 ;
     RECT  0.324 56.155 20.574 56.633 ;
     RECT  21.492 54.715 21.51 56.669 ;
     RECT  0.324 56.633 20.502 58.081 ;
     RECT  0.324 58.081 20.538 58.315 ;
     RECT  0.144 58.315 20.538 58.349 ;
     RECT  0.144 58.349 20.502 58.445 ;
     RECT  0.216 58.445 20.502 59.099 ;
     RECT  20.484 59.099 20.502 59.323 ;
     RECT  0.216 59.099 19.674 59.467 ;
     RECT  0.108 59.467 19.674 59.765 ;
     RECT  0.144 59.765 19.674 60.029 ;
     RECT  21.492 59.611 21.51 60.107 ;
     RECT  0.288 60.029 19.674 60.187 ;
     RECT  20.484 59.323 20.538 60.187 ;
     RECT  0.288 60.187 20.538 60.889 ;
     RECT  0.288 60.889 20.574 61.085 ;
     RECT  0.288 61.085 20.538 61.223 ;
     RECT  0.324 61.223 20.538 61.229 ;
     RECT  0.324 61.229 20.502 61.799 ;
     RECT  0.324 61.799 20.466 61.889 ;
     RECT  21.492 61.915 21.51 62.203 ;
     RECT  21.456 62.203 21.51 62.303 ;
     RECT  21.456 62.303 21.474 62.491 ;
     RECT  0.324 61.889 19.926 62.539 ;
     RECT  0.144 62.539 19.926 62.609 ;
     RECT  0.144 62.609 19.71 62.669 ;
     RECT  20.448 62.635 20.502 62.815 ;
     RECT  20.448 62.815 20.538 62.957 ;
     RECT  21.42 62.491 21.474 63.113 ;
     RECT  0.288 62.669 19.71 63.355 ;
     RECT  20.448 62.957 20.502 63.355 ;
     RECT  21.492 63.211 21.51 63.419 ;
     RECT  0.288 63.355 20.502 63.689 ;
     RECT  20.484 63.689 20.502 63.779 ;
     RECT  21.42 64.219 21.438 64.349 ;
     RECT  20.52 63.895 20.538 64.363 ;
     RECT  20.52 64.363 20.574 64.541 ;
     RECT  0.288 63.689 19.71 64.697 ;
     RECT  0.36 64.697 19.71 64.769 ;
     RECT  0.396 64.769 19.71 64.795 ;
     RECT  20.484 64.651 20.502 64.795 ;
     RECT  0.396 64.795 20.502 64.967 ;
     RECT  0.396 64.967 19.962 65.849 ;
     RECT  20.484 65.947 20.538 66.011 ;
     RECT  20.484 66.011 20.502 66.659 ;
     RECT  21.492 67.099 21.51 67.387 ;
     RECT  21.456 67.387 21.51 67.433 ;
     RECT  0.396 65.849 19.71 67.441 ;
     RECT  0.396 67.441 19.962 67.565 ;
     RECT  20.484 67.711 20.538 67.853 ;
     RECT  0.396 67.565 19.71 68.377 ;
     RECT  20.484 67.853 20.502 68.395 ;
     RECT  0.108 68.377 19.71 68.429 ;
     RECT  0.396 68.429 19.71 68.521 ;
     RECT  20.448 68.395 20.502 68.521 ;
     RECT  0.396 68.521 20.502 68.819 ;
     RECT  0.396 68.819 19.962 69.005 ;
     RECT  0.396 69.005 19.926 69.493 ;
     RECT  21.492 67.433 21.51 69.629 ;
     RECT  0.108 69.493 19.926 69.899 ;
     RECT  10.44 69.899 19.926 70.123 ;
     RECT  0.108 69.899 9.522 70.169 ;
     RECT  10.44 70.123 20.502 70.303 ;
     RECT  10.44 70.303 20.538 70.445 ;
     RECT  0.108 70.169 8.097 70.733 ;
     RECT  10.44 70.445 20.502 71.375 ;
     RECT  21.492 70.555 21.51 71.707 ;
     RECT  21.456 71.707 21.51 72.023 ;
     RECT  21.456 72.023 21.474 72.059 ;
     RECT  10.515 71.375 20.502 72.701 ;
     RECT  0.432 70.733 8.097 72.733 ;
     RECT  8.82 70.169 9.522 72.733 ;
     RECT  0.432 72.733 9.522 72.869 ;
     RECT  0.432 72.869 8.097 73.103 ;
     RECT  10.515 72.701 18.897 73.579 ;
     RECT  19.62 72.701 20.502 73.579 ;
     RECT  21.492 73.435 21.51 73.643 ;
     RECT  0.468 73.103 8.097 73.679 ;
     RECT  0.468 73.679 6.858 74.477 ;
     RECT  10.515 73.579 20.502 74.489 ;
     RECT  0.468 74.477 6.786 74.587 ;
     RECT  0.108 74.587 6.786 74.621 ;
     RECT  0.108 74.621 6.642 74.759 ;
     RECT  0.108 74.759 0.522 74.765 ;
     RECT  0.468 74.765 0.522 75.029 ;
     RECT  8.928 72.869 9.522 75.029 ;
     RECT  10.515 74.489 20.466 75.053 ;
     RECT  1.62 74.759 6.642 75.119 ;
     RECT  20.412 75.053 20.466 75.227 ;
     RECT  20.448 75.227 20.466 75.263 ;
     RECT  1.62 75.119 4.302 75.389 ;
     RECT  21.492 74.875 21.51 75.595 ;
     RECT  9.396 75.029 9.522 75.659 ;
     RECT  0.468 75.029 0.486 75.767 ;
     RECT  9.432 75.659 9.522 75.929 ;
     RECT  10.515 75.053 19.422 75.929 ;
     RECT  21.456 75.595 21.51 76.073 ;
     RECT  9.504 75.929 9.522 76.199 ;
     RECT  20.484 75.307 20.502 76.306 ;
     RECT  20.448 76.306 20.502 76.469 ;
     RECT  5.115 75.119 6.642 76.507 ;
     RECT  20.52 76.885 20.538 76.925 ;
     RECT  10.515 75.929 12.222 76.939 ;
     RECT  13.215 75.929 19.422 76.939 ;
     RECT  10.515 76.939 19.422 77.009 ;
     RECT  13.176 77.009 19.422 77.081 ;
     RECT  5.115 76.507 6.858 77.117 ;
     RECT  13.176 77.081 19.134 77.117 ;
     RECT  5.115 77.117 6.642 77.189 ;
     RECT  13.176 77.117 19.098 77.279 ;
     RECT  21.492 76.073 21.51 77.323 ;
     RECT  21.456 77.323 21.51 77.611 ;
     RECT  19.908 77.467 19.926 77.621 ;
     RECT  10.515 77.009 12.402 77.819 ;
     RECT  1.62 75.389 4.23 78.061 ;
     RECT  21.42 77.611 21.51 78.077 ;
     RECT  10.515 77.819 11.106 78.089 ;
     RECT  1.62 78.061 4.338 78.091 ;
     RECT  5.115 77.189 5.454 78.091 ;
     RECT  12.24 77.819 12.402 78.091 ;
     RECT  13.176 77.279 19.062 78.091 ;
     RECT  12.24 78.091 19.062 78.187 ;
     RECT  1.62 78.091 5.454 78.205 ;
     RECT  12.24 78.187 19.422 78.269 ;
     RECT  6.516 77.189 6.642 78.467 ;
     RECT  12.636 78.269 19.422 78.629 ;
     RECT  0.036 78.511 0.054 78.667 ;
     RECT  0.036 78.667 0.162 78.701 ;
     RECT  1.404 78.205 5.454 78.745 ;
     RECT  15.192 78.629 19.422 78.763 ;
     RECT  20.484 77.755 20.502 78.763 ;
     RECT  21.456 78.077 21.51 78.773 ;
     RECT  0.108 78.701 0.162 78.781 ;
     RECT  21.492 78.773 21.51 78.809 ;
     RECT  12.636 78.629 14.454 78.899 ;
     RECT  13.215 78.899 14.454 78.935 ;
     RECT  6.516 78.467 6.606 79.007 ;
     RECT  1.404 78.745 5.562 79.169 ;
     RECT  14.436 78.935 14.454 79.169 ;
     RECT  15.192 78.763 20.502 79.241 ;
     RECT  6.516 79.007 6.534 79.313 ;
     RECT  20.484 79.241 20.502 79.349 ;
     RECT  1.404 79.169 5.454 79.439 ;
     RECT  15.192 79.241 19.422 79.439 ;
     RECT  15.915 79.439 19.422 79.619 ;
     RECT  1.404 79.439 5.397 79.667 ;
     RECT  7.815 73.679 8.097 79.667 ;
     RECT  10.515 78.089 10.797 79.667 ;
     RECT  13.215 78.935 13.497 79.667 ;
     RECT  1.404 79.667 5.205 79.709 ;
     RECT  15.915 79.619 18.99 79.709 ;
     RECT  1.404 79.709 4.194 79.745 ;
     RECT  17.136 79.709 17.802 79.781 ;
     RECT  18.615 79.709 18.99 79.781 ;
     RECT  1.404 79.745 3.978 79.937 ;
     RECT  5.115 79.709 5.205 79.937 ;
     RECT  7.815 79.667 7.905 79.937 ;
     RECT  10.515 79.667 10.605 79.937 ;
     RECT  13.215 79.667 13.305 79.937 ;
     RECT  15.915 79.709 16.005 79.937 ;
     RECT  18.615 79.781 18.705 79.937 ;
     RECT  0.108 78.781 0.558 80.093 ;
     RECT  0.108 80.093 0.126 80.237 ;
     RECT  2.556 79.937 3.978 80.525 ;
     RECT  3.456 80.525 3.978 80.669 ;
     RECT  2.556 80.525 2.574 80.813 ;
     RECT  1.404 79.937 1.71 80.957 ;
     RECT  1.692 80.957 1.71 81.101 ;
     RECT  3.96 80.669 3.978 81.245 ;
    LAYER M4 ;
     RECT  0.06 53.712 0.137 81.24 ;
     RECT  0.06 24.912 0.317 52.44 ;
     RECT  0.06 3.024 2.408 23.64 ;
     RECT  0.317 24.912 2.408 27.384 ;
     RECT  0.317 28.512 2.408 52.44 ;
     RECT  0.137 53.856 2.408 81.24 ;
     RECT  2.408 2.148 2.512 81.24 ;
     RECT  2.512 2.418 2.704 81.24 ;
     RECT  2.704 25.008 2.729 27.096 ;
     RECT  2.704 12.288 2.765 15.864 ;
     RECT  2.704 20.304 2.765 21.768 ;
     RECT  2.704 39.6 2.765 41.208 ;
     RECT  2.704 42.24 2.765 47.688 ;
     RECT  2.729 25.008 2.801 25.032 ;
     RECT  2.765 39.6 2.801 41.016 ;
     RECT  2.704 67.104 2.801 75.528 ;
     RECT  2.765 20.304 2.837 21.72 ;
     RECT  2.704 62.208 2.837 65.976 ;
     RECT  2.704 76.56 2.837 81.24 ;
     RECT  2.704 3.312 2.873 7.944 ;
     RECT  2.837 20.304 2.873 21.192 ;
     RECT  2.704 22.752 2.873 23.304 ;
     RECT  2.729 26.064 2.873 27.096 ;
     RECT  2.704 28.512 2.873 33.288 ;
     RECT  2.704 34.368 2.873 35.736 ;
     RECT  2.704 37.44 2.873 38.424 ;
     RECT  2.801 40.032 2.873 41.016 ;
     RECT  2.704 48.672 2.873 49.224 ;
     RECT  2.837 62.496 2.873 62.712 ;
     RECT  2.765 14.736 2.909 15.288 ;
     RECT  2.873 23.28 2.909 23.304 ;
     RECT  2.873 40.032 2.909 40.968 ;
     RECT  2.765 42.24 2.909 47.64 ;
     RECT  2.801 67.104 2.909 73.944 ;
     RECT  2.909 43.872 2.945 47.64 ;
     RECT  2.873 28.752 2.981 33.288 ;
     RECT  2.873 34.368 2.981 34.392 ;
     RECT  2.945 43.872 2.981 47.352 ;
     RECT  2.909 40.8 3.011 40.968 ;
     RECT  2.981 46.032 3.017 47.352 ;
     RECT  2.704 53.856 3.017 56.616 ;
     RECT  2.704 60 3.017 60.936 ;
     RECT  2.981 30.72 3.089 31.08 ;
     RECT  2.873 35.712 3.089 35.736 ;
     RECT  2.873 38.16 3.089 38.184 ;
     RECT  2.981 43.872 3.089 44.664 ;
     RECT  2.704 50.352 3.089 51.144 ;
     RECT  2.873 26.304 3.125 27.096 ;
     RECT  2.981 28.752 3.125 29.544 ;
     RECT  2.981 32.208 3.125 33.288 ;
     RECT  3.017 54.72 3.125 56.616 ;
     RECT  2.704 57.6 3.125 58.824 ;
     RECT  2.837 63.792 3.125 63.816 ;
     RECT  2.837 78.096 3.133 81.24 ;
     RECT  2.909 42.24 3.161 42.888 ;
     RECT  2.873 49.2 3.197 49.224 ;
     RECT  3.125 54.72 3.197 56.04 ;
     RECT  2.704 9.072 3.233 10.968 ;
     RECT  3.125 32.256 3.233 33.288 ;
     RECT  3.017 46.032 3.233 46.056 ;
     RECT  3.011 40.944 3.269 40.968 ;
     RECT  3.089 50.352 3.305 50.376 ;
     RECT  2.704 52.224 3.305 52.248 ;
     RECT  3.017 60.336 3.305 60.936 ;
     RECT  3.197 54.72 3.341 55.464 ;
     RECT  3.089 30.72 3.347 30.936 ;
     RECT  3.161 42.24 3.347 42.696 ;
     RECT  3.341 54.72 3.377 54.84 ;
     RECT  3.089 43.872 3.413 43.896 ;
     RECT  3.125 57.6 3.413 57.624 ;
     RECT  3.305 60.912 3.413 60.936 ;
     RECT  3.133 78.672 3.413 81.24 ;
     RECT  3.347 42.432 3.449 42.696 ;
     RECT  3.233 9.072 3.485 10.2 ;
     RECT  3.413 80.64 3.485 81.24 ;
     RECT  2.909 67.296 3.601 73.944 ;
     RECT  3.377 54.72 3.737 54.744 ;
     RECT  2.765 12.288 3.769 13.416 ;
     RECT  2.909 14.736 3.769 14.76 ;
     RECT  3.347 30.768 3.773 30.888 ;
     RECT  2.873 62.544 3.809 62.712 ;
     RECT  2.704 16.848 3.841 16.872 ;
     RECT  2.837 76.56 3.841 76.776 ;
     RECT  3.773 30.768 3.845 30.792 ;
     RECT  3.017 47.328 3.881 47.352 ;
     RECT  3.485 9.072 3.949 10.152 ;
     RECT  3.769 12.288 3.949 14.76 ;
     RECT  2.873 21.12 3.949 21.192 ;
     RECT  3.601 68.976 3.949 73.944 ;
     RECT  2.801 75.216 3.949 75.528 ;
     RECT  3.485 81.216 3.989 81.24 ;
     RECT  3.949 12.288 4.057 15.336 ;
     RECT  3.841 16.368 4.057 16.872 ;
     RECT  3.949 21.12 4.057 21.528 ;
     RECT  3.949 68.976 4.141 75.528 ;
     RECT  4.057 12.288 4.201 16.872 ;
     RECT  3.125 26.304 4.237 26.328 ;
     RECT  2.873 3.312 4.309 7.896 ;
     RECT  3.949 8.976 4.309 10.152 ;
     RECT  4.201 12.288 4.417 18.168 ;
     RECT  3.949 19.248 4.417 19.272 ;
     RECT  3.125 58.608 4.417 58.824 ;
     RECT  3.413 78.72 4.597 79.608 ;
     RECT  3.841 76.56 4.633 77.688 ;
     RECT  4.597 78.672 4.633 79.608 ;
     RECT  4.261 2.064 5.108 2.088 ;
     RECT  4.309 3.312 5.108 10.152 ;
     RECT  4.417 12.288 5.108 19.32 ;
     RECT  4.057 21.12 5.108 22.008 ;
     RECT  4.237 26.304 5.108 26.664 ;
     RECT  3.697 27.648 5.108 27.672 ;
     RECT  3.125 28.752 5.108 28.776 ;
     RECT  3.233 33.072 5.108 33.096 ;
     RECT  4.165 42.768 5.108 42.792 ;
     RECT  4.021 49.008 5.108 49.032 ;
     RECT  4.417 58.608 5.108 59.304 ;
     RECT  3.809 62.544 5.108 62.568 ;
     RECT  2.837 65.232 5.108 65.976 ;
     RECT  3.601 67.296 5.108 67.704 ;
     RECT  4.141 68.976 5.108 69.768 ;
     RECT  4.141 70.896 5.108 75.528 ;
     RECT  4.633 76.56 5.108 79.608 ;
     RECT  5.108 2.064 5.212 79.932 ;
     RECT  5.212 2.064 5.321 79.752 ;
     RECT  5.321 2.208 5.404 79.752 ;
     RECT  5.404 76.56 5.987 77.688 ;
     RECT  5.404 11.76 6.083 17.112 ;
     RECT  6.083 15.984 6.131 17.112 ;
     RECT  5.404 18.144 6.179 19.32 ;
     RECT  5.404 59.28 6.227 59.304 ;
     RECT  5.404 26.304 6.433 26.664 ;
     RECT  5.404 27.648 6.433 27.672 ;
     RECT  5.404 78.72 6.563 78.744 ;
     RECT  6.641 35.376 6.661 35.4 ;
     RECT  6.661 35.088 6.725 35.4 ;
     RECT  6.725 35.088 6.748 35.112 ;
     RECT  6.433 26.304 6.761 27.672 ;
     RECT  5.404 69.696 6.797 75.528 ;
     RECT  6.716 38.88 6.803 39.192 ;
     RECT  6.716 43.44 6.803 43.8 ;
     RECT  6.716 55.392 6.803 55.944 ;
     RECT  6.716 60.48 6.803 60.792 ;
     RECT  5.404 2.208 6.829 2.232 ;
     RECT  5.987 76.56 6.829 77.592 ;
     RECT  6.829 2.064 7.808 2.232 ;
     RECT  5.404 3.312 7.808 10.152 ;
     RECT  6.083 11.76 7.808 14.76 ;
     RECT  6.131 15.984 7.808 16.968 ;
     RECT  6.179 19.104 7.808 19.32 ;
     RECT  5.404 21.12 7.808 22.008 ;
     RECT  6.761 26.304 7.808 26.664 ;
     RECT  6.761 27.648 7.808 27.672 ;
     RECT  5.404 28.752 7.808 28.776 ;
     RECT  5.404 54.384 7.808 54.408 ;
     RECT  5.404 62.544 7.808 62.568 ;
     RECT  5.404 65.232 7.808 65.832 ;
     RECT  5.404 67.296 7.808 67.992 ;
     RECT  6.797 69.696 7.808 74.472 ;
     RECT  6.797 75.504 7.808 75.528 ;
     RECT  6.829 76.512 7.808 77.592 ;
     RECT  5.404 79.728 7.808 79.752 ;
     RECT  7.808 2.064 7.912 79.932 ;
     RECT  7.912 2.064 8.104 79.752 ;
     RECT  8.104 50.736 8.813 50.76 ;
     RECT  8.104 3.312 8.867 10.152 ;
     RECT  8.104 15.984 9.349 16.968 ;
     RECT  8.104 75.504 9.395 75.528 ;
     RECT  9.349 15.984 9.397 17.448 ;
     RECT  8.104 65.232 9.491 65.736 ;
     RECT  9.397 15.984 9.493 18.024 ;
     RECT  8.104 19.104 9.493 19.32 ;
     RECT  9.491 65.712 9.539 65.736 ;
     RECT  8.104 57.84 10.069 57.864 ;
     RECT  9.997 30.864 10.117 30.888 ;
     RECT  8.104 2.064 10.508 2.088 ;
     RECT  8.867 3.312 10.508 9.816 ;
     RECT  8.104 11.76 10.508 15 ;
     RECT  9.493 15.984 10.508 19.32 ;
     RECT  8.104 21.12 10.508 22.008 ;
     RECT  8.104 26.304 10.508 26.664 ;
     RECT  8.104 27.648 10.508 27.672 ;
     RECT  10.117 30.768 10.508 30.888 ;
     RECT  9.781 38.784 10.508 38.808 ;
     RECT  9.529 49.104 10.508 49.128 ;
     RECT  8.104 54.384 10.508 54.984 ;
     RECT  10.069 57.312 10.508 57.864 ;
     RECT  8.104 62.544 10.508 62.568 ;
     RECT  8.104 67.296 10.508 67.896 ;
     RECT  8.104 69.792 10.508 74.376 ;
     RECT  8.104 76.512 10.508 77.112 ;
     RECT  8.104 79.728 10.508 79.752 ;
     RECT  10.508 2.064 10.612 79.932 ;
     RECT  10.612 2.064 10.804 79.752 ;
     RECT  10.804 15.984 10.865 19.896 ;
     RECT  10.804 21.12 10.865 23.016 ;
     RECT  10.865 21.216 11.081 23.016 ;
     RECT  10.804 69.696 11.117 72.744 ;
     RECT  10.804 76.512 11.123 77.064 ;
     RECT  10.804 2.064 11.797 2.232 ;
     RECT  11.081 21.216 11.869 22.824 ;
     RECT  11.797 2.064 11.893 2.28 ;
     RECT  10.804 3.312 11.893 9.624 ;
     RECT  11.855 35.328 11.893 35.352 ;
     RECT  11.869 46.176 11.9 46.2 ;
     RECT  10.804 67.68 11.905 67.992 ;
     RECT  11.9 46.176 11.941 46.776 ;
     RECT  11.893 35.328 11.98 35.976 ;
     RECT  10.804 42.144 11.987 42.168 ;
     RECT  11.869 43.248 11.987 43.272 ;
     RECT  10.804 31.776 11.989 31.8 ;
     RECT  10.804 54.384 11.989 54.984 ;
     RECT  11.905 67.296 11.989 67.992 ;
     RECT  11.117 69.696 11.989 72.696 ;
     RECT  10.804 56.784 11.996 57.864 ;
     RECT  10.804 62.544 12.044 62.568 ;
     RECT  10.804 64.128 12.044 64.152 ;
     RECT  10.804 26.304 12.049 26.664 ;
     RECT  10.804 27.648 12.049 27.672 ;
     RECT  11.989 33.168 12.085 33.192 ;
     RECT  11.948 66.096 12.085 66.12 ;
     RECT  11.989 67.296 12.085 72.696 ;
     RECT  11.989 54.096 12.092 55.416 ;
     RECT  11.989 30.864 12.121 31.8 ;
     RECT  12.085 33.072 12.131 33.192 ;
     RECT  12.044 62.16 12.131 62.568 ;
     RECT  12.049 26.304 12.133 27.672 ;
     RECT  12.121 50.928 12.133 51.768 ;
     RECT  12.085 65.808 12.149 72.696 ;
     RECT  10.804 73.92 12.149 74.472 ;
     RECT  12.149 65.808 12.161 74.472 ;
     RECT  12.131 33.072 12.169 33.096 ;
     RECT  12.092 53.52 12.179 55.416 ;
     RECT  11.996 56.784 12.197 58.392 ;
     RECT  10.804 38.784 12.229 38.808 ;
     RECT  12.049 39.888 12.229 39.912 ;
     RECT  12.085 59.856 12.229 59.88 ;
     RECT  10.804 24.48 12.233 24.504 ;
     RECT  12.133 26.304 12.233 28.344 ;
     RECT  11.893 37.056 12.265 37.08 ;
     RECT  11.123 76.752 12.277 77.064 ;
     RECT  12.121 30.768 12.301 31.8 ;
     RECT  12.265 37.056 12.301 37.176 ;
     RECT  10.865 16.08 12.337 19.896 ;
     RECT  11.869 20.976 12.337 22.824 ;
     RECT  12.197 57.84 12.373 58.392 ;
     RECT  12.077 60.96 12.373 60.984 ;
     RECT  11.893 2.064 12.553 9.624 ;
     RECT  12.131 62.544 12.565 62.568 ;
     RECT  12.044 63.696 12.565 64.152 ;
     RECT  12.161 65.808 12.565 68.088 ;
     RECT  12.337 16.08 12.589 22.824 ;
     RECT  11.98 35.328 12.661 35.352 ;
     RECT  12.133 50.928 12.661 52.344 ;
     RECT  12.301 37.056 12.805 37.272 ;
     RECT  12.805 36.816 12.841 37.272 ;
     RECT  12.229 38.544 12.841 39.912 ;
     RECT  12.277 76.752 12.853 77.544 ;
     RECT  12.725 78.672 12.853 78.696 ;
     RECT  12.179 54.336 12.949 55.416 ;
     RECT  12.553 2.016 12.985 9.624 ;
     RECT  12.661 50.928 12.997 53.016 ;
     RECT  10.804 49.536 13.021 49.56 ;
     RECT  10.804 11.424 13.045 15 ;
     RECT  12.589 16.08 13.045 23.688 ;
     RECT  12.301 30 13.045 31.8 ;
     RECT  12.841 36.816 13.093 39.912 ;
     RECT  10.804 44.832 13.093 44.856 ;
     RECT  13.021 48.768 13.093 49.56 ;
     RECT  12.997 50.64 13.093 53.016 ;
     RECT  12.229 59.76 13.093 59.88 ;
     RECT  12.373 60.96 13.093 61.512 ;
     RECT  11.941 46.176 13.129 47.352 ;
     RECT  13.093 48.768 13.129 53.016 ;
     RECT  12.233 26.304 13.165 26.664 ;
     RECT  12.985 2.016 13.208 9.816 ;
     RECT  13.045 11.424 13.208 23.688 ;
     RECT  13.165 26.112 13.208 26.664 ;
     RECT  12.233 27.648 13.208 27.768 ;
     RECT  13.045 29.232 13.208 31.8 ;
     RECT  12.661 34.752 13.208 35.352 ;
     RECT  13.093 36.528 13.208 39.912 ;
     RECT  13.165 41.232 13.208 41.256 ;
     RECT  13.093 44.352 13.208 44.856 ;
     RECT  13.129 46.176 13.208 53.016 ;
     RECT  12.949 54.336 13.208 55.656 ;
     RECT  12.197 56.784 13.208 56.808 ;
     RECT  12.373 57.84 13.208 58.728 ;
     RECT  13.093 59.76 13.208 61.512 ;
     RECT  12.565 62.544 13.208 68.088 ;
     RECT  12.161 69.36 13.208 74.472 ;
     RECT  12.853 76.752 13.208 78.696 ;
     RECT  10.804 79.728 13.208 79.752 ;
     RECT  13.208 2.016 13.312 79.932 ;
     RECT  13.312 2.016 13.504 79.752 ;
     RECT  13.504 76.752 13.601 77.64 ;
     RECT  13.504 21.216 13.619 28.44 ;
     RECT  13.504 41.232 13.619 43.848 ;
     RECT  13.504 69.312 13.619 72.552 ;
     RECT  13.504 60.432 13.667 65.16 ;
     RECT  13.619 69.456 13.667 72.552 ;
     RECT  13.504 17.376 13.673 20.232 ;
     RECT  13.504 36.384 13.709 39.96 ;
     RECT  13.504 59.136 13.811 59.256 ;
     RECT  13.811 59.232 13.817 59.256 ;
     RECT  13.504 45.024 13.853 57.864 ;
     RECT  13.504 2.016 13.859 15 ;
     RECT  13.859 10.992 13.872 13.944 ;
     RECT  13.667 60.432 13.933 64.872 ;
     RECT  13.673 17.472 13.955 20.232 ;
     RECT  13.853 45.024 13.955 55.128 ;
     RECT  13.955 51.744 13.996 55.128 ;
     RECT  13.996 51.744 14.051 54.744 ;
     RECT  13.872 11.28 14.195 13.944 ;
     RECT  13.504 66.672 14.357 68.28 ;
     RECT  13.504 31.824 14.393 33.768 ;
     RECT  13.955 45.024 14.429 50.136 ;
     RECT  14.357 66.672 14.465 66.696 ;
     RECT  14.393 32.64 14.531 33.768 ;
     RECT  13.619 21.216 14.579 27.672 ;
     RECT  13.933 60.816 14.579 64.872 ;
     RECT  13.859 14.976 14.605 15 ;
     RECT  13.504 16.08 14.605 16.392 ;
     RECT  13.601 76.896 14.605 77.64 ;
     RECT  14.531 32.64 14.627 33.336 ;
     RECT  13.667 69.696 14.641 72.552 ;
     RECT  14.533 66.144 14.645 66.168 ;
     RECT  13.504 74.064 14.677 75.384 ;
     RECT  14.357 67.68 14.713 68.28 ;
     RECT  14.641 69.552 14.713 72.552 ;
     RECT  14.579 26.208 14.732 27.672 ;
     RECT  13.504 34.752 14.732 34.776 ;
     RECT  14.732 26.208 14.741 27.864 ;
     RECT  14.579 60.816 14.771 64.584 ;
     RECT  13.709 36.384 14.773 37.896 ;
     RECT  13.709 38.928 14.773 39.96 ;
     RECT  13.504 29.472 14.78 29.496 ;
     RECT  14.771 60.864 14.789 64.584 ;
     RECT  14.78 29.472 14.821 29.928 ;
     RECT  14.713 67.68 14.821 72.552 ;
     RECT  14.677 74.064 14.821 75.432 ;
     RECT  13.955 17.472 14.825 19.896 ;
     RECT  14.732 34.512 14.825 34.776 ;
     RECT  14.821 29.088 14.867 29.928 ;
     RECT  14.429 45.024 14.867 49.08 ;
     RECT  14.821 67.68 14.869 72.744 ;
     RECT  14.821 73.92 14.869 75.432 ;
     RECT  14.773 36.384 14.897 39.96 ;
     RECT  13.853 56.16 14.897 57.864 ;
     RECT  14.741 26.208 14.917 27.96 ;
     RECT  14.867 29.088 14.917 29.112 ;
     RECT  14.869 67.68 14.924 75.432 ;
     RECT  14.605 76.896 14.924 78.12 ;
     RECT  14.605 14.976 14.965 16.392 ;
     RECT  14.825 17.472 14.965 19.8 ;
     RECT  13.619 42.096 14.972 43.848 ;
     RECT  14.972 41.232 15.013 43.848 ;
     RECT  14.867 45.024 15.013 47.64 ;
     RECT  14.051 51.744 15.037 54.696 ;
     RECT  14.897 38.928 15.073 39.96 ;
     RECT  15.013 41.232 15.073 47.64 ;
     RECT  13.859 2.016 15.109 9.72 ;
     RECT  14.897 56.16 15.109 57.048 ;
     RECT  15.109 1.872 15.145 9.72 ;
     RECT  15.037 51.744 15.157 54.888 ;
     RECT  15.109 56.112 15.205 57.048 ;
     RECT  15.116 58.08 15.253 58.104 ;
     RECT  15.205 56.016 15.301 57.048 ;
     RECT  15.145 1.872 15.317 9.864 ;
     RECT  14.195 11.28 15.349 13.32 ;
     RECT  14.965 14.976 15.349 19.8 ;
     RECT  15.325 59.856 15.397 59.88 ;
     RECT  14.924 67.68 15.469 78.12 ;
     RECT  15.397 59.52 15.493 59.88 ;
     RECT  14.579 21.216 15.505 24.504 ;
     RECT  15.469 67.632 15.613 78.12 ;
     RECT  15.445 35.04 15.685 35.064 ;
     RECT  15.613 67.632 15.793 78.696 ;
     RECT  15.317 1.872 15.908 10.248 ;
     RECT  15.349 11.28 15.908 19.8 ;
     RECT  15.505 21.12 15.908 24.504 ;
     RECT  14.917 26.208 15.908 29.112 ;
     RECT  14.485 31.2 15.908 31.224 ;
     RECT  14.627 32.736 15.908 33.336 ;
     RECT  15.685 35.04 15.908 35.4 ;
     RECT  14.897 36.384 15.908 37.656 ;
     RECT  15.073 38.928 15.908 47.64 ;
     RECT  14.867 48.672 15.908 49.08 ;
     RECT  14.429 50.112 15.908 50.136 ;
     RECT  15.157 51.504 15.908 54.888 ;
     RECT  15.301 55.92 15.908 57.048 ;
     RECT  15.253 58.08 15.908 58.44 ;
     RECT  15.493 59.424 15.908 59.88 ;
     RECT  14.789 61.008 15.908 64.584 ;
     RECT  15.865 66.576 15.908 66.6 ;
     RECT  15.793 67.584 15.908 78.696 ;
     RECT  13.504 79.728 15.908 79.752 ;
     RECT  15.865 0.864 15.937 0.888 ;
     RECT  15.908 1.872 15.937 79.932 ;
     RECT  15.937 0.864 16.012 79.932 ;
     RECT  16.012 0.864 16.204 79.752 ;
     RECT  16.204 74.112 16.595 79.752 ;
     RECT  16.204 23.856 16.805 29.112 ;
     RECT  16.805 23.904 17.123 29.112 ;
     RECT  16.204 40.704 17.123 57.096 ;
     RECT  17.123 23.904 17.219 29.016 ;
     RECT  16.204 30.816 17.341 30.84 ;
     RECT  16.204 32.736 17.417 39.576 ;
     RECT  17.123 40.704 17.417 57.048 ;
     RECT  17.219 23.904 17.453 28.968 ;
     RECT  16.204 62.256 17.485 73.032 ;
     RECT  17.417 40.704 17.489 51.096 ;
     RECT  17.341 30.72 17.521 30.84 ;
     RECT  17.521 30.72 17.525 31.752 ;
     RECT  17.417 33.072 17.525 39.576 ;
     RECT  17.525 33.888 17.557 39.576 ;
     RECT  17.489 40.704 17.557 48.264 ;
     RECT  16.204 60.768 17.557 60.984 ;
     RECT  16.204 0.864 17.561 22.824 ;
     RECT  17.485 62.208 17.593 73.032 ;
     RECT  16.595 74.112 17.593 79.512 ;
     RECT  17.557 60.336 17.701 60.984 ;
     RECT  17.561 14.448 18.205 22.824 ;
     RECT  17.453 23.904 18.205 28.44 ;
     RECT  17.489 49.536 18.565 51.096 ;
     RECT  17.417 52.128 18.565 57.048 ;
     RECT  17.561 0.864 18.608 13.416 ;
     RECT  18.205 14.448 18.608 28.44 ;
     RECT  17.525 31.68 18.608 31.752 ;
     RECT  17.557 33.888 18.608 48.264 ;
     RECT  18.565 49.536 18.608 57.048 ;
     RECT  16.204 59.136 18.608 59.16 ;
     RECT  17.701 60.144 18.608 60.984 ;
     RECT  17.593 62.208 18.608 79.512 ;
     RECT  18.608 0.864 18.712 79.932 ;
     RECT  18.712 0.864 18.904 79.662 ;
     RECT  18.904 10.608 19.037 28.44 ;
     RECT  18.904 0.864 19.897 9.528 ;
     RECT  19.037 10.608 19.897 10.968 ;
     RECT  18.904 29.52 19.897 32.136 ;
     RECT  18.904 33.408 19.897 38.616 ;
     RECT  18.904 39.744 19.897 43.224 ;
     RECT  18.904 44.352 19.897 51.72 ;
     RECT  18.904 52.704 19.897 53.928 ;
     RECT  18.904 55.008 19.897 57.048 ;
     RECT  18.904 59.184 19.897 60.36 ;
     RECT  19.897 29.52 19.933 43.224 ;
     RECT  19.897 44.352 19.933 57.048 ;
     RECT  19.897 58.464 19.933 60.36 ;
     RECT  18.904 61.776 19.933 74.616 ;
     RECT  18.904 75.744 19.933 78.936 ;
     RECT  19.897 0.864 20.437 10.968 ;
     RECT  19.037 11.952 20.437 28.104 ;
     RECT  20.437 0.864 20.473 28.104 ;
     RECT  19.933 58.464 20.509 78.936 ;
     RECT  20.473 0.72 21.564 28.248 ;
     RECT  19.933 29.52 21.564 57.048 ;
     RECT  20.509 58.32 21.564 78.936 ;
    LAYER M5 ;
     RECT  4.272 2.053 4.296 2.137 ;
     RECT  9.792 0.016 9.816 2.137 ;
     RECT  19.056 2.053 19.08 2.137 ;
     RECT  2.4 2.137 2.52 2.151 ;
     RECT  4.272 2.137 5.22 2.151 ;
     RECT  7.8 2.137 7.92 2.151 ;
     RECT  9.792 2.137 10.62 2.151 ;
     RECT  13.2 2.137 13.32 2.151 ;
     RECT  15.9 2.137 16.02 2.151 ;
     RECT  18.6 2.137 19.08 2.243 ;
     RECT  13.2 2.151 13.512 2.773 ;
     RECT  11.904 2.245 11.928 2.915 ;
     RECT  12.96 2.773 13.512 2.917 ;
     RECT  2.4 2.151 2.712 3.301 ;
     RECT  4.272 2.151 5.412 3.301 ;
     RECT  15.9 2.151 16.212 3.685 ;
     RECT  12.96 2.917 14.088 3.877 ;
     RECT  15.216 3.685 16.212 3.877 ;
     RECT  12.96 3.877 16.212 4.165 ;
     RECT  12.576 4.165 16.212 4.357 ;
     RECT  12.288 4.357 16.212 4.645 ;
     RECT  12.288 4.645 17.016 4.787 ;
     RECT  0.48 3.829 0.504 5.461 ;
     RECT  9.792 2.151 10.812 5.557 ;
     RECT  0.144 5.461 0.504 5.603 ;
     RECT  9.792 5.557 11.112 6.037 ;
     RECT  9.792 6.037 11.208 6.133 ;
     RECT  12.288 4.787 16.212 6.133 ;
     RECT  7.8 2.151 8.112 6.613 ;
     RECT  21.408 6.517 21.432 6.659 ;
     RECT  7.104 6.613 8.112 6.661 ;
     RECT  2.4 3.301 5.412 6.805 ;
     RECT  0.48 5.603 0.504 7.381 ;
     RECT  9.792 6.133 16.212 8.003 ;
     RECT  2.208 6.805 5.412 8.197 ;
     RECT  6.576 6.661 8.112 8.197 ;
     RECT  2.208 8.197 8.112 8.965 ;
     RECT  9.792 8.003 11.208 8.965 ;
     RECT  12.192 8.003 16.212 9.253 ;
     RECT  12.192 9.253 17.112 9.493 ;
     RECT  18.6 2.243 18.912 9.493 ;
     RECT  0.48 7.381 1.128 12.277 ;
     RECT  2.208 8.965 11.208 12.277 ;
     RECT  0.48 12.277 11.208 12.517 ;
     RECT  12.192 9.493 18.912 12.517 ;
     RECT  0.48 12.517 18.912 13.859 ;
     RECT  0.48 13.859 11.208 16.405 ;
     RECT  12.192 13.859 18.912 16.405 ;
     RECT  19.92 16.837 19.944 17.027 ;
     RECT  21.408 22.645 21.432 22.787 ;
     RECT  0.48 16.405 18.912 29.509 ;
     RECT  0.144 29.509 18.912 29.651 ;
     RECT  0.48 29.651 18.912 33.829 ;
     RECT  0.144 33.829 18.912 33.971 ;
     RECT  0.48 33.971 18.912 42.469 ;
     RECT  0.144 42.469 18.912 42.611 ;
     RECT  0.48 42.611 18.912 44.245 ;
     RECT  0.144 44.245 18.912 44.771 ;
     RECT  0.48 44.771 18.912 46.501 ;
     RECT  0.144 46.501 18.912 46.597 ;
     RECT  0.144 46.597 19.896 46.643 ;
     RECT  0.48 46.643 19.896 46.787 ;
     RECT  0.48 46.787 18.912 48.661 ;
     RECT  0.144 48.661 18.912 48.803 ;
     RECT  0.48 48.803 18.912 59.891 ;
     RECT  0.48 59.891 11.16 60.949 ;
     RECT  12.192 59.891 18.912 60.949 ;
     RECT  0.48 60.949 18.912 62.195 ;
     RECT  0.48 62.195 11.16 63.685 ;
     RECT  12.192 62.195 18.912 63.685 ;
     RECT  0.48 63.685 18.912 64.163 ;
     RECT  0.48 64.163 11.112 66.085 ;
     RECT  12.096 64.163 18.912 66.085 ;
     RECT  0.48 66.085 18.912 66.517 ;
     RECT  0.48 66.517 19.32 66.707 ;
     RECT  0.48 66.707 19.032 67.331 ;
     RECT  0.48 67.331 18.912 68.531 ;
     RECT  0.528 68.531 18.912 68.915 ;
     RECT  12.192 68.915 18.912 71.507 ;
     RECT  0.528 68.915 11.112 71.891 ;
     RECT  4.608 71.891 11.112 71.987 ;
     RECT  12.192 71.507 16.632 72.275 ;
     RECT  17.664 71.507 18.912 72.517 ;
     RECT  17.664 72.517 19.368 72.707 ;
     RECT  0.528 71.891 3.192 72.755 ;
     RECT  12.192 72.275 16.584 73.571 ;
     RECT  0.528 72.755 3.096 73.859 ;
     RECT  9.36 71.987 11.112 75.539 ;
     RECT  17.664 72.707 18.912 76.499 ;
     RECT  9.936 75.539 11.112 76.547 ;
     RECT  0.528 73.859 0.552 76.595 ;
     RECT  9.936 76.547 10.812 77.123 ;
     RECT  12.288 73.571 16.584 77.555 ;
     RECT  4.608 71.987 8.112 77.603 ;
     RECT  12.768 77.555 16.584 77.651 ;
     RECT  4.608 77.603 6.552 77.699 ;
     RECT  1.68 73.859 3.096 78.131 ;
     RECT  14.688 77.651 16.584 78.131 ;
     RECT  4.608 77.699 5.412 78.707 ;
     RECT  12.768 77.651 13.512 78.707 ;
     RECT  15.648 78.131 16.584 78.707 ;
     RECT  6.528 77.699 6.552 78.755 ;
     RECT  1.68 78.131 2.712 78.995 ;
     RECT  4.704 78.707 5.412 79.283 ;
     RECT  2.16 78.995 2.712 79.331 ;
     RECT  2.256 79.331 2.712 79.475 ;
     RECT  15.9 78.707 16.584 79.763 ;
     RECT  2.4 79.475 2.712 79.929 ;
     RECT  5.1 79.283 5.412 79.929 ;
     RECT  7.8 77.603 8.112 79.929 ;
     RECT  10.5 77.123 10.812 79.929 ;
     RECT  13.2 78.707 13.512 79.929 ;
     RECT  15.9 79.763 16.212 79.929 ;
     RECT  18.6 76.499 18.912 79.929 ;
     RECT  2.4 79.929 2.52 79.943 ;
     RECT  5.1 79.929 5.22 79.943 ;
     RECT  7.8 79.929 7.92 79.943 ;
     RECT  10.5 79.929 10.62 79.943 ;
     RECT  13.2 79.929 13.32 79.943 ;
     RECT  15.9 79.929 16.02 79.943 ;
     RECT  18.6 79.929 18.72 79.943 ;
  END
END qkd_rlys_528
END LIBRARY
